VERSION 5.8 ;
BUSBITCHARS "[]" ;
DIVIDERCHAR "/" ;
UNITS
    DATABASE MICRONS 1000 ;
END UNITS

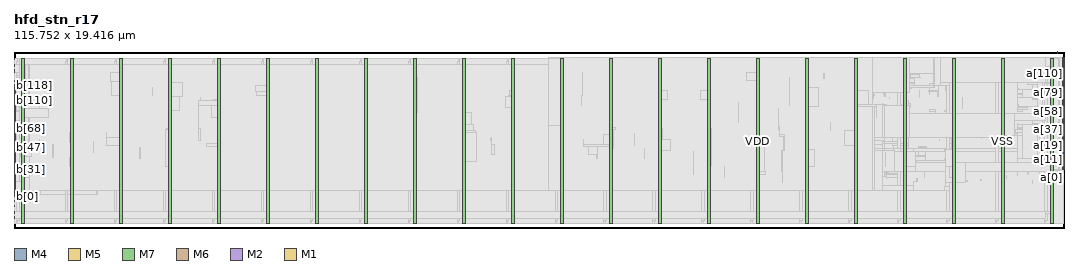
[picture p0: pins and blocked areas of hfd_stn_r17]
MACRO hfd_stn_r17
  FOREIGN hfd_stn_r17 0 0 ;
  CLASS BLOCK ;
  SIZE 115.752 BY 19.416 ;
  PIN a[0]
    DIRECTION INPUT ;
    USE SIGNAL ;
    PORT
      LAYER M4 ;
        RECT  115.56 6.432 115.752 6.456 ;
    END
  END a[0]
  PIN a[100]
    DIRECTION INPUT ;
    USE SIGNAL ;
    PORT
      LAYER M4 ;
        RECT  115.56 16.032 115.752 16.056 ;
    END
  END a[100]
  PIN a[101]
    DIRECTION INPUT ;
    USE SIGNAL ;
    PORT
      LAYER M4 ;
        RECT  115.56 16.128 115.752 16.152 ;
    END
  END a[101]
  PIN a[102]
    DIRECTION INPUT ;
    USE SIGNAL ;
    PORT
      LAYER M4 ;
        RECT  115.56 16.224 115.752 16.248 ;
    END
  END a[102]
  PIN a[103]
    DIRECTION INPUT ;
    USE SIGNAL ;
    PORT
      LAYER M4 ;
        RECT  115.56 16.32 115.752 16.344 ;
    END
  END a[103]
  PIN a[104]
    DIRECTION INPUT ;
    USE SIGNAL ;
    PORT
      LAYER M4 ;
        RECT  115.56 16.416 115.752 16.44 ;
    END
  END a[104]
  PIN a[105]
    DIRECTION INPUT ;
    USE SIGNAL ;
    PORT
      LAYER M4 ;
        RECT  115.56 16.512 115.752 16.536 ;
    END
  END a[105]
  PIN a[106]
    DIRECTION INPUT ;
    USE SIGNAL ;
    PORT
      LAYER M4 ;
        RECT  115.56 16.608 115.752 16.632 ;
    END
  END a[106]
  PIN a[107]
    DIRECTION INPUT ;
    USE SIGNAL ;
    PORT
      LAYER M4 ;
        RECT  115.56 16.704 115.752 16.728 ;
    END
  END a[107]
  PIN a[108]
    DIRECTION INPUT ;
    USE SIGNAL ;
    PORT
      LAYER M4 ;
        RECT  115.56 16.8 115.752 16.824 ;
    END
  END a[108]
  PIN a[109]
    DIRECTION INPUT ;
    USE SIGNAL ;
    PORT
      LAYER M4 ;
        RECT  115.56 16.896 115.752 16.92 ;
    END
  END a[109]
  PIN a[10]
    DIRECTION INPUT ;
    USE SIGNAL ;
    PORT
      LAYER M4 ;
        RECT  115.56 7.392 115.752 7.416 ;
    END
  END a[10]
  PIN a[110]
    DIRECTION INPUT ;
    USE SIGNAL ;
    PORT
      LAYER M4 ;
        RECT  115.56 16.992 115.752 17.016 ;
    END
  END a[110]
  PIN a[111]
    DIRECTION INPUT ;
    USE SIGNAL ;
    PORT
      LAYER M4 ;
        RECT  115.56 17.088 115.752 17.112 ;
    END
  END a[111]
  PIN a[112]
    DIRECTION INPUT ;
    USE SIGNAL ;
    PORT
      LAYER M4 ;
        RECT  115.56 17.184 115.752 17.208 ;
    END
  END a[112]
  PIN a[113]
    DIRECTION INPUT ;
    USE SIGNAL ;
    PORT
      LAYER M4 ;
        RECT  115.56 17.28 115.752 17.304 ;
    END
  END a[113]
  PIN a[114]
    DIRECTION INPUT ;
    USE SIGNAL ;
    PORT
      LAYER M4 ;
        RECT  115.56 17.376 115.752 17.4 ;
    END
  END a[114]
  PIN a[115]
    DIRECTION INPUT ;
    USE SIGNAL ;
    PORT
      LAYER M4 ;
        RECT  115.56 17.472 115.752 17.496 ;
    END
  END a[115]
  PIN a[116]
    DIRECTION INPUT ;
    USE SIGNAL ;
    PORT
      LAYER M4 ;
        RECT  115.56 17.568 115.752 17.592 ;
    END
  END a[116]
  PIN a[117]
    DIRECTION INPUT ;
    USE SIGNAL ;
    PORT
      LAYER M4 ;
        RECT  115.56 17.664 115.752 17.688 ;
    END
  END a[117]
  PIN a[118]
    DIRECTION INPUT ;
    USE SIGNAL ;
    PORT
      LAYER M4 ;
        RECT  115.56 17.76 115.752 17.784 ;
    END
  END a[118]
  PIN a[119]
    DIRECTION INPUT ;
    USE SIGNAL ;
    PORT
      LAYER M4 ;
        RECT  115.56 17.856 115.752 17.88 ;
    END
  END a[119]
  PIN a[11]
    DIRECTION INPUT ;
    USE SIGNAL ;
    PORT
      LAYER M4 ;
        RECT  115.56 7.488 115.752 7.512 ;
    END
  END a[11]
  PIN a[120]
    DIRECTION INPUT ;
    USE SIGNAL ;
    PORT
      LAYER M4 ;
        RECT  115.56 17.952 115.752 17.976 ;
    END
  END a[120]
  PIN a[121]
    DIRECTION INPUT ;
    USE SIGNAL ;
    PORT
      LAYER M4 ;
        RECT  115.56 18.048 115.752 18.072 ;
    END
  END a[121]
  PIN a[122]
    DIRECTION INPUT ;
    USE SIGNAL ;
    PORT
      LAYER M4 ;
        RECT  115.56 18.144 115.752 18.168 ;
    END
  END a[122]
  PIN a[123]
    DIRECTION INPUT ;
    USE SIGNAL ;
    PORT
      LAYER M4 ;
        RECT  115.56 18.24 115.752 18.264 ;
    END
  END a[123]
  PIN a[124]
    DIRECTION INPUT ;
    USE SIGNAL ;
    PORT
      LAYER M4 ;
        RECT  115.56 18.336 115.752 18.36 ;
    END
  END a[124]
  PIN a[125]
    DIRECTION INPUT ;
    USE SIGNAL ;
    PORT
      LAYER M4 ;
        RECT  115.56 18.432 115.752 18.456 ;
    END
  END a[125]
  PIN a[126]
    DIRECTION INPUT ;
    USE SIGNAL ;
    PORT
      LAYER M4 ;
        RECT  115.56 18.528 115.752 18.552 ;
    END
  END a[126]
  PIN a[127]
    DIRECTION INPUT ;
    USE SIGNAL ;
    PORT
      LAYER M4 ;
        RECT  115.56 18.624 115.752 18.648 ;
    END
  END a[127]
  PIN a[128]
    DIRECTION INPUT ;
    USE SIGNAL ;
    PORT
      LAYER M4 ;
        RECT  115.56 18.72 115.752 18.744 ;
    END
  END a[128]
  PIN a[12]
    DIRECTION INPUT ;
    USE SIGNAL ;
    PORT
      LAYER M4 ;
        RECT  115.56 7.584 115.752 7.608 ;
    END
  END a[12]
  PIN a[13]
    DIRECTION INPUT ;
    USE SIGNAL ;
    PORT
      LAYER M4 ;
        RECT  115.56 7.68 115.752 7.704 ;
    END
  END a[13]
  PIN a[14]
    DIRECTION INPUT ;
    USE SIGNAL ;
    PORT
      LAYER M4 ;
        RECT  115.56 7.776 115.752 7.8 ;
    END
  END a[14]
  PIN a[15]
    DIRECTION INPUT ;
    USE SIGNAL ;
    PORT
      LAYER M4 ;
        RECT  115.56 7.872 115.752 7.896 ;
    END
  END a[15]
  PIN a[16]
    DIRECTION INPUT ;
    USE SIGNAL ;
    PORT
      LAYER M4 ;
        RECT  115.56 7.968 115.752 7.992 ;
    END
  END a[16]
  PIN a[17]
    DIRECTION INPUT ;
    USE SIGNAL ;
    PORT
      LAYER M4 ;
        RECT  115.56 8.064 115.752 8.088 ;
    END
  END a[17]
  PIN a[18]
    DIRECTION INPUT ;
    USE SIGNAL ;
    PORT
      LAYER M4 ;
        RECT  115.56 8.16 115.752 8.184 ;
    END
  END a[18]
  PIN a[19]
    DIRECTION INPUT ;
    USE SIGNAL ;
    PORT
      LAYER M4 ;
        RECT  115.56 8.256 115.752 8.28 ;
    END
  END a[19]
  PIN a[1]
    DIRECTION INPUT ;
    USE SIGNAL ;
    PORT
      LAYER M4 ;
        RECT  115.56 6.528 115.752 6.552 ;
    END
  END a[1]
  PIN a[20]
    DIRECTION INPUT ;
    USE SIGNAL ;
    PORT
      LAYER M4 ;
        RECT  115.56 8.352 115.752 8.376 ;
    END
  END a[20]
  PIN a[21]
    DIRECTION INPUT ;
    USE SIGNAL ;
    PORT
      LAYER M4 ;
        RECT  115.56 8.448 115.752 8.472 ;
    END
  END a[21]
  PIN a[22]
    DIRECTION INPUT ;
    USE SIGNAL ;
    PORT
      LAYER M4 ;
        RECT  115.56 8.544 115.752 8.568 ;
    END
  END a[22]
  PIN a[23]
    DIRECTION INPUT ;
    USE SIGNAL ;
    PORT
      LAYER M4 ;
        RECT  115.56 8.64 115.752 8.664 ;
    END
  END a[23]
  PIN a[24]
    DIRECTION INPUT ;
    USE SIGNAL ;
    PORT
      LAYER M4 ;
        RECT  115.56 8.736 115.752 8.76 ;
    END
  END a[24]
  PIN a[25]
    DIRECTION INPUT ;
    USE SIGNAL ;
    PORT
      LAYER M4 ;
        RECT  115.56 8.832 115.752 8.856 ;
    END
  END a[25]
  PIN a[26]
    DIRECTION INPUT ;
    USE SIGNAL ;
    PORT
      LAYER M4 ;
        RECT  115.56 8.928 115.752 8.952 ;
    END
  END a[26]
  PIN a[27]
    DIRECTION INPUT ;
    USE SIGNAL ;
    PORT
      LAYER M4 ;
        RECT  115.56 9.024 115.752 9.048 ;
    END
  END a[27]
  PIN a[28]
    DIRECTION INPUT ;
    USE SIGNAL ;
    PORT
      LAYER M4 ;
        RECT  115.56 9.12 115.752 9.144 ;
    END
  END a[28]
  PIN a[29]
    DIRECTION INPUT ;
    USE SIGNAL ;
    PORT
      LAYER M4 ;
        RECT  115.56 9.216 115.752 9.24 ;
    END
  END a[29]
  PIN a[2]
    DIRECTION INPUT ;
    USE SIGNAL ;
    PORT
      LAYER M4 ;
        RECT  115.56 6.624 115.752 6.648 ;
    END
  END a[2]
  PIN a[30]
    DIRECTION INPUT ;
    USE SIGNAL ;
    PORT
      LAYER M4 ;
        RECT  115.56 9.312 115.752 9.336 ;
    END
  END a[30]
  PIN a[31]
    DIRECTION INPUT ;
    USE SIGNAL ;
    PORT
      LAYER M4 ;
        RECT  115.56 9.408 115.752 9.432 ;
    END
  END a[31]
  PIN a[32]
    DIRECTION INPUT ;
    USE SIGNAL ;
    PORT
      LAYER M4 ;
        RECT  115.56 9.504 115.752 9.528 ;
    END
  END a[32]
  PIN a[33]
    DIRECTION INPUT ;
    USE SIGNAL ;
    PORT
      LAYER M4 ;
        RECT  115.56 9.6 115.752 9.624 ;
    END
  END a[33]
  PIN a[34]
    DIRECTION INPUT ;
    USE SIGNAL ;
    PORT
      LAYER M4 ;
        RECT  115.56 9.696 115.752 9.72 ;
    END
  END a[34]
  PIN a[35]
    DIRECTION INPUT ;
    USE SIGNAL ;
    PORT
      LAYER M4 ;
        RECT  115.56 9.792 115.752 9.816 ;
    END
  END a[35]
  PIN a[36]
    DIRECTION INPUT ;
    USE SIGNAL ;
    PORT
      LAYER M4 ;
        RECT  115.56 9.888 115.752 9.912 ;
    END
  END a[36]
  PIN a[37]
    DIRECTION INPUT ;
    USE SIGNAL ;
    PORT
      LAYER M4 ;
        RECT  115.56 9.984 115.752 10.008 ;
    END
  END a[37]
  PIN a[38]
    DIRECTION INPUT ;
    USE SIGNAL ;
    PORT
      LAYER M4 ;
        RECT  115.56 10.08 115.752 10.104 ;
    END
  END a[38]
  PIN a[39]
    DIRECTION INPUT ;
    USE SIGNAL ;
    PORT
      LAYER M4 ;
        RECT  115.56 10.176 115.752 10.2 ;
    END
  END a[39]
  PIN a[3]
    DIRECTION INPUT ;
    USE SIGNAL ;
    PORT
      LAYER M4 ;
        RECT  115.56 6.72 115.752 6.744 ;
    END
  END a[3]
  PIN a[40]
    DIRECTION INPUT ;
    USE SIGNAL ;
    PORT
      LAYER M4 ;
        RECT  115.56 10.272 115.752 10.296 ;
    END
  END a[40]
  PIN a[41]
    DIRECTION INPUT ;
    USE SIGNAL ;
    PORT
      LAYER M4 ;
        RECT  115.56 10.368 115.752 10.392 ;
    END
  END a[41]
  PIN a[42]
    DIRECTION INPUT ;
    USE SIGNAL ;
    PORT
      LAYER M4 ;
        RECT  115.56 10.464 115.752 10.488 ;
    END
  END a[42]
  PIN a[43]
    DIRECTION INPUT ;
    USE SIGNAL ;
    PORT
      LAYER M4 ;
        RECT  115.56 10.56 115.752 10.584 ;
    END
  END a[43]
  PIN a[44]
    DIRECTION INPUT ;
    USE SIGNAL ;
    PORT
      LAYER M4 ;
        RECT  115.56 10.656 115.752 10.68 ;
    END
  END a[44]
  PIN a[45]
    DIRECTION INPUT ;
    USE SIGNAL ;
    PORT
      LAYER M4 ;
        RECT  115.56 10.752 115.752 10.776 ;
    END
  END a[45]
  PIN a[46]
    DIRECTION INPUT ;
    USE SIGNAL ;
    PORT
      LAYER M4 ;
        RECT  115.56 10.848 115.752 10.872 ;
    END
  END a[46]
  PIN a[47]
    DIRECTION INPUT ;
    USE SIGNAL ;
    PORT
      LAYER M4 ;
        RECT  115.56 10.944 115.752 10.968 ;
    END
  END a[47]
  PIN a[48]
    DIRECTION INPUT ;
    USE SIGNAL ;
    PORT
      LAYER M4 ;
        RECT  115.56 11.04 115.752 11.064 ;
    END
  END a[48]
  PIN a[49]
    DIRECTION INPUT ;
    USE SIGNAL ;
    PORT
      LAYER M4 ;
        RECT  115.56 11.136 115.752 11.16 ;
    END
  END a[49]
  PIN a[4]
    DIRECTION INPUT ;
    USE SIGNAL ;
    PORT
      LAYER M4 ;
        RECT  115.56 6.816 115.752 6.84 ;
    END
  END a[4]
  PIN a[50]
    DIRECTION INPUT ;
    USE SIGNAL ;
    PORT
      LAYER M4 ;
        RECT  115.56 11.232 115.752 11.256 ;
    END
  END a[50]
  PIN a[51]
    DIRECTION INPUT ;
    USE SIGNAL ;
    PORT
      LAYER M4 ;
        RECT  115.56 11.328 115.752 11.352 ;
    END
  END a[51]
  PIN a[52]
    DIRECTION INPUT ;
    USE SIGNAL ;
    PORT
      LAYER M4 ;
        RECT  115.56 11.424 115.752 11.448 ;
    END
  END a[52]
  PIN a[53]
    DIRECTION INPUT ;
    USE SIGNAL ;
    PORT
      LAYER M4 ;
        RECT  115.56 11.52 115.752 11.544 ;
    END
  END a[53]
  PIN a[54]
    DIRECTION INPUT ;
    USE SIGNAL ;
    PORT
      LAYER M4 ;
        RECT  115.56 11.616 115.752 11.64 ;
    END
  END a[54]
  PIN a[55]
    DIRECTION INPUT ;
    USE SIGNAL ;
    PORT
      LAYER M4 ;
        RECT  115.56 11.712 115.752 11.736 ;
    END
  END a[55]
  PIN a[56]
    DIRECTION INPUT ;
    USE SIGNAL ;
    PORT
      LAYER M4 ;
        RECT  115.56 11.808 115.752 11.832 ;
    END
  END a[56]
  PIN a[57]
    DIRECTION INPUT ;
    USE SIGNAL ;
    PORT
      LAYER M4 ;
        RECT  115.56 11.904 115.752 11.928 ;
    END
  END a[57]
  PIN a[58]
    DIRECTION INPUT ;
    USE SIGNAL ;
    PORT
      LAYER M4 ;
        RECT  115.56 12 115.752 12.024 ;
    END
  END a[58]
  PIN a[59]
    DIRECTION INPUT ;
    USE SIGNAL ;
    PORT
      LAYER M4 ;
        RECT  115.56 12.096 115.752 12.12 ;
    END
  END a[59]
  PIN a[5]
    DIRECTION INPUT ;
    USE SIGNAL ;
    PORT
      LAYER M4 ;
        RECT  115.56 6.912 115.752 6.936 ;
    END
  END a[5]
  PIN a[60]
    DIRECTION INPUT ;
    USE SIGNAL ;
    PORT
      LAYER M4 ;
        RECT  115.56 12.192 115.752 12.216 ;
    END
  END a[60]
  PIN a[61]
    DIRECTION INPUT ;
    USE SIGNAL ;
    PORT
      LAYER M4 ;
        RECT  115.56 12.288 115.752 12.312 ;
    END
  END a[61]
  PIN a[62]
    DIRECTION INPUT ;
    USE SIGNAL ;
    PORT
      LAYER M4 ;
        RECT  115.56 12.384 115.752 12.408 ;
    END
  END a[62]
  PIN a[63]
    DIRECTION INPUT ;
    USE SIGNAL ;
    PORT
      LAYER M4 ;
        RECT  115.56 12.48 115.752 12.504 ;
    END
  END a[63]
  PIN a[64]
    DIRECTION INPUT ;
    USE SIGNAL ;
    PORT
      LAYER M4 ;
        RECT  115.56 12.576 115.752 12.6 ;
    END
  END a[64]
  PIN a[65]
    DIRECTION INPUT ;
    USE SIGNAL ;
    PORT
      LAYER M4 ;
        RECT  115.56 12.672 115.752 12.696 ;
    END
  END a[65]
  PIN a[66]
    DIRECTION INPUT ;
    USE SIGNAL ;
    PORT
      LAYER M4 ;
        RECT  115.56 12.768 115.752 12.792 ;
    END
  END a[66]
  PIN a[67]
    DIRECTION INPUT ;
    USE SIGNAL ;
    PORT
      LAYER M4 ;
        RECT  115.56 12.864 115.752 12.888 ;
    END
  END a[67]
  PIN a[68]
    DIRECTION INPUT ;
    USE SIGNAL ;
    PORT
      LAYER M4 ;
        RECT  115.56 12.96 115.752 12.984 ;
    END
  END a[68]
  PIN a[69]
    DIRECTION INPUT ;
    USE SIGNAL ;
    PORT
      LAYER M4 ;
        RECT  115.56 13.056 115.752 13.08 ;
    END
  END a[69]
  PIN a[6]
    DIRECTION INPUT ;
    USE SIGNAL ;
    PORT
      LAYER M4 ;
        RECT  115.56 7.008 115.752 7.032 ;
    END
  END a[6]
  PIN a[70]
    DIRECTION INPUT ;
    USE SIGNAL ;
    PORT
      LAYER M4 ;
        RECT  115.56 13.152 115.752 13.176 ;
    END
  END a[70]
  PIN a[71]
    DIRECTION INPUT ;
    USE SIGNAL ;
    PORT
      LAYER M4 ;
        RECT  115.56 13.248 115.752 13.272 ;
    END
  END a[71]
  PIN a[72]
    DIRECTION INPUT ;
    USE SIGNAL ;
    PORT
      LAYER M4 ;
        RECT  115.56 13.344 115.752 13.368 ;
    END
  END a[72]
  PIN a[73]
    DIRECTION INPUT ;
    USE SIGNAL ;
    PORT
      LAYER M4 ;
        RECT  115.56 13.44 115.752 13.464 ;
    END
  END a[73]
  PIN a[74]
    DIRECTION INPUT ;
    USE SIGNAL ;
    PORT
      LAYER M4 ;
        RECT  115.56 13.536 115.752 13.56 ;
    END
  END a[74]
  PIN a[75]
    DIRECTION INPUT ;
    USE SIGNAL ;
    PORT
      LAYER M4 ;
        RECT  115.56 13.632 115.752 13.656 ;
    END
  END a[75]
  PIN a[76]
    DIRECTION INPUT ;
    USE SIGNAL ;
    PORT
      LAYER M4 ;
        RECT  115.56 13.728 115.752 13.752 ;
    END
  END a[76]
  PIN a[77]
    DIRECTION INPUT ;
    USE SIGNAL ;
    PORT
      LAYER M4 ;
        RECT  115.56 13.824 115.752 13.848 ;
    END
  END a[77]
  PIN a[78]
    DIRECTION INPUT ;
    USE SIGNAL ;
    PORT
      LAYER M4 ;
        RECT  115.56 13.92 115.752 13.944 ;
    END
  END a[78]
  PIN a[79]
    DIRECTION INPUT ;
    USE SIGNAL ;
    PORT
      LAYER M4 ;
        RECT  115.56 14.016 115.752 14.04 ;
    END
  END a[79]
  PIN a[7]
    DIRECTION INPUT ;
    USE SIGNAL ;
    PORT
      LAYER M4 ;
        RECT  115.56 7.104 115.752 7.128 ;
    END
  END a[7]
  PIN a[80]
    DIRECTION INPUT ;
    USE SIGNAL ;
    PORT
      LAYER M4 ;
        RECT  115.56 14.112 115.752 14.136 ;
    END
  END a[80]
  PIN a[81]
    DIRECTION INPUT ;
    USE SIGNAL ;
    PORT
      LAYER M4 ;
        RECT  115.56 14.208 115.752 14.232 ;
    END
  END a[81]
  PIN a[82]
    DIRECTION INPUT ;
    USE SIGNAL ;
    PORT
      LAYER M4 ;
        RECT  115.56 14.304 115.752 14.328 ;
    END
  END a[82]
  PIN a[83]
    DIRECTION INPUT ;
    USE SIGNAL ;
    PORT
      LAYER M4 ;
        RECT  115.56 14.4 115.752 14.424 ;
    END
  END a[83]
  PIN a[84]
    DIRECTION INPUT ;
    USE SIGNAL ;
    PORT
      LAYER M4 ;
        RECT  115.56 14.496 115.752 14.52 ;
    END
  END a[84]
  PIN a[85]
    DIRECTION INPUT ;
    USE SIGNAL ;
    PORT
      LAYER M4 ;
        RECT  115.56 14.592 115.752 14.616 ;
    END
  END a[85]
  PIN a[86]
    DIRECTION INPUT ;
    USE SIGNAL ;
    PORT
      LAYER M4 ;
        RECT  115.56 14.688 115.752 14.712 ;
    END
  END a[86]
  PIN a[87]
    DIRECTION INPUT ;
    USE SIGNAL ;
    PORT
      LAYER M4 ;
        RECT  115.56 14.784 115.752 14.808 ;
    END
  END a[87]
  PIN a[88]
    DIRECTION INPUT ;
    USE SIGNAL ;
    PORT
      LAYER M4 ;
        RECT  115.56 14.88 115.752 14.904 ;
    END
  END a[88]
  PIN a[89]
    DIRECTION INPUT ;
    USE SIGNAL ;
    PORT
      LAYER M4 ;
        RECT  115.56 14.976 115.752 15 ;
    END
  END a[89]
  PIN a[8]
    DIRECTION INPUT ;
    USE SIGNAL ;
    PORT
      LAYER M4 ;
        RECT  115.56 7.2 115.752 7.224 ;
    END
  END a[8]
  PIN a[90]
    DIRECTION INPUT ;
    USE SIGNAL ;
    PORT
      LAYER M4 ;
        RECT  115.56 15.072 115.752 15.096 ;
    END
  END a[90]
  PIN a[91]
    DIRECTION INPUT ;
    USE SIGNAL ;
    PORT
      LAYER M4 ;
        RECT  115.56 15.168 115.752 15.192 ;
    END
  END a[91]
  PIN a[92]
    DIRECTION INPUT ;
    USE SIGNAL ;
    PORT
      LAYER M4 ;
        RECT  115.56 15.264 115.752 15.288 ;
    END
  END a[92]
  PIN a[93]
    DIRECTION INPUT ;
    USE SIGNAL ;
    PORT
      LAYER M4 ;
        RECT  115.56 15.36 115.752 15.384 ;
    END
  END a[93]
  PIN a[94]
    DIRECTION INPUT ;
    USE SIGNAL ;
    PORT
      LAYER M4 ;
        RECT  115.56 15.456 115.752 15.48 ;
    END
  END a[94]
  PIN a[95]
    DIRECTION INPUT ;
    USE SIGNAL ;
    PORT
      LAYER M4 ;
        RECT  115.56 15.552 115.752 15.576 ;
    END
  END a[95]
  PIN a[96]
    DIRECTION INPUT ;
    USE SIGNAL ;
    PORT
      LAYER M4 ;
        RECT  115.56 15.648 115.752 15.672 ;
    END
  END a[96]
  PIN a[97]
    DIRECTION INPUT ;
    USE SIGNAL ;
    PORT
      LAYER M4 ;
        RECT  115.56 15.744 115.752 15.768 ;
    END
  END a[97]
  PIN a[98]
    DIRECTION INPUT ;
    USE SIGNAL ;
    PORT
      LAYER M4 ;
        RECT  115.56 15.84 115.752 15.864 ;
    END
  END a[98]
  PIN a[99]
    DIRECTION INPUT ;
    USE SIGNAL ;
    PORT
      LAYER M4 ;
        RECT  115.56 15.936 115.752 15.96 ;
    END
  END a[99]
  PIN a[9]
    DIRECTION INPUT ;
    USE SIGNAL ;
    PORT
      LAYER M4 ;
        RECT  115.56 7.296 115.752 7.32 ;
    END
  END a[9]
  PIN b[0]
    DIRECTION OUTPUT ;
    USE SIGNAL ;
    PORT
      LAYER M4 ;
        RECT  0 3.504 0.192 3.528 ;
    END
  END b[0]
  PIN b[100]
    DIRECTION OUTPUT ;
    USE SIGNAL ;
    PORT
      LAYER M4 ;
        RECT  0 13.104 0.192 13.128 ;
    END
  END b[100]
  PIN b[101]
    DIRECTION OUTPUT ;
    USE SIGNAL ;
    PORT
      LAYER M4 ;
        RECT  0 13.2 0.192 13.224 ;
    END
  END b[101]
  PIN b[102]
    DIRECTION OUTPUT ;
    USE SIGNAL ;
    PORT
      LAYER M4 ;
        RECT  0 13.296 0.192 13.32 ;
    END
  END b[102]
  PIN b[103]
    DIRECTION OUTPUT ;
    USE SIGNAL ;
    PORT
      LAYER M4 ;
        RECT  0 13.392 0.192 13.416 ;
    END
  END b[103]
  PIN b[104]
    DIRECTION OUTPUT ;
    USE SIGNAL ;
    PORT
      LAYER M4 ;
        RECT  0 13.488 0.192 13.512 ;
    END
  END b[104]
  PIN b[105]
    DIRECTION OUTPUT ;
    USE SIGNAL ;
    PORT
      LAYER M4 ;
        RECT  0 13.584 0.192 13.608 ;
    END
  END b[105]
  PIN b[106]
    DIRECTION OUTPUT ;
    USE SIGNAL ;
    PORT
      LAYER M4 ;
        RECT  0 13.68 0.192 13.704 ;
    END
  END b[106]
  PIN b[107]
    DIRECTION OUTPUT ;
    USE SIGNAL ;
    PORT
      LAYER M4 ;
        RECT  0 13.776 0.192 13.8 ;
    END
  END b[107]
  PIN b[108]
    DIRECTION OUTPUT ;
    USE SIGNAL ;
    PORT
      LAYER M4 ;
        RECT  0 13.872 0.192 13.896 ;
    END
  END b[108]
  PIN b[109]
    DIRECTION OUTPUT ;
    USE SIGNAL ;
    PORT
      LAYER M4 ;
        RECT  0 13.968 0.192 13.992 ;
    END
  END b[109]
  PIN b[10]
    DIRECTION OUTPUT ;
    USE SIGNAL ;
    PORT
      LAYER M4 ;
        RECT  0 4.464 0.192 4.488 ;
    END
  END b[10]
  PIN b[110]
    DIRECTION OUTPUT ;
    USE SIGNAL ;
    PORT
      LAYER M4 ;
        RECT  0 14.064 0.192 14.088 ;
    END
  END b[110]
  PIN b[111]
    DIRECTION OUTPUT ;
    USE SIGNAL ;
    PORT
      LAYER M4 ;
        RECT  0 14.16 0.192 14.184 ;
    END
  END b[111]
  PIN b[112]
    DIRECTION OUTPUT ;
    USE SIGNAL ;
    PORT
      LAYER M4 ;
        RECT  0 14.256 0.192 14.28 ;
    END
  END b[112]
  PIN b[113]
    DIRECTION OUTPUT ;
    USE SIGNAL ;
    PORT
      LAYER M4 ;
        RECT  0 14.352 0.192 14.376 ;
    END
  END b[113]
  PIN b[114]
    DIRECTION OUTPUT ;
    USE SIGNAL ;
    PORT
      LAYER M4 ;
        RECT  0 14.448 0.192 14.472 ;
    END
  END b[114]
  PIN b[115]
    DIRECTION OUTPUT ;
    USE SIGNAL ;
    PORT
      LAYER M4 ;
        RECT  0 14.544 0.192 14.568 ;
    END
  END b[115]
  PIN b[116]
    DIRECTION OUTPUT ;
    USE SIGNAL ;
    PORT
      LAYER M4 ;
        RECT  0 14.64 0.192 14.664 ;
    END
  END b[116]
  PIN b[117]
    DIRECTION OUTPUT ;
    USE SIGNAL ;
    PORT
      LAYER M4 ;
        RECT  0 14.736 0.192 14.76 ;
    END
  END b[117]
  PIN b[118]
    DIRECTION OUTPUT ;
    USE SIGNAL ;
    PORT
      LAYER M4 ;
        RECT  0 14.832 0.192 14.856 ;
    END
  END b[118]
  PIN b[119]
    DIRECTION OUTPUT ;
    USE SIGNAL ;
    PORT
      LAYER M4 ;
        RECT  0 14.928 0.192 14.952 ;
    END
  END b[119]
  PIN b[11]
    DIRECTION OUTPUT ;
    USE SIGNAL ;
    PORT
      LAYER M4 ;
        RECT  0 4.56 0.192 4.584 ;
    END
  END b[11]
  PIN b[120]
    DIRECTION OUTPUT ;
    USE SIGNAL ;
    PORT
      LAYER M4 ;
        RECT  0 15.024 0.192 15.048 ;
    END
  END b[120]
  PIN b[121]
    DIRECTION OUTPUT ;
    USE SIGNAL ;
    PORT
      LAYER M4 ;
        RECT  0 15.12 0.192 15.144 ;
    END
  END b[121]
  PIN b[122]
    DIRECTION OUTPUT ;
    USE SIGNAL ;
    PORT
      LAYER M4 ;
        RECT  0 15.216 0.192 15.24 ;
    END
  END b[122]
  PIN b[123]
    DIRECTION OUTPUT ;
    USE SIGNAL ;
    PORT
      LAYER M4 ;
        RECT  0 15.312 0.192 15.336 ;
    END
  END b[123]
  PIN b[124]
    DIRECTION OUTPUT ;
    USE SIGNAL ;
    PORT
      LAYER M4 ;
        RECT  0 15.408 0.192 15.432 ;
    END
  END b[124]
  PIN b[125]
    DIRECTION OUTPUT ;
    USE SIGNAL ;
    PORT
      LAYER M4 ;
        RECT  0 15.504 0.192 15.528 ;
    END
  END b[125]
  PIN b[126]
    DIRECTION OUTPUT ;
    USE SIGNAL ;
    PORT
      LAYER M4 ;
        RECT  0 15.6 0.192 15.624 ;
    END
  END b[126]
  PIN b[127]
    DIRECTION OUTPUT ;
    USE SIGNAL ;
    PORT
      LAYER M4 ;
        RECT  0 15.696 0.192 15.72 ;
    END
  END b[127]
  PIN b[128]
    DIRECTION OUTPUT ;
    USE SIGNAL ;
    PORT
      LAYER M4 ;
        RECT  0 15.792 0.192 15.816 ;
    END
  END b[128]
  PIN b[12]
    DIRECTION OUTPUT ;
    USE SIGNAL ;
    PORT
      LAYER M4 ;
        RECT  0 4.656 0.192 4.68 ;
    END
  END b[12]
  PIN b[13]
    DIRECTION OUTPUT ;
    USE SIGNAL ;
    PORT
      LAYER M4 ;
        RECT  0 4.752 0.192 4.776 ;
    END
  END b[13]
  PIN b[14]
    DIRECTION OUTPUT ;
    USE SIGNAL ;
    PORT
      LAYER M4 ;
        RECT  0 4.848 0.192 4.872 ;
    END
  END b[14]
  PIN b[15]
    DIRECTION OUTPUT ;
    USE SIGNAL ;
    PORT
      LAYER M4 ;
        RECT  0 4.944 0.192 4.968 ;
    END
  END b[15]
  PIN b[16]
    DIRECTION OUTPUT ;
    USE SIGNAL ;
    PORT
      LAYER M4 ;
        RECT  0 5.04 0.192 5.064 ;
    END
  END b[16]
  PIN b[17]
    DIRECTION OUTPUT ;
    USE SIGNAL ;
    PORT
      LAYER M4 ;
        RECT  0 5.136 0.192 5.16 ;
    END
  END b[17]
  PIN b[18]
    DIRECTION OUTPUT ;
    USE SIGNAL ;
    PORT
      LAYER M4 ;
        RECT  0 5.232 0.192 5.256 ;
    END
  END b[18]
  PIN b[19]
    DIRECTION OUTPUT ;
    USE SIGNAL ;
    PORT
      LAYER M4 ;
        RECT  0 5.328 0.192 5.352 ;
    END
  END b[19]
  PIN b[1]
    DIRECTION OUTPUT ;
    USE SIGNAL ;
    PORT
      LAYER M4 ;
        RECT  0 3.6 0.192 3.624 ;
    END
  END b[1]
  PIN b[20]
    DIRECTION OUTPUT ;
    USE SIGNAL ;
    PORT
      LAYER M4 ;
        RECT  0 5.424 0.192 5.448 ;
    END
  END b[20]
  PIN b[21]
    DIRECTION OUTPUT ;
    USE SIGNAL ;
    PORT
      LAYER M4 ;
        RECT  0 5.52 0.192 5.544 ;
    END
  END b[21]
  PIN b[22]
    DIRECTION OUTPUT ;
    USE SIGNAL ;
    PORT
      LAYER M4 ;
        RECT  0 5.616 0.192 5.64 ;
    END
  END b[22]
  PIN b[23]
    DIRECTION OUTPUT ;
    USE SIGNAL ;
    PORT
      LAYER M4 ;
        RECT  0 5.712 0.192 5.736 ;
    END
  END b[23]
  PIN b[24]
    DIRECTION OUTPUT ;
    USE SIGNAL ;
    PORT
      LAYER M4 ;
        RECT  0 5.808 0.192 5.832 ;
    END
  END b[24]
  PIN b[25]
    DIRECTION OUTPUT ;
    USE SIGNAL ;
    PORT
      LAYER M4 ;
        RECT  0 5.904 0.192 5.928 ;
    END
  END b[25]
  PIN b[26]
    DIRECTION OUTPUT ;
    USE SIGNAL ;
    PORT
      LAYER M4 ;
        RECT  0 6 0.192 6.024 ;
    END
  END b[26]
  PIN b[27]
    DIRECTION OUTPUT ;
    USE SIGNAL ;
    PORT
      LAYER M4 ;
        RECT  0 6.096 0.192 6.12 ;
    END
  END b[27]
  PIN b[28]
    DIRECTION OUTPUT ;
    USE SIGNAL ;
    PORT
      LAYER M4 ;
        RECT  0 6.192 0.192 6.216 ;
    END
  END b[28]
  PIN b[29]
    DIRECTION OUTPUT ;
    USE SIGNAL ;
    PORT
      LAYER M4 ;
        RECT  0 6.288 0.192 6.312 ;
    END
  END b[29]
  PIN b[2]
    DIRECTION OUTPUT ;
    USE SIGNAL ;
    PORT
      LAYER M4 ;
        RECT  0 3.696 0.192 3.72 ;
    END
  END b[2]
  PIN b[30]
    DIRECTION OUTPUT ;
    USE SIGNAL ;
    PORT
      LAYER M4 ;
        RECT  0 6.384 0.192 6.408 ;
    END
  END b[30]
  PIN b[31]
    DIRECTION OUTPUT ;
    USE SIGNAL ;
    PORT
      LAYER M4 ;
        RECT  0 6.48 0.192 6.504 ;
    END
  END b[31]
  PIN b[32]
    DIRECTION OUTPUT ;
    USE SIGNAL ;
    PORT
      LAYER M4 ;
        RECT  0 6.576 0.192 6.6 ;
    END
  END b[32]
  PIN b[33]
    DIRECTION OUTPUT ;
    USE SIGNAL ;
    PORT
      LAYER M4 ;
        RECT  0 6.672 0.192 6.696 ;
    END
  END b[33]
  PIN b[34]
    DIRECTION OUTPUT ;
    USE SIGNAL ;
    PORT
      LAYER M4 ;
        RECT  0 6.768 0.192 6.792 ;
    END
  END b[34]
  PIN b[35]
    DIRECTION OUTPUT ;
    USE SIGNAL ;
    PORT
      LAYER M4 ;
        RECT  0 6.864 0.192 6.888 ;
    END
  END b[35]
  PIN b[36]
    DIRECTION OUTPUT ;
    USE SIGNAL ;
    PORT
      LAYER M4 ;
        RECT  0 6.96 0.192 6.984 ;
    END
  END b[36]
  PIN b[37]
    DIRECTION OUTPUT ;
    USE SIGNAL ;
    PORT
      LAYER M4 ;
        RECT  0 7.056 0.192 7.08 ;
    END
  END b[37]
  PIN b[38]
    DIRECTION OUTPUT ;
    USE SIGNAL ;
    PORT
      LAYER M4 ;
        RECT  0 7.152 0.192 7.176 ;
    END
  END b[38]
  PIN b[39]
    DIRECTION OUTPUT ;
    USE SIGNAL ;
    PORT
      LAYER M4 ;
        RECT  0 7.248 0.192 7.272 ;
    END
  END b[39]
  PIN b[3]
    DIRECTION OUTPUT ;
    USE SIGNAL ;
    PORT
      LAYER M4 ;
        RECT  0 3.792 0.192 3.816 ;
    END
  END b[3]
  PIN b[40]
    DIRECTION OUTPUT ;
    USE SIGNAL ;
    PORT
      LAYER M4 ;
        RECT  0 7.344 0.192 7.368 ;
    END
  END b[40]
  PIN b[41]
    DIRECTION OUTPUT ;
    USE SIGNAL ;
    PORT
      LAYER M4 ;
        RECT  0 7.44 0.192 7.464 ;
    END
  END b[41]
  PIN b[42]
    DIRECTION OUTPUT ;
    USE SIGNAL ;
    PORT
      LAYER M4 ;
        RECT  0 7.536 0.192 7.56 ;
    END
  END b[42]
  PIN b[43]
    DIRECTION OUTPUT ;
    USE SIGNAL ;
    PORT
      LAYER M4 ;
        RECT  0 7.632 0.192 7.656 ;
    END
  END b[43]
  PIN b[44]
    DIRECTION OUTPUT ;
    USE SIGNAL ;
    PORT
      LAYER M4 ;
        RECT  0 7.728 0.192 7.752 ;
    END
  END b[44]
  PIN b[45]
    DIRECTION OUTPUT ;
    USE SIGNAL ;
    PORT
      LAYER M4 ;
        RECT  0 7.824 0.192 7.848 ;
    END
  END b[45]
  PIN b[46]
    DIRECTION OUTPUT ;
    USE SIGNAL ;
    PORT
      LAYER M4 ;
        RECT  0 7.92 0.192 7.944 ;
    END
  END b[46]
  PIN b[47]
    DIRECTION OUTPUT ;
    USE SIGNAL ;
    PORT
      LAYER M4 ;
        RECT  0 8.016 0.192 8.04 ;
    END
  END b[47]
  PIN b[48]
    DIRECTION OUTPUT ;
    USE SIGNAL ;
    PORT
      LAYER M4 ;
        RECT  0 8.112 0.192 8.136 ;
    END
  END b[48]
  PIN b[49]
    DIRECTION OUTPUT ;
    USE SIGNAL ;
    PORT
      LAYER M4 ;
        RECT  0 8.208 0.192 8.232 ;
    END
  END b[49]
  PIN b[4]
    DIRECTION OUTPUT ;
    USE SIGNAL ;
    PORT
      LAYER M4 ;
        RECT  0 3.888 0.192 3.912 ;
    END
  END b[4]
  PIN b[50]
    DIRECTION OUTPUT ;
    USE SIGNAL ;
    PORT
      LAYER M4 ;
        RECT  0 8.304 0.192 8.328 ;
    END
  END b[50]
  PIN b[51]
    DIRECTION OUTPUT ;
    USE SIGNAL ;
    PORT
      LAYER M4 ;
        RECT  0 8.4 0.192 8.424 ;
    END
  END b[51]
  PIN b[52]
    DIRECTION OUTPUT ;
    USE SIGNAL ;
    PORT
      LAYER M4 ;
        RECT  0 8.496 0.192 8.52 ;
    END
  END b[52]
  PIN b[53]
    DIRECTION OUTPUT ;
    USE SIGNAL ;
    PORT
      LAYER M4 ;
        RECT  0 8.592 0.192 8.616 ;
    END
  END b[53]
  PIN b[54]
    DIRECTION OUTPUT ;
    USE SIGNAL ;
    PORT
      LAYER M4 ;
        RECT  0 8.688 0.192 8.712 ;
    END
  END b[54]
  PIN b[55]
    DIRECTION OUTPUT ;
    USE SIGNAL ;
    PORT
      LAYER M4 ;
        RECT  0 8.784 0.192 8.808 ;
    END
  END b[55]
  PIN b[56]
    DIRECTION OUTPUT ;
    USE SIGNAL ;
    PORT
      LAYER M4 ;
        RECT  0 8.88 0.192 8.904 ;
    END
  END b[56]
  PIN b[57]
    DIRECTION OUTPUT ;
    USE SIGNAL ;
    PORT
      LAYER M4 ;
        RECT  0 8.976 0.192 9 ;
    END
  END b[57]
  PIN b[58]
    DIRECTION OUTPUT ;
    USE SIGNAL ;
    PORT
      LAYER M4 ;
        RECT  0 9.072 0.192 9.096 ;
    END
  END b[58]
  PIN b[59]
    DIRECTION OUTPUT ;
    USE SIGNAL ;
    PORT
      LAYER M4 ;
        RECT  0 9.168 0.192 9.192 ;
    END
  END b[59]
  PIN b[5]
    DIRECTION OUTPUT ;
    USE SIGNAL ;
    PORT
      LAYER M4 ;
        RECT  0 3.984 0.192 4.008 ;
    END
  END b[5]
  PIN b[60]
    DIRECTION OUTPUT ;
    USE SIGNAL ;
    PORT
      LAYER M4 ;
        RECT  0 9.264 0.192 9.288 ;
    END
  END b[60]
  PIN b[61]
    DIRECTION OUTPUT ;
    USE SIGNAL ;
    PORT
      LAYER M4 ;
        RECT  0 9.36 0.192 9.384 ;
    END
  END b[61]
  PIN b[62]
    DIRECTION OUTPUT ;
    USE SIGNAL ;
    PORT
      LAYER M4 ;
        RECT  0 9.456 0.192 9.48 ;
    END
  END b[62]
  PIN b[63]
    DIRECTION OUTPUT ;
    USE SIGNAL ;
    PORT
      LAYER M4 ;
        RECT  0 9.552 0.192 9.576 ;
    END
  END b[63]
  PIN b[64]
    DIRECTION OUTPUT ;
    USE SIGNAL ;
    PORT
      LAYER M4 ;
        RECT  0 9.648 0.192 9.672 ;
    END
  END b[64]
  PIN b[65]
    DIRECTION OUTPUT ;
    USE SIGNAL ;
    PORT
      LAYER M4 ;
        RECT  0 9.744 0.192 9.768 ;
    END
  END b[65]
  PIN b[66]
    DIRECTION OUTPUT ;
    USE SIGNAL ;
    PORT
      LAYER M4 ;
        RECT  0 9.84 0.192 9.864 ;
    END
  END b[66]
  PIN b[67]
    DIRECTION OUTPUT ;
    USE SIGNAL ;
    PORT
      LAYER M4 ;
        RECT  0 9.936 0.192 9.96 ;
    END
  END b[67]
  PIN b[68]
    DIRECTION OUTPUT ;
    USE SIGNAL ;
    PORT
      LAYER M4 ;
        RECT  0 10.032 0.192 10.056 ;
    END
  END b[68]
  PIN b[69]
    DIRECTION OUTPUT ;
    USE SIGNAL ;
    PORT
      LAYER M4 ;
        RECT  0 10.128 0.192 10.152 ;
    END
  END b[69]
  PIN b[6]
    DIRECTION OUTPUT ;
    USE SIGNAL ;
    PORT
      LAYER M4 ;
        RECT  0 4.08 0.192 4.104 ;
    END
  END b[6]
  PIN b[70]
    DIRECTION OUTPUT ;
    USE SIGNAL ;
    PORT
      LAYER M4 ;
        RECT  0 10.224 0.192 10.248 ;
    END
  END b[70]
  PIN b[71]
    DIRECTION OUTPUT ;
    USE SIGNAL ;
    PORT
      LAYER M4 ;
        RECT  0 10.32 0.192 10.344 ;
    END
  END b[71]
  PIN b[72]
    DIRECTION OUTPUT ;
    USE SIGNAL ;
    PORT
      LAYER M4 ;
        RECT  0 10.416 0.192 10.44 ;
    END
  END b[72]
  PIN b[73]
    DIRECTION OUTPUT ;
    USE SIGNAL ;
    PORT
      LAYER M4 ;
        RECT  0 10.512 0.192 10.536 ;
    END
  END b[73]
  PIN b[74]
    DIRECTION OUTPUT ;
    USE SIGNAL ;
    PORT
      LAYER M4 ;
        RECT  0 10.608 0.192 10.632 ;
    END
  END b[74]
  PIN b[75]
    DIRECTION OUTPUT ;
    USE SIGNAL ;
    PORT
      LAYER M4 ;
        RECT  0 10.704 0.192 10.728 ;
    END
  END b[75]
  PIN b[76]
    DIRECTION OUTPUT ;
    USE SIGNAL ;
    PORT
      LAYER M4 ;
        RECT  0 10.8 0.192 10.824 ;
    END
  END b[76]
  PIN b[77]
    DIRECTION OUTPUT ;
    USE SIGNAL ;
    PORT
      LAYER M4 ;
        RECT  0 10.896 0.192 10.92 ;
    END
  END b[77]
  PIN b[78]
    DIRECTION OUTPUT ;
    USE SIGNAL ;
    PORT
      LAYER M4 ;
        RECT  0 10.992 0.192 11.016 ;
    END
  END b[78]
  PIN b[79]
    DIRECTION OUTPUT ;
    USE SIGNAL ;
    PORT
      LAYER M4 ;
        RECT  0 11.088 0.192 11.112 ;
    END
  END b[79]
  PIN b[7]
    DIRECTION OUTPUT ;
    USE SIGNAL ;
    PORT
      LAYER M4 ;
        RECT  0 4.176 0.192 4.2 ;
    END
  END b[7]
  PIN b[80]
    DIRECTION OUTPUT ;
    USE SIGNAL ;
    PORT
      LAYER M4 ;
        RECT  0 11.184 0.192 11.208 ;
    END
  END b[80]
  PIN b[81]
    DIRECTION OUTPUT ;
    USE SIGNAL ;
    PORT
      LAYER M4 ;
        RECT  0 11.28 0.192 11.304 ;
    END
  END b[81]
  PIN b[82]
    DIRECTION OUTPUT ;
    USE SIGNAL ;
    PORT
      LAYER M4 ;
        RECT  0 11.376 0.192 11.4 ;
    END
  END b[82]
  PIN b[83]
    DIRECTION OUTPUT ;
    USE SIGNAL ;
    PORT
      LAYER M4 ;
        RECT  0 11.472 0.192 11.496 ;
    END
  END b[83]
  PIN b[84]
    DIRECTION OUTPUT ;
    USE SIGNAL ;
    PORT
      LAYER M4 ;
        RECT  0 11.568 0.192 11.592 ;
    END
  END b[84]
  PIN b[85]
    DIRECTION OUTPUT ;
    USE SIGNAL ;
    PORT
      LAYER M4 ;
        RECT  0 11.664 0.192 11.688 ;
    END
  END b[85]
  PIN b[86]
    DIRECTION OUTPUT ;
    USE SIGNAL ;
    PORT
      LAYER M4 ;
        RECT  0 11.76 0.192 11.784 ;
    END
  END b[86]
  PIN b[87]
    DIRECTION OUTPUT ;
    USE SIGNAL ;
    PORT
      LAYER M4 ;
        RECT  0 11.856 0.192 11.88 ;
    END
  END b[87]
  PIN b[88]
    DIRECTION OUTPUT ;
    USE SIGNAL ;
    PORT
      LAYER M4 ;
        RECT  0 11.952 0.192 11.976 ;
    END
  END b[88]
  PIN b[89]
    DIRECTION OUTPUT ;
    USE SIGNAL ;
    PORT
      LAYER M4 ;
        RECT  0 12.048 0.192 12.072 ;
    END
  END b[89]
  PIN b[8]
    DIRECTION OUTPUT ;
    USE SIGNAL ;
    PORT
      LAYER M4 ;
        RECT  0 4.272 0.192 4.296 ;
    END
  END b[8]
  PIN b[90]
    DIRECTION OUTPUT ;
    USE SIGNAL ;
    PORT
      LAYER M4 ;
        RECT  0 12.144 0.192 12.168 ;
    END
  END b[90]
  PIN b[91]
    DIRECTION OUTPUT ;
    USE SIGNAL ;
    PORT
      LAYER M4 ;
        RECT  0 12.24 0.192 12.264 ;
    END
  END b[91]
  PIN b[92]
    DIRECTION OUTPUT ;
    USE SIGNAL ;
    PORT
      LAYER M4 ;
        RECT  0 12.336 0.192 12.36 ;
    END
  END b[92]
  PIN b[93]
    DIRECTION OUTPUT ;
    USE SIGNAL ;
    PORT
      LAYER M4 ;
        RECT  0 12.432 0.192 12.456 ;
    END
  END b[93]
  PIN b[94]
    DIRECTION OUTPUT ;
    USE SIGNAL ;
    PORT
      LAYER M4 ;
        RECT  0 12.528 0.192 12.552 ;
    END
  END b[94]
  PIN b[95]
    DIRECTION OUTPUT ;
    USE SIGNAL ;
    PORT
      LAYER M4 ;
        RECT  0 12.624 0.192 12.648 ;
    END
  END b[95]
  PIN b[96]
    DIRECTION OUTPUT ;
    USE SIGNAL ;
    PORT
      LAYER M4 ;
        RECT  0 12.72 0.192 12.744 ;
    END
  END b[96]
  PIN b[97]
    DIRECTION OUTPUT ;
    USE SIGNAL ;
    PORT
      LAYER M4 ;
        RECT  0 12.816 0.192 12.84 ;
    END
  END b[97]
  PIN b[98]
    DIRECTION OUTPUT ;
    USE SIGNAL ;
    PORT
      LAYER M4 ;
        RECT  0 12.912 0.192 12.936 ;
    END
  END b[98]
  PIN b[99]
    DIRECTION OUTPUT ;
    USE SIGNAL ;
    PORT
      LAYER M4 ;
        RECT  0 13.008 0.192 13.032 ;
    END
  END b[99]
  PIN b[9]
    DIRECTION OUTPUT ;
    USE SIGNAL ;
    PORT
      LAYER M4 ;
        RECT  0 4.368 0.192 4.392 ;
    END
  END b[9]
  PIN rst[0]
    DIRECTION INPUT ;
    USE SIGNAL ;
    PORT
      LAYER M5 ;
        RECT  115.056 19.224 115.08 19.416 ;
    END
  END rst[0]
  PIN VDD
    DIRECTION INOUT ;
    USE POWER ;
    PORT
      LAYER M7 ;
        RECT  114.256 0.531 114.544 18.639 ;
        RECT  103.456 0.531 103.744 18.639 ;
        RECT  92.656 0.531 92.944 18.639 ;
        RECT  81.856 0.531 82.144 18.639 ;
        RECT  71.056 0.531 71.344 18.639 ;
        RECT  60.256 0.531 60.544 18.639 ;
        RECT  49.456 0.531 49.744 18.639 ;
        RECT  38.656 0.531 38.944 18.639 ;
        RECT  27.856 0.531 28.144 18.639 ;
        RECT  17.056 0.531 17.344 18.639 ;
        RECT  6.256 0.531 6.544 18.639 ;
      LAYER M6 ;
        RECT  0 17.772 0.032 18.06 ;
        RECT  0 12.372 0.032 12.66 ;
        RECT  0 6.972 0.032 7.26 ;
        RECT  0 1.572 0.032 1.86 ;
      LAYER M2 ;
        RECT  0 18.621 0.018 18.639 ;
        RECT  0 18.081 0.018 18.099 ;
        RECT  0 17.541 0.018 17.559 ;
        RECT  0 17.001 0.018 17.019 ;
        RECT  0 16.461 0.018 16.479 ;
        RECT  0 15.921 0.018 15.939 ;
        RECT  0 15.381 0.018 15.399 ;
        RECT  0 14.841 0.018 14.859 ;
        RECT  0 14.301 0.018 14.319 ;
        RECT  0 13.761 0.018 13.779 ;
        RECT  0 13.221 0.018 13.239 ;
        RECT  0 12.681 0.018 12.699 ;
        RECT  0 12.141 0.018 12.159 ;
        RECT  0 11.601 0.018 11.619 ;
        RECT  0 11.061 0.018 11.079 ;
        RECT  0 10.521 0.018 10.539 ;
        RECT  0 9.981 0.018 9.999 ;
        RECT  0 9.441 0.018 9.459 ;
        RECT  0 8.901 0.018 8.919 ;
        RECT  0 8.361 0.018 8.379 ;
        RECT  0 7.821 0.018 7.839 ;
        RECT  0 7.281 0.018 7.299 ;
        RECT  0 6.741 0.018 6.759 ;
        RECT  0 6.201 0.018 6.219 ;
        RECT  0 5.661 0.018 5.679 ;
        RECT  0 5.121 0.018 5.139 ;
        RECT  0 4.581 0.018 4.599 ;
        RECT  0 4.041 0.018 4.059 ;
        RECT  0 3.501 0.018 3.519 ;
        RECT  0 2.961 0.018 2.979 ;
        RECT  0 2.421 0.018 2.439 ;
        RECT  0 1.881 0.018 1.899 ;
        RECT  0 1.341 0.018 1.359 ;
        RECT  0 0.801 0.018 0.819 ;
      LAYER M1 ;
        RECT  0 18.621 0.018 18.639 ;
        RECT  0 18.081 0.018 18.099 ;
        RECT  0 17.541 0.018 17.559 ;
        RECT  0 17.001 0.018 17.019 ;
        RECT  0 16.461 0.018 16.479 ;
        RECT  0 15.921 0.018 15.939 ;
        RECT  0 15.381 0.018 15.399 ;
        RECT  0 14.841 0.018 14.859 ;
        RECT  0 14.301 0.018 14.319 ;
        RECT  0 13.761 0.018 13.779 ;
        RECT  0 13.221 0.018 13.239 ;
        RECT  0 12.681 0.018 12.699 ;
        RECT  0 12.141 0.018 12.159 ;
        RECT  0 11.601 0.018 11.619 ;
        RECT  0 11.061 0.018 11.079 ;
        RECT  0 10.521 0.018 10.539 ;
        RECT  0 9.981 0.018 9.999 ;
        RECT  0 9.441 0.018 9.459 ;
        RECT  0 8.901 0.018 8.919 ;
        RECT  0 8.361 0.018 8.379 ;
        RECT  0 7.821 0.018 7.839 ;
        RECT  0 7.281 0.018 7.299 ;
        RECT  0 6.741 0.018 6.759 ;
        RECT  0 6.201 0.018 6.219 ;
        RECT  0 5.661 0.018 5.679 ;
        RECT  0 5.121 0.018 5.139 ;
        RECT  0 4.581 0.018 4.599 ;
        RECT  0 4.041 0.018 4.059 ;
        RECT  0 3.501 0.018 3.519 ;
        RECT  0 2.961 0.018 2.979 ;
        RECT  0 2.421 0.018 2.439 ;
        RECT  0 1.881 0.018 1.899 ;
        RECT  0 1.341 0.018 1.359 ;
        RECT  0 0.801 0.018 0.819 ;
    END
  END VDD
  PIN VSS
    DIRECTION INOUT ;
    USE GROUND ;
    PORT
      LAYER M7 ;
        RECT  108.856 0.531 109.144 18.639 ;
        RECT  98.056 0.531 98.344 18.639 ;
        RECT  87.256 0.531 87.544 18.639 ;
        RECT  76.456 0.531 76.744 18.639 ;
        RECT  65.656 0.531 65.944 18.639 ;
        RECT  54.856 0.531 55.144 18.639 ;
        RECT  44.056 0.531 44.344 18.639 ;
        RECT  33.256 0.531 33.544 18.639 ;
        RECT  22.456 0.531 22.744 18.639 ;
        RECT  11.656 0.531 11.944 18.639 ;
        RECT  0.856 0.531 1.144 18.639 ;
      LAYER M6 ;
        RECT  0 17.196 0.032 17.484 ;
        RECT  0 11.796 0.032 12.084 ;
        RECT  0 6.396 0.032 6.684 ;
        RECT  0 0.996 0.032 1.284 ;
      LAYER M2 ;
        RECT  0 18.351 0.018 18.369 ;
        RECT  0 17.811 0.018 17.829 ;
        RECT  0 17.271 0.018 17.289 ;
        RECT  0 16.731 0.018 16.749 ;
        RECT  0 16.191 0.018 16.209 ;
        RECT  0 15.651 0.018 15.669 ;
        RECT  0 15.111 0.018 15.129 ;
        RECT  0 14.571 0.018 14.589 ;
        RECT  0 14.031 0.018 14.049 ;
        RECT  0 13.491 0.018 13.509 ;
        RECT  0 12.951 0.018 12.969 ;
        RECT  0 12.411 0.018 12.429 ;
        RECT  0 11.871 0.018 11.889 ;
        RECT  0 11.331 0.018 11.349 ;
        RECT  0 10.791 0.018 10.809 ;
        RECT  0 10.251 0.018 10.269 ;
        RECT  0 9.711 0.018 9.729 ;
        RECT  0 9.171 0.018 9.189 ;
        RECT  0 8.631 0.018 8.649 ;
        RECT  0 8.091 0.018 8.109 ;
        RECT  0 7.551 0.018 7.569 ;
        RECT  0 7.011 0.018 7.029 ;
        RECT  0 6.471 0.018 6.489 ;
        RECT  0 5.931 0.018 5.949 ;
        RECT  0 5.391 0.018 5.409 ;
        RECT  0 4.851 0.018 4.869 ;
        RECT  0 4.311 0.018 4.329 ;
        RECT  0 3.771 0.018 3.789 ;
        RECT  0 3.231 0.018 3.249 ;
        RECT  0 2.691 0.018 2.709 ;
        RECT  0 2.151 0.018 2.169 ;
        RECT  0 1.611 0.018 1.629 ;
        RECT  0 1.071 0.018 1.089 ;
        RECT  0 0.531 0.018 0.549 ;
      LAYER M1 ;
        RECT  0 18.351 0.018 18.369 ;
        RECT  0 17.811 0.018 17.829 ;
        RECT  0 17.271 0.018 17.289 ;
        RECT  0 16.731 0.018 16.749 ;
        RECT  0 16.191 0.018 16.209 ;
        RECT  0 15.651 0.018 15.669 ;
        RECT  0 15.111 0.018 15.129 ;
        RECT  0 14.571 0.018 14.589 ;
        RECT  0 14.031 0.018 14.049 ;
        RECT  0 13.491 0.018 13.509 ;
        RECT  0 12.951 0.018 12.969 ;
        RECT  0 12.411 0.018 12.429 ;
        RECT  0 11.871 0.018 11.889 ;
        RECT  0 11.331 0.018 11.349 ;
        RECT  0 10.791 0.018 10.809 ;
        RECT  0 10.251 0.018 10.269 ;
        RECT  0 9.711 0.018 9.729 ;
        RECT  0 9.171 0.018 9.189 ;
        RECT  0 8.631 0.018 8.649 ;
        RECT  0 8.091 0.018 8.109 ;
        RECT  0 7.551 0.018 7.569 ;
        RECT  0 7.011 0.018 7.029 ;
        RECT  0 6.471 0.018 6.489 ;
        RECT  0 5.931 0.018 5.949 ;
        RECT  0 5.391 0.018 5.409 ;
        RECT  0 4.851 0.018 4.869 ;
        RECT  0 4.311 0.018 4.329 ;
        RECT  0 3.771 0.018 3.789 ;
        RECT  0 3.231 0.018 3.249 ;
        RECT  0 2.691 0.018 2.709 ;
        RECT  0 2.151 0.018 2.169 ;
        RECT  0 1.611 0.018 1.629 ;
        RECT  0 1.071 0.018 1.089 ;
        RECT  0 0.531 0.018 0.549 ;
    END
  END VSS
  OBS
    LAYER RVTN ;
     RECT  0 0.54 115.722 0.675 ;
     RECT  0 0.945 115.722 1.215 ;
     RECT  0 1.485 115.722 1.755 ;
     RECT  0 2.025 115.722 2.295 ;
     RECT  0 2.565 115.722 2.835 ;
     RECT  0 3.105 115.722 3.375 ;
     RECT  0 3.645 115.722 3.915 ;
     RECT  0 4.185 115.722 4.455 ;
     RECT  0 4.725 115.722 4.995 ;
     RECT  0 5.265 115.722 5.535 ;
     RECT  0 5.805 115.722 6.075 ;
     RECT  0 6.345 115.722 6.615 ;
     RECT  0 6.885 115.722 7.155 ;
     RECT  0 7.425 115.722 7.695 ;
     RECT  0 7.965 115.722 8.235 ;
     RECT  0 8.505 115.722 8.775 ;
     RECT  0 9.045 115.722 9.315 ;
     RECT  0 9.585 115.722 9.855 ;
     RECT  0 10.125 115.722 10.395 ;
     RECT  0 10.665 115.722 10.935 ;
     RECT  0 11.205 115.722 11.475 ;
     RECT  0 11.745 115.722 12.015 ;
     RECT  0 12.285 115.722 12.555 ;
     RECT  0 12.825 115.722 13.095 ;
     RECT  0 13.365 115.722 13.635 ;
     RECT  0 13.905 115.722 14.175 ;
     RECT  0 14.445 115.722 14.715 ;
     RECT  0 14.985 115.722 15.255 ;
     RECT  0 15.525 115.722 15.795 ;
     RECT  0 16.065 115.722 16.335 ;
     RECT  0 16.605 115.722 16.875 ;
     RECT  0 17.145 115.722 17.415 ;
     RECT  0 17.685 115.722 17.955 ;
     RECT  0 18.225 115.722 18.495 ;
    LAYER RVTP ;
     RECT  0 0.675 115.722 0.945 ;
     RECT  0 1.215 115.722 1.485 ;
     RECT  0 1.755 115.722 2.025 ;
     RECT  0 2.295 115.722 2.565 ;
     RECT  0 2.835 115.722 3.105 ;
     RECT  0 3.375 115.722 3.645 ;
     RECT  0 3.915 115.722 4.185 ;
     RECT  0 4.455 115.722 4.725 ;
     RECT  0 4.995 115.722 5.265 ;
     RECT  0 5.535 115.722 5.805 ;
     RECT  0 6.075 115.722 6.345 ;
     RECT  0 6.615 115.722 6.885 ;
     RECT  0 7.155 115.722 7.425 ;
     RECT  0 7.695 115.722 7.965 ;
     RECT  0 8.235 115.722 8.505 ;
     RECT  0 8.775 115.722 9.045 ;
     RECT  0 9.315 115.722 9.585 ;
     RECT  0 9.855 115.722 10.125 ;
     RECT  0 10.395 115.722 10.665 ;
     RECT  0 10.935 115.722 11.205 ;
     RECT  0 11.475 115.722 11.745 ;
     RECT  0 12.015 115.722 12.285 ;
     RECT  0 12.555 115.722 12.825 ;
     RECT  0 13.095 115.722 13.365 ;
     RECT  0 13.635 115.722 13.905 ;
     RECT  0 14.175 115.722 14.445 ;
     RECT  0 14.715 115.722 14.985 ;
     RECT  0 15.255 115.722 15.525 ;
     RECT  0 15.795 115.722 16.065 ;
     RECT  0 16.335 115.722 16.605 ;
     RECT  0 16.875 115.722 17.145 ;
     RECT  0 17.415 115.722 17.685 ;
     RECT  0 17.955 115.722 18.225 ;
     RECT  0 18.495 115.722 18.63 ;
    LAYER M1 ;
     RECT  0 0.531 115.722 18.639 ;
    LAYER M2 ;
     RECT  0 0.531 115.722 18.639 ;
    LAYER M3 ;
     RECT  0.255 0.523 0.345 0.793 ;
     RECT  5.655 0.523 5.745 0.793 ;
     RECT  11.055 0.523 11.145 0.793 ;
     RECT  16.455 0.523 16.545 0.793 ;
     RECT  21.855 0.523 21.945 0.793 ;
     RECT  27.255 0.523 27.345 0.793 ;
     RECT  32.655 0.523 32.745 0.793 ;
     RECT  38.055 0.523 38.145 0.793 ;
     RECT  43.455 0.523 43.545 0.793 ;
     RECT  48.855 0.523 48.945 0.793 ;
     RECT  54.255 0.523 54.345 0.793 ;
     RECT  59.655 0.523 59.745 0.793 ;
     RECT  65.055 0.523 65.145 0.793 ;
     RECT  70.455 0.523 70.545 0.793 ;
     RECT  75.855 0.523 75.945 0.793 ;
     RECT  81.255 0.523 81.345 0.793 ;
     RECT  86.655 0.523 86.745 0.793 ;
     RECT  92.055 0.523 92.145 0.793 ;
     RECT  97.455 0.523 97.545 0.793 ;
     RECT  102.855 0.523 102.945 0.793 ;
     RECT  108.255 0.523 108.345 0.793 ;
     RECT  113.655 0.523 113.745 0.793 ;
     RECT  0.255 0.793 0.537 3.403 ;
     RECT  0.216 3.403 0.537 3.643 ;
     RECT  0.216 3.643 0.882 3.685 ;
     RECT  1.692 3.787 1.71 3.979 ;
     RECT  0.036 3.685 0.882 4.219 ;
     RECT  1.692 3.979 1.962 4.219 ;
     RECT  0.036 4.219 1.962 4.363 ;
     RECT  2.844 4.267 2.862 4.363 ;
     RECT  0.036 4.363 2.862 4.379 ;
     RECT  11.055 0.793 11.337 4.531 ;
     RECT  9.144 3.691 9.162 4.559 ;
     RECT  78.696 4.555 78.714 4.649 ;
     RECT  102.855 0.793 103.137 4.801 ;
     RECT  75.855 0.793 76.137 4.891 ;
     RECT  83.88 4.555 83.898 4.919 ;
     RECT  75.24 4.891 76.137 4.928 ;
     RECT  11.055 4.531 11.898 4.939 ;
     RECT  102.816 4.801 103.137 4.973 ;
     RECT  84.96 4.999 84.978 5.069 ;
     RECT  81.255 0.793 81.537 5.131 ;
     RECT  5.655 0.793 5.937 5.161 ;
     RECT  16.455 0.793 16.737 5.161 ;
     RECT  73.836 5.131 73.854 5.189 ;
     RECT  81.255 5.131 81.738 5.189 ;
     RECT  105.048 5.131 105.066 5.189 ;
     RECT  112.284 4.891 112.302 5.189 ;
     RECT  16.2 5.161 16.737 5.261 ;
     RECT  38.055 0.793 38.337 5.269 ;
     RECT  113.655 0.793 113.937 5.269 ;
     RECT  86.655 0.793 86.937 5.305 ;
     RECT  113.328 5.269 113.937 5.305 ;
     RECT  0.036 4.379 1.098 5.323 ;
     RECT  14.832 5.269 14.85 5.341 ;
     RECT  17.748 5.269 17.766 5.341 ;
     RECT  21.855 0.793 22.137 5.341 ;
     RECT  106.596 5.269 106.614 5.369 ;
     RECT  9.36 5.341 9.45 5.459 ;
     RECT  10.8 4.939 11.898 5.459 ;
     RECT  14.832 5.341 14.886 5.459 ;
     RECT  17.604 5.341 17.766 5.459 ;
     RECT  21.348 5.341 22.137 5.459 ;
     RECT  37.548 5.269 38.337 5.459 ;
     RECT  86.655 5.305 87.606 5.459 ;
     RECT  99.54 5.131 99.558 5.459 ;
     RECT  14.868 5.459 14.886 5.495 ;
     RECT  17.604 5.459 17.694 5.495 ;
     RECT  10.8 5.459 11.61 5.501 ;
     RECT  0.036 5.323 1.134 5.515 ;
     RECT  2.016 4.379 2.862 5.515 ;
     RECT  113.328 5.305 114.03 5.575 ;
     RECT  10.8 5.501 11.337 5.611 ;
     RECT  96.192 5.431 96.21 5.611 ;
     RECT  97.455 0.793 97.737 5.611 ;
     RECT  104.076 5.305 104.094 5.645 ;
     RECT  89.064 5.611 89.082 5.701 ;
     RECT  4.032 5.035 4.05 5.707 ;
     RECT  5.076 5.161 5.937 5.707 ;
     RECT  10.62 5.611 11.337 5.729 ;
     RECT  88.956 5.701 89.082 5.741 ;
     RECT  78.588 4.801 78.606 5.809 ;
     RECT  109.44 5.431 109.458 5.837 ;
     RECT  78.588 5.809 79.29 5.845 ;
     RECT  113.04 5.575 114.03 5.845 ;
     RECT  115.02 5.431 115.038 5.845 ;
     RECT  74.988 5.071 75.006 5.872 ;
     RECT  74.988 5.872 75.042 5.881 ;
     RECT  75.855 4.928 76.137 5.881 ;
     RECT  76.86 5.233 76.878 5.881 ;
     RECT  96.192 5.611 97.737 5.881 ;
     RECT  4.032 5.707 5.937 5.909 ;
     RECT  78.084 5.845 79.29 5.909 ;
     RECT  72.468 5.803 72.486 5.999 ;
     RECT  83.232 5.341 83.25 5.999 ;
     RECT  96.084 5.881 97.737 5.999 ;
     RECT  111.816 5.881 111.834 6.007 ;
     RECT  113.04 5.845 115.038 6.043 ;
     RECT  78.084 5.909 78.462 6.071 ;
     RECT  111.744 6.007 111.834 6.071 ;
     RECT  85.536 5.707 85.554 6.091 ;
     RECT  74.844 5.881 75.042 6.143 ;
     RECT  79.2 5.909 79.29 6.143 ;
     RECT  65.055 0.793 65.337 6.151 ;
     RECT  84.996 6.091 85.554 6.151 ;
     RECT  89.064 5.741 89.082 6.151 ;
     RECT  90.072 5.881 90.09 6.151 ;
     RECT  96.084 5.999 96.426 6.151 ;
     RECT  82.296 6.151 82.314 6.221 ;
     RECT  65.055 6.151 65.718 6.232 ;
     RECT  75.855 5.881 76.878 6.235 ;
     RECT  65.055 6.232 65.79 6.269 ;
     RECT  89.064 6.151 90.738 6.269 ;
     RECT  113.04 6.043 115.506 6.269 ;
     RECT  75.855 6.235 76.95 6.275 ;
     RECT  4.176 5.909 5.937 6.277 ;
     RECT  6.84 6.091 6.858 6.277 ;
     RECT  110.592 5.773 110.61 6.313 ;
     RECT  94.356 6.187 94.374 6.349 ;
     RECT  110.592 6.313 110.646 6.413 ;
     RECT  17.604 5.495 17.622 6.421 ;
     RECT  84.996 6.151 85.698 6.421 ;
     RECT  90.648 6.269 90.738 6.421 ;
     RECT  111.744 6.071 111.762 6.449 ;
     RECT  12.528 5.881 12.546 6.511 ;
     RECT  100.332 5.611 100.35 6.511 ;
     RECT  4.176 6.277 6.858 6.539 ;
     RECT  12.456 6.511 12.546 6.539 ;
     RECT  17.604 6.421 17.658 6.539 ;
     RECT  61.02 6.283 61.038 6.539 ;
     RECT  90.648 6.421 90.882 6.539 ;
     RECT  100.26 6.511 100.35 6.539 ;
     RECT  11.055 5.729 11.337 6.547 ;
     RECT  86.655 5.459 86.937 6.547 ;
     RECT  11.055 6.547 11.61 6.571 ;
     RECT  0.036 5.515 2.862 6.575 ;
     RECT  89.064 6.269 89.226 6.575 ;
     RECT  99.396 6.547 99.414 6.605 ;
     RECT  12.456 6.539 12.474 6.611 ;
     RECT  14.832 6.421 14.85 6.611 ;
     RECT  17.64 6.539 17.658 6.611 ;
     RECT  100.26 6.539 100.278 6.611 ;
     RECT  74.052 6.283 74.07 6.619 ;
     RECT  92.055 0.793 92.337 6.667 ;
     RECT  21.384 5.459 22.137 6.691 ;
     RECT  61.956 6.619 61.974 6.691 ;
     RECT  79.2 6.143 79.218 6.691 ;
     RECT  92.055 6.667 92.466 6.691 ;
     RECT  94.104 6.349 94.374 6.691 ;
     RECT  18.828 6.547 18.846 6.719 ;
     RECT  57.024 6.619 57.042 6.719 ;
     RECT  61.884 6.691 61.974 6.719 ;
     RECT  74.052 6.619 74.682 6.719 ;
     RECT  79.128 6.691 79.218 6.719 ;
     RECT  90.648 6.539 90.738 6.749 ;
     RECT  8.604 6.331 8.622 6.763 ;
     RECT  63.936 6.283 63.954 6.781 ;
     RECT  78.084 6.071 78.174 6.781 ;
     RECT  4.176 6.539 4.878 6.809 ;
     RECT  5.655 6.539 6.858 6.809 ;
     RECT  8.424 6.763 8.622 6.809 ;
     RECT  9.36 5.459 9.378 6.809 ;
     RECT  21.096 6.691 22.137 6.809 ;
     RECT  63.864 6.781 63.954 6.809 ;
     RECT  84.924 6.421 85.698 6.809 ;
     RECT  90.648 6.749 90.702 6.809 ;
     RECT  95.904 6.151 96.426 6.809 ;
     RECT  4.176 6.809 4.734 6.811 ;
     RECT  86.652 6.547 86.937 6.817 ;
     RECT  113.04 6.269 115.398 6.817 ;
     RECT  84.924 6.809 85.23 6.845 ;
     RECT  92.055 6.691 92.538 6.845 ;
     RECT  94.104 6.691 94.662 6.845 ;
     RECT  95.904 6.809 96.39 6.845 ;
     RECT  4.032 6.811 4.734 6.851 ;
     RECT  5.655 6.809 5.994 6.851 ;
     RECT  0.252 6.575 2.862 6.859 ;
     RECT  39.924 5.503 39.942 6.859 ;
     RECT  86.22 6.817 86.937 6.859 ;
     RECT  95.904 6.845 96.282 6.889 ;
     RECT  94.32 6.845 94.662 6.907 ;
     RECT  95.508 6.889 96.282 6.907 ;
     RECT  21.096 6.809 21.114 6.925 ;
     RECT  4.464 6.851 4.734 6.953 ;
     RECT  86.22 6.859 87.246 6.989 ;
     RECT  98.496 6.889 98.586 6.989 ;
     RECT  112.86 6.817 115.398 6.989 ;
     RECT  39.528 6.859 39.942 7.079 ;
     RECT  84.924 6.845 84.942 7.079 ;
     RECT  86.655 6.989 87.246 7.079 ;
     RECT  90.648 6.809 90.666 7.079 ;
     RECT  94.32 6.907 96.282 7.079 ;
     RECT  94.32 7.079 95.31 7.115 ;
     RECT  73.188 6.151 73.206 7.123 ;
     RECT  113.22 6.989 115.398 7.133 ;
     RECT  96.264 7.079 96.282 7.151 ;
     RECT  70.455 0.793 70.737 7.189 ;
     RECT  10.836 6.571 11.61 7.195 ;
     RECT  67.896 7.189 67.914 7.229 ;
     RECT  70.455 7.189 71.262 7.229 ;
     RECT  70.455 7.229 70.866 7.231 ;
     RECT  77.976 6.781 78.174 7.231 ;
     RECT  6.876 7.231 6.894 7.277 ;
     RECT  43.455 0.793 43.737 7.321 ;
     RECT  0.252 6.859 2.898 7.339 ;
     RECT  0.216 7.339 2.898 7.349 ;
     RECT  10.836 7.195 11.718 7.349 ;
     RECT  44.676 6.151 44.694 7.349 ;
     RECT  113.22 7.133 115.254 7.349 ;
     RECT  43.455 7.321 43.794 7.373 ;
     RECT  20.88 6.925 21.114 7.421 ;
     RECT  84.672 7.231 84.69 7.421 ;
     RECT  72.936 7.123 73.206 7.429 ;
     RECT  74.052 6.719 74.142 7.429 ;
     RECT  102.855 4.973 103.137 7.435 ;
     RECT  61.884 6.719 61.902 7.465 ;
     RECT  66.528 6.151 66.546 7.465 ;
     RECT  72.936 7.429 74.142 7.465 ;
     RECT  98.568 6.989 98.586 7.465 ;
     RECT  72.432 7.465 74.142 7.483 ;
     RECT  4.464 6.953 4.698 7.493 ;
     RECT  0.216 7.349 2.466 7.531 ;
     RECT  75.855 6.275 76.59 7.591 ;
     RECT  77.544 7.231 78.174 7.591 ;
     RECT  94.32 7.115 94.698 7.591 ;
     RECT  0.036 7.531 2.466 7.619 ;
     RECT  4.464 7.493 4.59 7.619 ;
     RECT  10.836 7.349 11.538 7.619 ;
     RECT  63.864 6.809 63.882 7.619 ;
     RECT  66.528 7.465 67.23 7.619 ;
     RECT  102.6 7.435 103.137 7.619 ;
     RECT  5.655 6.851 5.937 7.627 ;
     RECT  10.836 7.619 11.466 7.627 ;
     RECT  94.068 7.591 94.698 7.655 ;
     RECT  66.24 7.621 66.258 7.661 ;
     RECT  94.068 7.655 94.086 7.663 ;
     RECT  110.592 6.413 110.61 7.663 ;
     RECT  75.855 7.591 78.174 7.699 ;
     RECT  81.255 5.189 81.537 7.699 ;
     RECT  97.455 5.999 97.737 7.699 ;
     RECT  10.62 7.627 11.466 7.709 ;
     RECT  98.568 7.465 99.09 7.723 ;
     RECT  7.848 7.699 7.866 7.735 ;
     RECT  111.744 7.699 111.762 7.757 ;
     RECT  5.655 7.627 6.642 7.763 ;
     RECT  11.055 7.709 11.466 7.763 ;
     RECT  57.024 7.663 57.042 7.763 ;
     RECT  70.272 7.231 70.866 7.763 ;
     RECT  63.576 7.663 63.594 7.765 ;
     RECT  72.288 7.483 74.142 7.765 ;
     RECT  96.912 7.699 97.737 7.765 ;
     RECT  98.568 7.723 99.198 7.765 ;
     RECT  72.252 7.765 74.142 7.771 ;
     RECT  102.855 7.619 103.137 7.771 ;
     RECT  5.655 7.763 6.606 7.799 ;
     RECT  4.248 7.765 4.266 7.805 ;
     RECT  63.288 7.765 63.594 7.805 ;
     RECT  69.516 7.429 69.534 7.819 ;
     RECT  65.055 6.269 65.337 7.861 ;
     RECT  61.164 7.465 61.902 7.889 ;
     RECT  63.36 7.805 63.594 7.889 ;
     RECT  69.336 7.819 69.534 7.889 ;
     RECT  70.272 7.763 70.794 7.889 ;
     RECT  72.252 7.771 74.682 7.889 ;
     RECT  75.855 7.699 78.39 7.889 ;
     RECT  79.128 6.719 79.146 7.889 ;
     RECT  80.388 7.699 81.537 7.889 ;
     RECT  93.456 7.663 94.086 7.889 ;
     RECT  110.592 7.663 110.682 7.889 ;
     RECT  63.36 7.889 63.522 7.901 ;
     RECT  64.62 7.861 65.337 7.933 ;
     RECT  96.912 7.765 99.198 7.933 ;
     RECT  100.476 7.591 100.494 7.933 ;
     RECT  67.212 7.619 67.23 7.961 ;
     RECT  96.912 7.933 100.494 7.961 ;
     RECT  78.156 7.889 78.174 8.033 ;
     RECT  60.948 8.005 60.966 8.045 ;
     RECT  0.036 7.619 2.178 8.159 ;
     RECT  72.252 7.889 74.142 8.159 ;
     RECT  113.364 7.349 115.254 8.167 ;
     RECT  72.252 8.159 73.278 8.189 ;
     RECT  75.855 7.889 76.914 8.203 ;
     RECT  7.848 7.735 8.046 8.239 ;
     RECT  86.655 7.079 86.937 8.239 ;
     RECT  88.668 7.231 88.686 8.239 ;
     RECT  102.855 7.771 103.194 8.239 ;
     RECT  7.848 8.239 8.55 8.275 ;
     RECT  5.655 7.799 5.937 8.299 ;
     RECT  96.912 7.961 98.622 8.303 ;
     RECT  88.668 8.239 89.154 8.311 ;
     RECT  7.848 8.275 8.73 8.333 ;
     RECT  14.112 8.203 14.13 8.395 ;
     RECT  102.855 8.239 103.626 8.401 ;
     RECT  13.932 8.395 14.13 8.429 ;
     RECT  14.868 7.393 14.886 8.429 ;
     RECT  75.528 8.203 76.914 8.429 ;
     RECT  88.38 8.311 89.154 8.429 ;
     RECT  93.708 7.889 94.086 8.429 ;
     RECT  13.932 8.429 13.95 8.435 ;
     RECT  75.708 8.429 76.137 8.435 ;
     RECT  96.048 8.203 96.066 8.465 ;
     RECT  10.224 8.239 10.242 8.473 ;
     RECT  5.148 8.299 5.937 8.477 ;
     RECT  7.848 8.333 8.046 8.501 ;
     RECT  95.256 8.275 95.274 8.509 ;
     RECT  86.652 8.239 86.937 8.537 ;
     RECT  89.136 8.429 89.154 8.537 ;
     RECT  102.816 8.401 103.626 8.537 ;
     RECT  10.008 8.473 10.242 8.539 ;
     RECT  11.055 7.763 11.337 8.539 ;
     RECT  102.816 8.537 103.338 8.545 ;
     RECT  80.28 7.897 80.298 8.573 ;
     RECT  95.184 8.509 95.274 8.581 ;
     RECT  112.86 8.167 115.254 8.581 ;
     RECT  94.644 8.581 95.274 8.587 ;
     RECT  88.164 8.545 88.182 8.621 ;
     RECT  102.636 8.545 103.338 8.621 ;
     RECT  90.648 8.275 90.666 8.635 ;
     RECT  72.252 8.189 72.45 8.699 ;
     RECT  73.188 8.189 73.278 8.699 ;
     RECT  90.648 8.635 91.242 8.699 ;
     RECT  67.824 8.671 67.842 8.707 ;
     RECT  67.824 8.707 68.31 8.717 ;
     RECT  10.008 8.539 11.337 8.743 ;
     RECT  7.848 8.501 8.01 8.771 ;
     RECT  72.216 8.731 72.234 8.771 ;
     RECT  10.008 8.743 11.502 8.779 ;
     RECT  59.655 0.793 59.937 8.815 ;
     RECT  9.684 8.779 11.502 8.842 ;
     RECT  82.764 8.587 82.782 8.851 ;
     RECT  92.055 6.845 92.337 8.851 ;
     RECT  93.348 8.779 93.366 8.851 ;
     RECT  99.756 7.961 100.494 8.851 ;
     RECT  7.956 8.771 8.01 8.879 ;
     RECT  63.36 7.901 63.486 8.923 ;
     RECT  0.036 8.159 2.106 8.969 ;
     RECT  52.164 8.851 52.182 8.969 ;
     RECT  70.455 7.889 70.794 8.969 ;
     RECT  73.26 8.699 73.278 8.969 ;
     RECT  92.055 8.851 93.366 8.969 ;
     RECT  99.756 8.851 100.566 8.969 ;
     RECT  5.655 8.477 5.937 8.971 ;
     RECT  100.548 8.969 100.566 9.005 ;
     RECT  1.98 8.969 2.106 9.019 ;
     RECT  7.956 8.879 7.974 9.041 ;
     RECT  9.684 8.842 11.538 9.041 ;
     RECT  92.055 8.969 92.337 9.067 ;
     RECT  54.255 0.793 54.537 9.085 ;
     RECT  59.655 8.815 60.282 9.085 ;
     RECT  21.096 7.421 21.114 9.101 ;
     RECT  68.292 8.717 68.31 9.101 ;
     RECT  9.684 9.041 11.394 9.113 ;
     RECT  91.62 9.067 92.337 9.113 ;
     RECT  93.168 8.969 93.366 9.113 ;
     RECT  82.728 8.851 82.782 9.121 ;
     RECT  96.948 8.303 98.622 9.121 ;
     RECT  111.168 8.509 111.186 9.121 ;
     RECT  19.368 9.121 19.386 9.163 ;
     RECT  63.36 8.923 63.63 9.163 ;
     RECT  5.655 8.971 6.39 9.211 ;
     RECT  63.324 9.163 63.63 9.211 ;
     RECT  64.548 7.933 65.337 9.211 ;
     RECT  81.255 7.889 81.537 9.211 ;
     RECT  5.112 9.211 6.39 9.239 ;
     RECT  9.684 9.113 9.702 9.239 ;
     RECT  53.892 9.085 54.537 9.239 ;
     RECT  63.324 9.211 65.337 9.239 ;
     RECT  89.208 9.121 89.226 9.239 ;
     RECT  94.644 8.587 95.778 9.239 ;
     RECT  81.144 9.211 81.537 9.247 ;
     RECT  82.656 9.121 82.782 9.247 ;
     RECT  79.668 9.211 79.686 9.248 ;
     RECT  80.928 9.247 81.537 9.293 ;
     RECT  5.112 9.239 6.174 9.307 ;
     RECT  96.84 9.121 98.622 9.311 ;
     RECT  5.04 9.307 6.174 9.347 ;
     RECT  102.816 8.621 103.338 9.347 ;
     RECT  95.76 9.239 95.778 9.355 ;
     RECT  96.84 9.311 97.737 9.355 ;
     RECT  48.855 0.793 49.137 9.391 ;
     RECT  52.956 9.163 52.974 9.391 ;
     RECT  82.44 9.247 82.782 9.391 ;
     RECT  44.46 8.509 44.478 9.419 ;
     RECT  5.655 9.347 6.174 9.437 ;
     RECT  82.44 9.391 82.962 9.451 ;
     RECT  12.816 9.283 12.834 9.509 ;
     RECT  48.24 9.391 49.137 9.509 ;
     RECT  59.655 9.085 60.714 9.509 ;
     RECT  91.98 9.113 92.337 9.509 ;
     RECT  95.76 9.355 97.737 9.509 ;
     RECT  82.44 9.451 83.25 9.517 ;
     RECT  63.936 9.239 65.337 9.545 ;
     RECT  95.832 9.509 95.958 9.545 ;
     RECT  82.44 9.517 83.322 9.553 ;
     RECT  112.86 8.581 115.506 9.581 ;
     RECT  19.368 9.163 19.602 9.589 ;
     RECT  82.44 9.553 83.862 9.629 ;
     RECT  50.004 9.589 50.022 9.661 ;
     RECT  59.655 9.509 60.21 9.677 ;
     RECT  18.828 9.589 19.746 9.689 ;
     RECT  46.764 9.589 46.782 9.689 ;
     RECT  78.732 9.391 78.75 9.689 ;
     RECT  82.44 9.629 82.674 9.689 ;
     RECT  83.772 9.629 83.862 9.689 ;
     RECT  70.455 8.969 70.737 9.691 ;
     RECT  48.852 9.509 49.137 9.751 ;
     RECT  93.564 9.661 93.582 9.751 ;
     RECT  94.644 9.239 94.914 9.751 ;
     RECT  19.368 9.689 19.674 9.779 ;
     RECT  63.072 9.739 63.09 9.779 ;
     RECT  63.936 9.545 64.206 9.779 ;
     RECT  69.768 9.691 70.83 9.779 ;
     RECT  102.024 9.661 102.042 9.779 ;
     RECT  49.932 9.661 50.022 9.781 ;
     RECT  92.055 9.509 92.337 9.781 ;
     RECT  1.98 9.019 2.502 9.787 ;
     RECT  7.452 9.691 7.47 9.787 ;
     RECT  52.956 9.391 53.19 9.815 ;
     RECT  49.932 9.781 50.49 9.821 ;
     RECT  92.055 9.781 92.61 9.821 ;
     RECT  0.036 8.969 1.026 9.823 ;
     RECT  1.98 9.787 2.862 9.823 ;
     RECT  7.452 9.787 7.542 9.823 ;
     RECT  72.432 9.739 72.45 9.859 ;
     RECT  7.38 9.823 7.542 9.869 ;
     RECT  0.036 9.823 2.862 9.887 ;
     RECT  7.524 9.869 7.542 9.887 ;
     RECT  48.852 9.751 49.158 9.887 ;
     RECT  90.648 8.699 90.702 9.895 ;
     RECT  102.855 9.347 103.338 9.895 ;
     RECT  19.368 9.779 19.386 9.917 ;
     RECT  112.86 9.581 115.434 9.917 ;
     RECT  90.648 9.895 90.738 9.923 ;
     RECT  93.564 9.751 94.914 9.923 ;
     RECT  72.252 9.859 72.45 9.931 ;
     RECT  75.855 8.435 76.137 9.931 ;
     RECT  76.896 8.429 76.914 9.931 ;
     RECT  81.144 9.293 81.537 9.959 ;
     RECT  108.255 0.793 108.537 9.979 ;
     RECT  0.036 9.887 2.502 10.049 ;
     RECT  10.836 9.113 11.394 10.049 ;
     RECT  64.188 9.779 64.206 10.049 ;
     RECT  75.855 9.931 76.914 10.049 ;
     RECT  83.772 9.689 83.79 10.049 ;
     RECT  93.6 9.923 94.914 10.049 ;
     RECT  95.94 9.545 95.958 10.049 ;
     RECT  108.255 9.979 109.062 10.049 ;
     RECT  110.628 9.121 111.186 10.057 ;
     RECT  16.455 5.261 16.737 10.075 ;
     RECT  90.684 9.923 90.738 10.121 ;
     RECT  93.636 10.049 94.914 10.121 ;
     RECT  77.904 9.931 77.922 10.129 ;
     RECT  4.5 10.12 4.518 10.157 ;
     RECT  82.656 9.689 82.674 10.157 ;
     RECT  72.252 9.931 72.918 10.165 ;
     RECT  98.604 9.311 98.622 10.193 ;
     RECT  11.055 10.049 11.394 10.201 ;
     RECT  51.48 9.751 51.498 10.201 ;
     RECT  112.86 9.917 115.398 10.201 ;
     RECT  108.255 10.049 108.954 10.205 ;
     RECT  5.655 9.437 5.937 10.219 ;
     RECT  0.036 10.049 2.358 10.229 ;
     RECT  51.228 10.201 51.498 10.229 ;
     RECT  77.328 10.129 77.922 10.229 ;
     RECT  71.964 10.165 72.918 10.267 ;
     RECT  51.228 10.229 51.426 10.291 ;
     RECT  65.055 9.545 65.337 10.291 ;
     RECT  86.655 8.537 86.937 10.291 ;
     RECT  94.284 10.121 94.914 10.291 ;
     RECT  48.855 9.887 49.158 10.315 ;
     RECT  49.932 9.821 49.95 10.315 ;
     RECT  15.912 10.075 16.737 10.319 ;
     RECT  48.855 10.315 49.95 10.319 ;
     RECT  51.12 10.291 51.426 10.319 ;
     RECT  52.956 9.815 52.974 10.319 ;
     RECT  71.964 10.267 73.134 10.319 ;
     RECT  112.788 10.201 115.398 10.319 ;
     RECT  69.768 9.779 70.794 10.327 ;
     RECT  48.855 10.319 49.698 10.355 ;
     RECT  69.156 10.327 70.794 10.397 ;
     RECT  16.455 10.319 16.737 10.471 ;
     RECT  66.708 10.129 66.726 10.471 ;
     RECT  84.852 10.315 84.87 10.471 ;
     RECT  86.655 10.291 87.246 10.471 ;
     RECT  94.284 10.291 94.95 10.471 ;
     RECT  106.668 9.859 106.686 10.471 ;
     RECT  110.628 10.057 111.258 10.471 ;
     RECT  88.74 10.291 88.758 10.493 ;
     RECT  51.12 10.319 51.318 10.499 ;
     RECT  51.12 10.499 51.246 10.541 ;
     RECT  110.268 10.471 111.258 10.541 ;
     RECT  69.192 10.397 70.794 10.589 ;
     RECT  72.936 10.319 73.134 10.589 ;
     RECT  80.46 10.267 80.478 10.589 ;
     RECT  84.852 10.471 84.942 10.589 ;
     RECT  91.152 10.471 91.17 10.589 ;
     RECT  94.284 10.471 95.526 10.589 ;
     RECT  106.596 10.471 106.686 10.589 ;
     RECT  51.12 10.541 51.138 10.595 ;
     RECT  4.716 10.219 5.937 10.651 ;
     RECT  112.788 10.319 112.914 10.669 ;
     RECT  84.528 10.633 84.546 10.685 ;
     RECT  74.736 9.931 74.754 10.741 ;
     RECT  81.255 9.959 81.537 10.741 ;
     RECT  4.716 10.651 6.39 10.781 ;
     RECT  90.216 10.705 90.234 10.781 ;
     RECT  0.036 10.229 0.63 10.829 ;
     RECT  74.736 10.741 74.862 10.831 ;
     RECT  75.855 10.049 76.137 10.831 ;
     RECT  65.055 10.291 65.466 10.843 ;
     RECT  1.692 10.229 2.358 10.859 ;
     RECT  66.708 10.471 66.87 10.859 ;
     RECT  102.855 9.895 103.626 10.859 ;
     RECT  110.448 10.541 111.258 10.859 ;
     RECT  1.692 10.859 2.25 10.877 ;
     RECT  69.192 10.589 69.21 10.877 ;
     RECT  74.736 10.831 76.137 10.877 ;
     RECT  88.956 10.831 88.974 10.877 ;
     RECT  96.804 9.509 97.737 10.877 ;
     RECT  71.964 10.319 72.198 10.891 ;
     RECT  75.855 10.877 76.137 10.891 ;
     RECT  65.055 10.843 65.934 10.895 ;
     RECT  75.855 10.891 76.41 10.933 ;
     RECT  77.328 10.229 77.418 10.933 ;
     RECT  74.736 10.877 74.862 10.939 ;
     RECT  86.655 10.471 87.714 10.939 ;
     RECT  78.588 10.867 78.606 10.967 ;
     RECT  75.855 10.933 77.418 10.973 ;
     RECT  110.592 10.859 111.258 10.973 ;
     RECT  5.148 10.781 6.39 10.987 ;
     RECT  7.2 10.843 7.218 10.987 ;
     RECT  5.148 10.987 7.218 11.011 ;
     RECT  86.652 10.939 87.714 11.011 ;
     RECT  1.692 10.877 1.71 11.035 ;
     RECT  38.055 5.459 38.337 11.035 ;
     RECT  71.496 10.891 72.198 11.039 ;
     RECT  77.328 10.973 77.418 11.039 ;
     RECT  86.652 11.011 88.182 11.039 ;
     RECT  108.255 10.205 108.537 11.083 ;
     RECT  106.668 10.589 106.686 11.101 ;
     RECT  107.64 11.083 108.537 11.101 ;
     RECT  1.44 11.035 1.71 11.129 ;
     RECT  5.148 11.011 7.434 11.129 ;
     RECT  11.055 10.201 11.682 11.129 ;
     RECT  38.055 11.035 38.97 11.129 ;
     RECT  62.712 9.787 62.73 11.129 ;
     RECT  66.888 10.903 66.906 11.129 ;
     RECT  77.328 11.039 77.382 11.129 ;
     RECT  110.592 10.973 111.186 11.129 ;
     RECT  106.668 11.101 108.537 11.165 ;
     RECT  113.655 10.319 115.398 11.165 ;
     RECT  38.055 11.129 38.337 11.173 ;
     RECT  97.02 10.877 97.737 11.173 ;
     RECT  98.568 11.101 98.586 11.173 ;
     RECT  9 10.891 9.018 11.179 ;
     RECT  27.255 0.793 27.537 11.209 ;
     RECT  94.644 10.589 95.526 11.209 ;
     RECT  112.284 10.669 112.914 11.209 ;
     RECT  113.655 11.165 115.29 11.209 ;
     RECT  37.368 11.173 38.337 11.213 ;
     RECT  32.655 0.793 32.937 11.227 ;
     RECT  86.655 11.039 88.182 11.237 ;
     RECT  73.908 10.843 73.926 11.273 ;
     RECT  75.855 10.973 76.41 11.273 ;
     RECT  86.655 11.237 87.678 11.273 ;
     RECT  97.02 11.173 97.758 11.273 ;
     RECT  98.496 11.173 98.838 11.273 ;
     RECT  7.344 11.129 7.434 11.281 ;
     RECT  21.855 6.809 22.137 11.281 ;
     RECT  88.992 10.939 89.01 11.281 ;
     RECT  107.82 11.165 108.537 11.281 ;
     RECT  5.148 11.129 6.57 11.309 ;
     RECT  26.784 11.209 27.537 11.309 ;
     RECT  59.655 9.677 59.937 11.323 ;
     RECT  7.344 11.281 7.758 11.371 ;
     RECT  8.568 11.179 9.018 11.371 ;
     RECT  1.44 11.129 1.53 11.399 ;
     RECT  21.855 11.281 22.842 11.399 ;
     RECT  32.112 11.227 32.937 11.399 ;
     RECT  71.496 11.039 71.946 11.399 ;
     RECT  74.664 10.939 74.862 11.399 ;
     RECT  77.364 11.129 77.382 11.399 ;
     RECT  88.992 11.281 89.082 11.399 ;
     RECT  94.644 11.209 96.066 11.399 ;
     RECT  98.82 11.273 98.838 11.399 ;
     RECT  106.668 11.165 106.686 11.399 ;
     RECT  107.82 11.281 108.63 11.399 ;
     RECT  32.4 11.399 32.937 11.408 ;
     RECT  16.455 10.471 17.406 11.419 ;
     RECT  84.096 10.843 84.402 11.419 ;
     RECT  58.86 11.323 58.878 11.435 ;
     RECT  59.655 11.323 60.498 11.443 ;
     RECT  110.628 11.129 111.186 11.453 ;
     RECT  7.344 11.371 9.018 11.471 ;
     RECT  70.308 10.589 70.737 11.479 ;
     RECT  98.964 11.407 98.982 11.507 ;
     RECT  110.628 11.453 110.646 11.507 ;
     RECT  58.968 11.443 60.57 11.543 ;
     RECT  112.284 11.209 115.29 11.549 ;
     RECT  80.892 10.741 81.537 11.563 ;
     RECT  59.655 11.543 60.498 11.579 ;
     RECT  66.132 11.011 66.15 11.579 ;
     RECT  70.308 11.479 70.794 11.579 ;
     RECT  71.856 11.399 71.946 11.579 ;
     RECT  90.324 10.903 90.702 11.611 ;
     RECT  92.055 9.821 92.337 11.611 ;
     RECT  52.992 11.551 53.01 11.669 ;
     RECT  78.156 11.563 78.174 11.669 ;
     RECT  80.892 11.563 81.666 11.669 ;
     RECT  89.856 11.611 90.702 11.669 ;
     RECT  97.455 11.273 97.758 11.677 ;
     RECT  3.384 11.371 3.402 11.707 ;
     RECT  16.452 11.419 17.406 11.749 ;
     RECT  90.648 11.669 90.702 11.749 ;
     RECT  3.348 11.707 3.402 11.755 ;
     RECT  97.455 11.677 97.866 11.777 ;
     RECT  16.452 11.749 17.442 11.813 ;
     RECT  79.956 11.755 79.974 11.813 ;
     RECT  54.255 9.239 54.537 11.821 ;
     RECT  95.832 11.399 96.066 11.821 ;
     RECT  82.656 11.281 82.674 11.849 ;
     RECT  0.252 10.829 0.63 11.851 ;
     RECT  8.568 11.471 9.018 11.911 ;
     RECT  75.024 11.821 75.042 11.911 ;
     RECT  75.855 11.273 76.137 11.911 ;
     RECT  91.836 11.611 92.337 11.911 ;
     RECT  5.655 11.309 6.57 11.939 ;
     RECT  7.344 11.471 7.434 11.939 ;
     RECT  8.568 11.911 9.594 11.939 ;
     RECT  14.832 11.749 14.85 11.939 ;
     RECT  16.455 11.813 17.442 11.939 ;
     RECT  37.512 11.213 38.337 11.939 ;
     RECT  45.684 11.749 45.702 11.939 ;
     RECT  81.255 11.669 81.666 11.939 ;
     RECT  84.024 11.419 84.402 11.939 ;
     RECT  0.036 11.851 0.63 11.947 ;
     RECT  11.055 11.129 11.394 11.947 ;
     RECT  113.328 11.549 115.29 11.947 ;
     RECT  94.644 11.399 94.662 11.975 ;
     RECT  95.832 11.821 96.102 11.975 ;
     RECT  113.328 11.947 115.326 11.975 ;
     RECT  75.024 11.911 76.137 11.981 ;
     RECT  81.255 11.939 81.594 11.981 ;
     RECT  8.928 11.939 9.594 12.011 ;
     RECT  88.992 11.399 89.01 12.055 ;
     RECT  2.664 11.755 3.402 12.181 ;
     RECT  8.928 12.011 9.018 12.209 ;
     RECT  70.308 11.579 70.737 12.209 ;
     RECT  0.036 11.947 1.098 12.235 ;
     RECT  2.232 12.181 3.402 12.235 ;
     RECT  28.764 11.281 28.782 12.235 ;
     RECT  2.232 12.235 3.762 12.281 ;
     RECT  8.928 12.209 8.946 12.281 ;
     RECT  54.144 11.821 54.537 12.289 ;
     RECT  95.832 11.975 95.958 12.317 ;
     RECT  69.372 12.235 69.39 12.353 ;
     RECT  94.968 12.283 94.986 12.353 ;
     RECT  27.255 11.309 27.537 12.361 ;
     RECT  90.648 11.749 90.846 12.361 ;
     RECT  91.764 11.911 92.337 12.361 ;
     RECT  107.82 11.399 108.537 12.361 ;
     RECT  110.592 12.181 110.61 12.389 ;
     RECT  0.036 12.235 1.17 12.427 ;
     RECT  2.232 12.281 3.402 12.427 ;
     RECT  48.855 10.355 49.137 12.451 ;
     RECT  53.82 12.289 54.537 12.475 ;
     RECT  0.036 12.427 3.402 12.479 ;
     RECT  28.512 12.235 28.782 12.479 ;
     RECT  66.708 12.289 66.726 12.479 ;
     RECT  70.344 12.209 70.737 12.479 ;
     RECT  74.16 11.995 74.178 12.479 ;
     RECT  90.648 12.361 92.934 12.479 ;
     RECT  112.284 11.549 112.302 12.479 ;
     RECT  75.855 11.981 76.137 12.487 ;
     RECT  87.66 11.273 87.678 12.487 ;
     RECT  88.596 12.055 89.01 12.487 ;
     RECT  48.816 12.451 49.137 12.509 ;
     RECT  26.784 12.361 27.537 12.515 ;
     RECT  29.52 12.361 29.538 12.515 ;
     RECT  53.604 12.475 54.537 12.515 ;
     RECT  107.748 12.361 108.537 12.515 ;
     RECT  50.58 12.427 50.598 12.523 ;
     RECT  0.036 12.479 1.17 12.551 ;
     RECT  83.232 12.487 83.25 12.557 ;
     RECT  78.948 11.821 78.966 12.559 ;
     RECT  84.384 11.939 84.402 12.559 ;
     RECT  86.655 11.273 86.937 12.595 ;
     RECT  87.66 12.487 89.01 12.595 ;
     RECT  69.588 12.361 69.606 12.623 ;
     RECT  11.055 11.947 11.754 12.631 ;
     RECT  50.22 12.523 50.598 12.631 ;
     RECT  86.655 12.595 89.046 12.631 ;
     RECT  78.948 12.559 79.074 12.659 ;
     RECT  50.22 12.631 50.886 12.701 ;
     RECT  84.384 12.559 84.51 12.712 ;
     RECT  0.036 12.551 1.098 12.749 ;
     RECT  37.26 12.712 37.278 12.749 ;
     RECT  54.108 12.515 54.537 12.749 ;
     RECT  71.856 11.579 71.874 12.749 ;
     RECT  86.652 12.631 89.046 12.785 ;
     RECT  94.716 12.721 94.806 12.793 ;
     RECT  101.556 12.721 101.574 12.793 ;
     RECT  102.855 10.859 103.137 12.793 ;
     RECT  84.384 12.712 84.582 12.829 ;
     RECT  94.644 12.793 94.806 12.829 ;
     RECT  95.832 12.317 95.85 12.829 ;
     RECT  110.628 12.793 110.718 12.829 ;
     RECT  78.948 12.659 79.002 12.857 ;
     RECT  5.655 11.939 6.246 12.859 ;
     RECT  38.055 11.939 38.337 12.865 ;
     RECT  70.455 12.479 70.737 12.865 ;
     RECT  74.664 12.559 74.754 12.865 ;
     RECT  75.855 12.487 76.41 12.865 ;
     RECT  84.384 12.829 84.618 12.865 ;
     RECT  0.036 12.749 0.99 12.893 ;
     RECT  50.22 12.701 50.85 12.901 ;
     RECT  74.664 12.865 76.41 12.901 ;
     RECT  78.048 12.859 78.066 12.901 ;
     RECT  78.876 12.865 78.894 12.901 ;
     RECT  28.692 12.479 28.71 12.929 ;
     RECT  46.764 12.829 46.782 12.929 ;
     RECT  78.048 12.901 78.894 12.929 ;
     RECT  90.648 12.479 91.098 12.929 ;
     RECT  91.98 12.479 92.934 12.929 ;
     RECT  93.96 12.829 94.806 12.929 ;
     RECT  102.528 12.793 103.137 12.929 ;
     RECT  70.455 12.865 71.658 12.941 ;
     RECT  10.98 12.631 11.754 13.003 ;
     RECT  0.036 12.893 0.738 13.019 ;
     RECT  10.764 13.003 11.754 13.019 ;
     RECT  20.592 12.523 20.61 13.019 ;
     RECT  71.568 12.941 71.658 13.019 ;
     RECT  78.228 12.929 78.894 13.019 ;
     RECT  82.656 12.829 82.674 13.019 ;
     RECT  110.628 12.829 111.186 13.027 ;
     RECT  86.652 12.785 88.866 13.051 ;
     RECT  10.764 13.019 11.502 13.055 ;
     RECT  78.3 13.019 78.894 13.055 ;
     RECT  95.724 12.829 95.85 13.055 ;
     RECT  100.872 12.793 101.574 13.055 ;
     RECT  67.284 12.901 67.374 13.063 ;
     RECT  97.455 11.777 97.794 13.063 ;
     RECT  98.604 12.721 98.694 13.063 ;
     RECT  67.284 13.063 67.626 13.085 ;
     RECT  74.664 12.901 77.13 13.085 ;
     RECT  2.232 12.479 3.402 13.091 ;
     RECT  75.636 13.085 77.13 13.091 ;
     RECT  78.3 13.055 78.75 13.091 ;
     RECT  86.544 13.051 88.866 13.091 ;
     RECT  94.644 12.929 94.806 13.091 ;
     RECT  101.448 13.055 101.538 13.091 ;
     RECT  48.855 12.509 49.137 13.099 ;
     RECT  81.255 11.981 81.537 13.099 ;
     RECT  50.184 12.901 50.85 13.127 ;
     RECT  83.772 12.865 84.618 13.127 ;
     RECT  97.455 13.063 98.694 13.163 ;
     RECT  81.255 13.099 81.882 13.243 ;
     RECT  71.568 13.019 71.586 13.289 ;
     RECT  75.636 13.091 76.626 13.289 ;
     RECT  81.072 13.243 81.882 13.289 ;
     RECT  83.952 13.127 84.618 13.289 ;
     RECT  91.98 12.929 92.337 13.289 ;
     RECT  110.628 13.027 111.762 13.289 ;
     RECT  50.22 13.127 50.85 13.325 ;
     RECT  98.604 13.163 98.694 13.333 ;
     RECT  110.628 13.289 111.186 13.333 ;
     RECT  48.855 13.099 49.302 13.369 ;
     RECT  85.644 13.333 85.662 13.369 ;
     RECT  110.592 13.333 111.186 13.373 ;
     RECT  45.612 11.947 45.63 13.397 ;
     RECT  91.08 12.929 91.098 13.405 ;
     RECT  113.655 11.975 115.326 13.405 ;
     RECT  85.572 13.369 85.662 13.433 ;
     RECT  20.844 13.063 20.862 13.441 ;
     RECT  73.152 13.369 73.17 13.441 ;
     RECT  84.06 13.289 84.618 13.441 ;
     RECT  85.572 13.433 85.59 13.441 ;
     RECT  5.655 12.859 6.282 13.469 ;
     RECT  23.328 12.811 23.346 13.469 ;
     RECT  37.44 12.865 38.337 13.469 ;
     RECT  73.08 13.441 73.17 13.469 ;
     RECT  84.06 13.441 85.59 13.469 ;
     RECT  18.252 13.099 18.27 13.531 ;
     RECT  96.048 13.483 96.066 13.531 ;
     RECT  9.612 13.441 9.63 13.559 ;
     RECT  18.252 13.531 18.846 13.559 ;
     RECT  24.12 13.405 24.138 13.559 ;
     RECT  47.196 13.405 47.394 13.559 ;
     RECT  48.132 13.369 49.302 13.559 ;
     RECT  50.22 13.325 50.238 13.559 ;
     RECT  67.32 13.085 67.626 13.559 ;
     RECT  86.655 13.091 88.866 13.559 ;
     RECT  91.08 13.405 91.17 13.559 ;
     RECT  96.048 13.531 96.138 13.559 ;
     RECT  98.604 13.333 98.838 13.559 ;
     RECT  84.06 13.469 85.518 13.565 ;
     RECT  84.06 13.565 85.05 13.595 ;
     RECT  97.455 13.163 97.794 13.595 ;
     RECT  110.592 13.373 110.718 13.595 ;
     RECT  47.196 13.559 47.214 13.613 ;
     RECT  48.855 13.559 49.302 13.613 ;
     RECT  67.32 13.559 67.338 13.613 ;
     RECT  84.492 13.595 85.05 13.631 ;
     RECT  94.644 13.091 94.662 13.631 ;
     RECT  18.576 13.559 18.846 13.639 ;
     RECT  86.655 13.559 87.858 13.661 ;
     RECT  96.12 13.559 96.138 13.661 ;
     RECT  98.604 13.559 98.802 13.703 ;
     RECT  58.284 13.723 58.302 13.829 ;
     RECT  73.08 13.469 73.098 13.829 ;
     RECT  81.216 13.289 81.702 13.829 ;
     RECT  86.655 13.661 87.822 13.829 ;
     RECT  90.72 13.675 90.738 13.837 ;
     RECT  2.304 13.091 3.402 13.867 ;
     RECT  82.836 13.441 82.926 13.873 ;
     RECT  13.788 13.801 13.806 13.901 ;
     RECT  2.304 13.867 3.51 13.909 ;
     RECT  82.764 13.873 82.926 13.909 ;
     RECT  112.86 12.865 112.878 13.909 ;
     RECT  113.655 13.405 115.398 13.909 ;
     RECT  88.812 13.559 88.866 13.937 ;
     RECT  90.648 13.837 90.738 13.937 ;
     RECT  82.728 13.909 82.926 13.945 ;
     RECT  89.604 13.873 89.622 13.945 ;
     RECT  2.016 13.909 3.51 13.949 ;
     RECT  20.844 13.441 21.078 13.981 ;
     RECT  70.455 12.941 70.758 13.981 ;
     RECT  112.86 13.909 115.398 14.045 ;
     RECT  20.412 13.981 21.078 14.059 ;
     RECT  21.855 11.399 22.137 14.059 ;
     RECT  54.255 12.749 54.537 14.059 ;
     RECT  82.656 13.945 82.926 14.071 ;
     RECT  3.276 13.949 3.51 14.099 ;
     RECT  54 14.059 54.537 14.099 ;
     RECT  75.636 13.289 76.59 14.099 ;
     RECT  86.655 13.829 87.426 14.099 ;
     RECT  89.46 13.945 89.622 14.099 ;
     RECT  98.604 13.703 98.622 14.099 ;
     RECT  84.492 13.631 84.618 14.135 ;
     RECT  89.532 14.099 89.622 14.135 ;
     RECT  2.016 13.949 2.322 14.143 ;
     RECT  112.86 14.045 115.29 14.143 ;
     RECT  78.66 13.091 78.75 14.171 ;
     RECT  82.656 14.071 83.214 14.171 ;
     RECT  54.255 14.099 54.537 14.215 ;
     RECT  72.036 13.981 72.054 14.237 ;
     RECT  75.636 14.099 76.137 14.237 ;
     RECT  112.248 14.143 115.29 14.237 ;
     RECT  90.684 13.937 90.702 14.243 ;
     RECT  1.728 14.143 2.322 14.251 ;
     RECT  70.455 13.981 71.226 14.251 ;
     RECT  3.384 14.099 3.51 14.299 ;
     RECT  32.655 11.408 32.937 14.341 ;
     RECT  18.576 13.639 19.422 14.369 ;
     RECT  58.392 13.981 58.914 14.369 ;
     RECT  77.076 14.251 77.094 14.369 ;
     RECT  96.552 14.251 96.57 14.369 ;
     RECT  104.58 13.135 104.598 14.369 ;
     RECT  113.292 14.237 115.29 14.369 ;
     RECT  0.036 13.019 0.63 14.377 ;
     RECT  58.392 14.369 58.626 14.441 ;
     RECT  70.455 14.251 71.91 14.441 ;
     RECT  0.036 14.377 0.666 14.449 ;
     RECT  94.716 14.299 94.734 14.449 ;
     RECT  32.655 14.341 33.606 14.477 ;
     RECT  0.036 14.449 0.702 14.485 ;
     RECT  1.476 14.251 2.322 14.485 ;
     RECT  96.048 14.449 96.066 14.485 ;
     RECT  18.576 14.369 18.882 14.513 ;
     RECT  77.868 14.449 77.886 14.521 ;
     RECT  66.708 14.449 66.726 14.549 ;
     RECT  70.455 14.441 71.802 14.549 ;
     RECT  74.664 13.085 74.682 14.549 ;
     RECT  77.796 14.521 77.886 14.549 ;
     RECT  94.644 14.449 94.734 14.611 ;
     RECT  81.255 13.829 81.666 14.635 ;
     RECT  11.055 13.055 11.502 14.639 ;
     RECT  14.832 14.449 14.85 14.639 ;
     RECT  20.34 14.059 22.137 14.639 ;
     RECT  30.78 14.521 30.798 14.639 ;
     RECT  34.668 14.521 34.758 14.639 ;
     RECT  73.332 14.251 73.35 14.639 ;
     RECT  82.836 14.171 83.214 14.639 ;
     RECT  93.744 14.521 93.834 14.639 ;
     RECT  3.384 14.299 3.942 14.647 ;
     RECT  86.655 14.099 86.937 14.647 ;
     RECT  21.096 14.639 22.137 14.669 ;
     RECT  70.455 14.549 71.766 14.675 ;
     RECT  27.255 12.515 27.537 14.683 ;
     RECT  95.976 14.485 96.066 14.683 ;
     RECT  110.592 13.595 110.646 14.683 ;
     RECT  21.096 14.669 21.114 14.711 ;
     RECT  94.644 14.611 94.842 14.711 ;
     RECT  3.384 14.647 4.014 14.717 ;
     RECT  26.424 14.683 27.537 14.747 ;
     RECT  88.416 14.719 88.434 14.765 ;
     RECT  95.904 14.683 96.066 14.783 ;
     RECT  110.592 14.683 111.258 14.783 ;
     RECT  81.255 14.635 81.918 14.791 ;
     RECT  84.636 14.485 85.266 14.813 ;
     RECT  3.384 14.717 3.402 14.819 ;
     RECT  6.84 14.647 6.858 14.819 ;
     RECT  20.34 14.639 20.358 14.819 ;
     RECT  71.748 14.675 71.766 14.819 ;
     RECT  74.808 14.719 74.898 14.819 ;
     RECT  82.836 14.639 82.854 14.819 ;
     RECT  85.176 14.813 85.266 14.819 ;
     RECT  93.816 14.639 93.834 14.819 ;
     RECT  94.644 14.711 94.734 14.819 ;
     RECT  77.796 14.549 77.814 14.909 ;
     RECT  81.255 14.791 82.098 14.909 ;
     RECT  112.248 14.237 112.302 15.005 ;
     RECT  100.872 14.719 100.89 15.061 ;
     RECT  101.844 14.485 101.862 15.061 ;
     RECT  94.644 14.819 94.662 15.115 ;
     RECT  18.576 14.513 18.846 15.179 ;
     RECT  54.255 14.215 55.17 15.179 ;
     RECT  73.872 15.061 74.07 15.179 ;
     RECT  74.808 14.819 74.862 15.179 ;
     RECT  82.44 14.989 82.746 15.179 ;
     RECT  88.704 14.875 88.758 15.179 ;
     RECT  99.828 14.413 99.846 15.179 ;
     RECT  100.764 15.061 101.862 15.179 ;
     RECT  113.328 14.369 115.29 15.179 ;
     RECT  54.255 15.179 54.537 15.187 ;
     RECT  102.855 12.929 103.137 15.187 ;
     RECT  0.036 14.485 2.322 15.211 ;
     RECT  0.036 15.211 2.358 15.215 ;
     RECT  54.216 15.187 54.537 15.245 ;
     RECT  84.42 15.151 84.438 15.245 ;
     RECT  26.64 14.747 27.537 15.251 ;
     RECT  86.652 14.647 86.937 15.259 ;
     RECT  89.64 14.647 89.73 15.259 ;
     RECT  74.844 15.179 74.862 15.287 ;
     RECT  81.255 14.909 81.702 15.287 ;
     RECT  110.592 14.783 111.186 15.293 ;
     RECT  113.655 15.179 115.29 15.295 ;
     RECT  18.792 15.179 18.846 15.331 ;
     RECT  86.04 15.259 86.937 15.331 ;
     RECT  94.14 15.115 94.662 15.341 ;
     RECT  58.608 14.441 58.626 15.359 ;
     RECT  82.728 15.179 82.746 15.359 ;
     RECT  110.592 15.293 110.682 15.359 ;
     RECT  5.655 13.469 5.937 15.421 ;
     RECT  34.668 14.639 34.686 15.421 ;
     RECT  81.255 15.287 81.537 15.421 ;
     RECT  89.64 15.259 90.234 15.421 ;
     RECT  14.04 13.981 14.058 15.449 ;
     RECT  15.228 15.403 15.246 15.449 ;
     RECT  33.948 15.421 34.686 15.449 ;
     RECT  43.455 7.373 43.737 15.457 ;
     RECT  95.904 14.783 95.922 15.457 ;
     RECT  78.66 14.171 78.678 15.529 ;
     RECT  98.928 15.403 98.946 15.529 ;
     RECT  0.216 15.215 2.358 15.557 ;
     RECT  18.792 15.331 19.422 15.557 ;
     RECT  42.768 15.457 43.737 15.557 ;
     RECT  33.948 15.449 33.966 15.565 ;
     RECT  88.704 15.179 88.722 15.593 ;
     RECT  78.66 15.529 78.75 15.595 ;
     RECT  94.464 15.341 94.662 15.601 ;
     RECT  95.868 15.457 95.922 15.601 ;
     RECT  33.732 15.565 33.966 15.629 ;
     RECT  42.84 15.557 43.737 15.629 ;
     RECT  70.455 14.675 71.01 15.629 ;
     RECT  78.264 15.595 78.75 15.629 ;
     RECT  33.948 15.629 33.966 15.677 ;
     RECT  30.78 15.529 30.798 15.719 ;
     RECT  34.704 15.529 34.722 15.719 ;
     RECT  78.264 15.629 78.678 15.719 ;
     RECT  95.796 15.601 95.922 15.719 ;
     RECT  96.66 15.529 96.678 15.719 ;
     RECT  94.464 15.601 94.734 15.727 ;
     RECT  80.748 15.421 81.537 15.763 ;
     RECT  98.604 15.529 99.306 15.763 ;
     RECT  94.464 15.727 94.986 15.773 ;
     RECT  95.796 15.719 95.85 15.791 ;
     RECT  112.284 15.005 112.302 15.799 ;
     RECT  112.284 15.799 112.878 15.835 ;
     RECT  6.84 15.691 6.858 15.871 ;
     RECT  97.455 13.595 97.737 15.871 ;
     RECT  100.872 15.179 101.862 15.899 ;
     RECT  110.592 15.359 110.646 15.899 ;
     RECT  6.84 15.871 7.182 15.917 ;
     RECT  10.296 14.755 10.314 15.961 ;
     RECT  11.055 14.639 11.337 15.961 ;
     RECT  85.176 14.819 85.194 15.961 ;
     RECT  85.968 15.331 86.937 15.961 ;
     RECT  89.496 15.421 90.234 15.961 ;
     RECT  96.912 15.871 97.737 15.961 ;
     RECT  98.568 15.763 99.306 15.961 ;
     RECT  101.448 15.899 101.862 15.961 ;
     RECT  102.672 15.187 103.137 15.961 ;
     RECT  0.255 15.557 2.358 15.989 ;
     RECT  10.296 15.961 11.337 15.989 ;
     RECT  19.404 15.557 19.422 15.989 ;
     RECT  76.968 15.025 76.986 15.989 ;
     RECT  96.912 15.961 99.306 15.989 ;
     RECT  85.176 15.961 86.994 15.997 ;
     RECT  18.468 15.961 18.486 16.013 ;
     RECT  93.492 15.961 93.51 16.013 ;
     RECT  101.448 15.961 103.137 16.025 ;
     RECT  85.176 15.997 87.21 16.027 ;
     RECT  111.744 15.835 112.878 16.033 ;
     RECT  113.655 15.295 115.398 16.033 ;
     RECT  111.744 16.033 115.398 16.061 ;
     RECT  89.496 15.961 90.27 16.069 ;
     RECT  94.464 15.773 94.734 16.069 ;
     RECT  84.96 16.027 87.21 16.097 ;
     RECT  111.744 16.061 112.302 16.097 ;
     RECT  10.728 15.989 11.337 16.157 ;
     RECT  113.436 16.061 115.398 16.157 ;
     RECT  19.44 16.069 19.458 16.169 ;
     RECT  101.448 16.025 101.538 16.169 ;
     RECT  85.032 16.097 87.21 16.219 ;
     RECT  85.032 16.219 87.246 16.231 ;
     RECT  0.255 15.989 2.322 16.259 ;
     RECT  101.52 16.169 101.538 16.259 ;
     RECT  85.032 16.231 87.318 16.331 ;
     RECT  110.592 15.899 110.61 16.331 ;
     RECT  89.496 16.069 90.738 16.405 ;
     RECT  75.855 14.237 76.137 16.411 ;
     RECT  85.212 16.331 87.318 16.411 ;
     RECT  85.212 16.411 87.678 16.439 ;
     RECT  89.208 16.405 90.738 16.445 ;
     RECT  8.28 16.141 8.406 16.501 ;
     RECT  62.28 16.411 62.298 16.501 ;
     RECT  5.655 15.421 5.994 16.529 ;
     RECT  62.28 16.501 62.406 16.529 ;
     RECT  73.008 16.075 73.026 16.529 ;
     RECT  85.716 16.439 85.806 16.529 ;
     RECT  89.676 16.445 90.738 16.529 ;
     RECT  97.455 15.989 99.306 16.529 ;
     RECT  98.604 16.529 99.306 16.537 ;
     RECT  62.388 16.529 62.406 16.541 ;
     RECT  75.855 16.411 76.662 16.541 ;
     RECT  93.708 16.069 94.734 16.541 ;
     RECT  5.655 16.529 5.937 16.555 ;
     RECT  7.956 16.501 8.406 16.555 ;
     RECT  82.656 16.105 82.674 16.555 ;
     RECT  95.796 15.791 95.814 16.573 ;
     RECT  0.255 16.259 1.854 16.589 ;
     RECT  85.716 16.529 85.734 16.589 ;
     RECT  86.616 16.439 87.678 16.589 ;
     RECT  98.604 16.537 99.846 16.6 ;
     RECT  104.76 16.555 104.778 16.6 ;
     RECT  4.536 16.411 4.626 16.601 ;
     RECT  43.455 15.629 43.737 16.603 ;
     RECT  44.532 15.601 44.55 16.603 ;
     RECT  74.304 16.231 74.322 16.609 ;
     RECT  75.096 15.961 75.114 16.609 ;
     RECT  75.855 16.541 76.338 16.609 ;
     RECT  79.236 16.555 79.254 16.609 ;
     RECT  90.036 16.529 90.738 16.609 ;
     RECT  98.604 16.6 99.918 16.637 ;
     RECT  104.76 16.6 104.958 16.637 ;
     RECT  113.436 16.157 115.254 16.637 ;
     RECT  98.604 16.637 99.774 16.643 ;
     RECT  74.304 16.609 76.338 16.709 ;
     RECT  95.796 16.573 96.426 16.709 ;
     RECT  104.76 16.637 104.922 16.771 ;
     RECT  94.644 16.541 94.734 16.795 ;
     RECT  5.58 16.555 5.937 16.799 ;
     RECT  7.74 16.555 8.406 16.799 ;
     RECT  43.455 16.603 44.55 16.799 ;
     RECT  90.036 16.609 90.774 16.799 ;
     RECT  95.796 16.709 96.354 16.799 ;
     RECT  111.816 16.097 112.302 16.799 ;
     RECT  78.804 16.609 79.254 16.807 ;
     RECT  82.656 16.555 83.25 16.807 ;
     RECT  102.6 16.025 103.137 16.807 ;
     RECT  104.04 16.771 104.922 16.807 ;
     RECT  80.172 15.763 81.537 16.829 ;
     RECT  90.036 16.799 90.738 16.835 ;
     RECT  94.644 16.795 94.878 16.835 ;
     RECT  111.816 16.799 111.834 16.843 ;
     RECT  7.956 16.799 8.406 16.871 ;
     RECT  10.944 16.157 11.337 16.871 ;
     RECT  111.744 16.843 111.834 16.871 ;
     RECT  74.304 16.709 74.322 16.879 ;
     RECT  82.656 16.807 83.43 16.879 ;
     RECT  113.472 16.637 115.254 16.879 ;
     RECT  75.168 16.709 76.338 16.907 ;
     RECT  78.732 16.807 79.254 16.907 ;
     RECT  82.656 16.879 83.826 16.907 ;
     RECT  98.676 16.643 99.774 16.943 ;
     RECT  82.656 16.907 82.962 16.951 ;
     RECT  83.808 16.907 83.826 16.951 ;
     RECT  92.055 13.289 92.337 16.951 ;
     RECT  86.616 16.589 86.937 16.979 ;
     RECT  102.6 16.807 104.922 17.021 ;
     RECT  0.255 16.589 1.746 17.069 ;
     RECT  73.116 16.681 73.386 17.069 ;
     RECT  75.384 16.907 76.338 17.069 ;
     RECT  83.808 16.951 83.898 17.069 ;
     RECT  87.66 16.589 87.678 17.069 ;
     RECT  90.036 16.835 90.666 17.069 ;
     RECT  92.055 16.951 92.97 17.069 ;
     RECT  93.708 16.541 93.726 17.069 ;
     RECT  96.336 16.799 96.354 17.069 ;
     RECT  98.82 16.943 99.774 17.069 ;
     RECT  104.04 17.021 104.922 17.069 ;
     RECT  75.384 17.069 76.137 17.075 ;
     RECT  92.055 17.069 92.79 17.075 ;
     RECT  98.82 17.069 99.198 17.075 ;
     RECT  74.124 16.879 74.322 17.105 ;
     RECT  90.36 17.069 90.666 17.105 ;
     RECT  102.6 17.021 103.137 17.105 ;
     RECT  104.22 17.069 104.922 17.105 ;
     RECT  3.78 17.083 3.798 17.113 ;
     RECT  2.664 16.951 2.862 17.117 ;
     RECT  79.2 16.907 79.254 17.117 ;
     RECT  82.584 16.951 82.962 17.117 ;
     RECT  111.744 16.871 111.762 17.117 ;
     RECT  4.608 16.601 4.626 17.141 ;
     RECT  104.22 17.105 104.238 17.213 ;
     RECT  62.676 17.131 62.694 17.221 ;
     RECT  63.612 16.411 63.63 17.221 ;
     RECT  87.696 17.149 87.714 17.221 ;
     RECT  90.576 17.105 90.666 17.249 ;
     RECT  81.255 16.829 81.537 17.275 ;
     RECT  80.172 16.829 80.478 17.323 ;
     RECT  8.568 17.083 8.658 17.339 ;
     RECT  62.676 17.221 63.63 17.339 ;
     RECT  74.304 17.105 74.322 17.339 ;
     RECT  79.524 17.323 80.478 17.339 ;
     RECT  81.255 17.275 81.774 17.339 ;
     RECT  82.584 17.117 82.818 17.339 ;
     RECT  87.696 17.221 87.75 17.339 ;
     RECT  99.18 17.075 99.198 17.339 ;
     RECT  108.255 12.515 108.537 17.347 ;
     RECT  62.676 17.339 62.694 17.375 ;
     RECT  79.524 17.339 79.758 17.375 ;
     RECT  82.728 17.339 82.782 17.483 ;
     RECT  3.708 17.113 3.798 17.609 ;
     RECT  79.74 17.375 79.758 17.609 ;
     RECT  82.764 17.483 82.782 17.609 ;
     RECT  87.732 17.339 87.75 17.609 ;
     RECT  94.644 16.835 94.842 17.609 ;
     RECT  113.472 16.879 115.398 17.617 ;
     RECT  90.648 17.249 90.666 17.645 ;
     RECT  94.824 17.609 94.842 17.645 ;
     RECT  110.592 17.491 110.61 17.681 ;
     RECT  2.844 17.117 2.862 17.717 ;
     RECT  1.98 17.659 2.07 17.879 ;
     RECT  112.86 17.617 115.398 17.885 ;
     RECT  112.86 17.885 115.254 17.981 ;
     RECT  113.508 17.981 115.254 18.149 ;
     RECT  102.672 17.105 103.137 18.173 ;
     RECT  113.655 18.149 115.254 18.269 ;
     RECT  0.255 17.069 0.537 18.377 ;
     RECT  5.655 16.799 5.937 18.377 ;
     RECT  11.055 16.871 11.337 18.377 ;
     RECT  16.455 11.939 16.737 18.377 ;
     RECT  21.855 14.669 22.137 18.377 ;
     RECT  27.255 15.251 27.537 18.377 ;
     RECT  32.655 14.477 32.937 18.377 ;
     RECT  38.055 13.469 38.337 18.377 ;
     RECT  43.455 16.799 43.737 18.377 ;
     RECT  48.855 13.613 49.137 18.377 ;
     RECT  54.255 15.245 54.537 18.377 ;
     RECT  59.655 11.579 59.937 18.377 ;
     RECT  65.055 10.895 65.337 18.377 ;
     RECT  70.455 15.629 70.737 18.377 ;
     RECT  75.855 17.075 76.137 18.377 ;
     RECT  81.255 17.339 81.537 18.377 ;
     RECT  86.655 16.979 86.937 18.377 ;
     RECT  92.055 17.075 92.337 18.377 ;
     RECT  97.455 16.529 97.737 18.377 ;
     RECT  102.855 18.173 103.137 18.377 ;
     RECT  113.655 18.269 115.182 18.377 ;
     RECT  107.748 17.347 108.537 18.419 ;
     RECT  113.847 18.377 115.182 18.461 ;
     RECT  0.447 18.377 0.537 18.647 ;
     RECT  5.847 18.377 5.937 18.647 ;
     RECT  11.247 18.377 11.337 18.647 ;
     RECT  16.647 18.377 16.737 18.647 ;
     RECT  22.047 18.377 22.137 18.647 ;
     RECT  27.447 18.377 27.537 18.647 ;
     RECT  32.847 18.377 32.937 18.647 ;
     RECT  38.247 18.377 38.337 18.647 ;
     RECT  43.647 18.377 43.737 18.647 ;
     RECT  49.047 18.377 49.137 18.647 ;
     RECT  54.447 18.377 54.537 18.647 ;
     RECT  59.847 18.377 59.937 18.647 ;
     RECT  65.247 18.377 65.337 18.647 ;
     RECT  70.647 18.377 70.737 18.647 ;
     RECT  76.047 18.377 76.137 18.647 ;
     RECT  81.447 18.377 81.537 18.647 ;
     RECT  86.847 18.377 86.937 18.647 ;
     RECT  92.247 18.377 92.337 18.647 ;
     RECT  97.647 18.377 97.737 18.647 ;
     RECT  103.047 18.377 103.137 18.647 ;
     RECT  108.447 18.419 108.537 18.647 ;
     RECT  113.847 18.461 114.642 18.647 ;
     RECT  114.624 18.647 114.642 18.653 ;
    LAYER M4 ;
     RECT  0.025 3.792 0.092 5.448 ;
     RECT  0.025 6.48 0.092 6.504 ;
     RECT  0.092 3.792 0.133 6.504 ;
     RECT  0.133 3.408 0.156 6.504 ;
     RECT  0.025 7.536 0.156 10.824 ;
     RECT  0.025 11.856 0.156 15.144 ;
     RECT  0.156 3.408 0.248 15.816 ;
     RECT  0.248 0.528 0.352 18.372 ;
     RECT  0.352 0.798 0.44 18.372 ;
     RECT  0.44 0.798 0.544 18.642 ;
     RECT  0.544 3.648 0.659 16.776 ;
     RECT  0.659 3.648 0.893 16.584 ;
     RECT  0.893 3.696 1.645 16.584 ;
     RECT  1.645 3.696 1.765 17.016 ;
     RECT  1.765 3.696 2.081 17.688 ;
     RECT  2.081 3.696 2.305 17.112 ;
     RECT  2.305 3.696 2.369 15.24 ;
     RECT  2.369 3.696 2.873 14.712 ;
     RECT  2.873 4.944 3.779 14.712 ;
     RECT  2.305 17.088 3.809 17.112 ;
     RECT  3.779 12.528 4.025 14.712 ;
     RECT  2.873 3.696 5.648 3.72 ;
     RECT  3.779 4.944 5.648 11.496 ;
     RECT  4.025 12.528 5.648 14.184 ;
     RECT  5.569 16.56 5.648 16.584 ;
     RECT  5.648 0.528 5.752 18.372 ;
     RECT  5.752 0.798 5.84 18.372 ;
     RECT  5.84 0.798 5.944 18.642 ;
     RECT  5.944 15.456 6.083 16.584 ;
     RECT  5.944 6.096 6.401 11.544 ;
     RECT  6.401 6.096 6.869 8.472 ;
     RECT  6.401 9.552 7.333 11.544 ;
     RECT  5.944 12.528 7.333 14.184 ;
     RECT  7.333 9.552 7.427 14.184 ;
     RECT  6.083 15.888 7.429 16.008 ;
     RECT  7.429 15.888 7.475 16.584 ;
     RECT  7.427 9.552 7.489 11.448 ;
     RECT  6.869 6.576 8.057 8.472 ;
     RECT  7.475 16.176 8.533 16.584 ;
     RECT  8.533 16.176 8.557 17.112 ;
     RECT  8.557 16.176 8.579 17.16 ;
     RECT  8.057 6.576 8.593 8.328 ;
     RECT  7.489 9.552 8.597 11.208 ;
     RECT  8.579 17.088 8.669 17.16 ;
     RECT  8.593 6.336 8.771 8.328 ;
     RECT  7.427 12.528 8.917 14.184 ;
     RECT  8.597 9.552 9.029 10.92 ;
     RECT  8.771 6.336 9.107 7.464 ;
     RECT  8.917 12.24 9.107 14.184 ;
     RECT  8.669 17.136 9.107 17.16 ;
     RECT  5.944 3.696 9.173 3.72 ;
     RECT  9.685 8.544 9.997 8.568 ;
     RECT  9.997 8.496 10.076 8.568 ;
     RECT  9.029 9.552 10.076 10.104 ;
     RECT  9.107 6.576 10.261 7.464 ;
     RECT  10.076 8.496 10.261 10.104 ;
     RECT  9.107 12.528 10.933 14.184 ;
     RECT  5.944 4.944 11.048 4.968 ;
     RECT  10.261 6.576 11.048 10.104 ;
     RECT  10.933 12.528 11.048 14.664 ;
     RECT  10.693 16.128 11.048 16.152 ;
     RECT  11.048 0.528 11.152 18.372 ;
     RECT  11.152 0.798 11.24 18.372 ;
     RECT  11.24 0.798 11.344 18.642 ;
     RECT  11.344 10.08 11.459 11.016 ;
     RECT  11.344 5.472 11.644 5.496 ;
     RECT  11.344 6.576 11.644 7.704 ;
     RECT  11.644 6.816 12.035 7.704 ;
     RECT  11.344 12.528 13.817 14.184 ;
     RECT  12.035 6.912 13.909 7.704 ;
     RECT  13.909 6.912 13.996 8.424 ;
     RECT  15.173 15.408 15.257 15.432 ;
     RECT  13.996 6.912 16.309 7.464 ;
     RECT  16.309 6.816 16.448 7.464 ;
     RECT  11.459 10.08 16.448 10.104 ;
     RECT  16.309 11.424 16.448 11.448 ;
     RECT  13.817 12.528 16.448 13.128 ;
     RECT  13.817 14.16 16.448 14.184 ;
     RECT  16.448 0.528 16.552 18.372 ;
     RECT  16.552 0.798 16.64 18.372 ;
     RECT  16.64 0.798 16.744 18.642 ;
     RECT  16.744 6.672 16.883 7.464 ;
     RECT  16.883 6.816 16.979 7.464 ;
     RECT  16.744 12.528 18.281 13.128 ;
     RECT  18.457 15.984 18.541 16.008 ;
     RECT  16.744 14.16 18.605 14.184 ;
     RECT  18.853 14.4 18.947 14.424 ;
     RECT  18.901 9.888 19.333 9.912 ;
     RECT  19.333 9.216 19.397 9.912 ;
     RECT  19.397 9.216 19.42 9.672 ;
     RECT  19.42 9.216 19.532 9.24 ;
     RECT  19.532 9.168 19.619 9.24 ;
     RECT  19.619 9.216 20.003 9.24 ;
     RECT  20.3 14.064 20.386 14.088 ;
     RECT  20.386 14.016 20.387 14.088 ;
     RECT  20.387 14.016 20.531 14.04 ;
     RECT  18.281 12.528 20.621 12.84 ;
     RECT  20.621 12.816 21.637 12.84 ;
     RECT  21.637 14.64 21.692 14.664 ;
     RECT  16.979 6.912 21.848 7.464 ;
     RECT  21.085 9.072 21.848 9.096 ;
     RECT  21.637 12.336 21.848 12.84 ;
     RECT  21.692 14.064 21.848 14.664 ;
     RECT  21.848 0.528 21.952 18.372 ;
     RECT  21.952 0.798 22.04 18.372 ;
     RECT  22.04 0.798 22.144 18.642 ;
     RECT  22.144 12.144 23.357 12.84 ;
     RECT  23.357 12.144 26.629 12.168 ;
     RECT  22.144 6.912 27.248 7.464 ;
     RECT  26.629 12.048 27.248 12.168 ;
     RECT  26.389 14.688 27.248 14.712 ;
     RECT  27.248 0.528 27.352 18.372 ;
     RECT  27.352 0.798 27.44 18.372 ;
     RECT  27.44 0.798 27.544 18.642 ;
     RECT  27.544 12.048 28.585 12.264 ;
     RECT  28.585 12.048 28.643 12.072 ;
     RECT  32.101 11.232 32.389 11.256 ;
     RECT  27.544 6.912 32.648 7.464 ;
     RECT  32.389 11.232 32.648 11.4 ;
     RECT  32.648 0.528 32.752 18.372 ;
     RECT  32.752 0.798 32.84 18.372 ;
     RECT  32.84 0.798 32.944 18.642 ;
     RECT  32.944 15.6 33.761 15.624 ;
     RECT  33.937 15.648 34.211 15.672 ;
     RECT  32.944 6.912 38.048 7.464 ;
     RECT  37.237 11.184 38.048 11.208 ;
     RECT  37.249 12.72 38.048 12.744 ;
     RECT  38.048 0.528 38.152 18.372 ;
     RECT  38.152 0.798 38.24 18.372 ;
     RECT  38.24 0.798 38.344 18.642 ;
     RECT  38.344 11.04 39.347 11.064 ;
     RECT  38.344 6.912 39.517 7.464 ;
     RECT  39.517 6.864 39.923 7.464 ;
     RECT  39.923 6.912 42.613 7.464 ;
     RECT  42.613 6.864 43.448 7.464 ;
     RECT  43.448 0.528 43.552 18.372 ;
     RECT  43.552 0.798 43.64 18.372 ;
     RECT  43.64 0.798 43.744 18.642 ;
     RECT  43.744 6.864 43.955 7.464 ;
     RECT  43.744 16.608 44.435 16.632 ;
     RECT  47.185 13.584 47.315 13.608 ;
     RECT  43.955 6.912 48.848 7.464 ;
     RECT  48.805 12.48 48.848 12.504 ;
     RECT  48.848 0.528 48.952 18.372 ;
     RECT  48.952 0.798 49.04 18.372 ;
     RECT  49.04 0.798 49.144 18.642 ;
     RECT  49.144 13.584 49.324 13.608 ;
     RECT  49.144 10.32 50.149 10.344 ;
     RECT  50.149 10.32 50.437 10.968 ;
     RECT  50.437 9.792 50.524 10.968 ;
     RECT  50.437 13.296 50.533 13.32 ;
     RECT  50.533 12.768 50.54 13.32 ;
     RECT  50.524 10.464 50.627 10.968 ;
     RECT  50.54 12.432 50.725 13.32 ;
     RECT  50.725 12.24 50.905 13.32 ;
     RECT  50.905 12.24 50.908 12.696 ;
     RECT  50.627 10.464 51.347 10.632 ;
     RECT  51.347 10.608 51.395 10.632 ;
     RECT  52.945 9.168 53.029 9.192 ;
     RECT  50.908 12.24 53.557 12.264 ;
     RECT  49.144 6.912 54.248 7.464 ;
     RECT  53.557 12.24 54.248 12.504 ;
     RECT  53.557 14.064 54.248 14.088 ;
     RECT  54.205 15.216 54.248 15.24 ;
     RECT  54.248 0.528 54.352 18.372 ;
     RECT  54.352 0.798 54.44 18.372 ;
     RECT  54.44 0.798 54.544 18.642 ;
     RECT  54.544 15.216 54.659 15.24 ;
     RECT  54.544 12.144 54.851 12.264 ;
     RECT  58.117 13.728 58.313 13.752 ;
     RECT  58.357 14.4 58.444 14.424 ;
     RECT  54.851 12.144 58.549 12.168 ;
     RECT  58.549 12.144 58.741 12.264 ;
     RECT  58.741 12.048 58.849 12.264 ;
     RECT  54.544 6.912 59.648 7.464 ;
     RECT  58.849 11.328 59.648 12.264 ;
     RECT  59.648 0.528 59.752 18.372 ;
     RECT  59.752 0.798 59.84 18.372 ;
     RECT  59.84 0.798 59.944 18.642 ;
     RECT  59.944 9.648 60.227 9.672 ;
     RECT  59.944 11.328 60.515 12.072 ;
     RECT  59.944 6.912 60.965 8.04 ;
     RECT  60.965 6.288 60.977 8.04 ;
     RECT  60.977 6.288 61.049 7.464 ;
     RECT  62.341 16.512 62.428 16.536 ;
     RECT  60.515 12.048 62.677 12.072 ;
     RECT  62.621 17.136 62.705 17.16 ;
     RECT  62.677 12.048 62.819 12.168 ;
     RECT  62.821 9.744 63.101 9.768 ;
     RECT  61.049 6.912 63.253 7.464 ;
     RECT  63.253 6.912 63.349 7.896 ;
     RECT  63.269 9.168 63.349 9.672 ;
     RECT  63.349 6.912 63.533 9.672 ;
     RECT  63.533 6.912 63.683 7.8 ;
     RECT  63.683 6.912 63.829 7.464 ;
     RECT  63.829 6.288 63.965 7.464 ;
     RECT  63.533 8.784 63.965 9.672 ;
     RECT  63.965 6.912 65.048 7.464 ;
     RECT  63.965 8.784 65.048 9.24 ;
     RECT  62.819 12.048 65.048 12.072 ;
     RECT  65.048 0.528 65.152 18.372 ;
     RECT  65.152 0.798 65.24 18.372 ;
     RECT  65.24 0.798 65.344 18.642 ;
     RECT  65.344 10.32 65.477 10.92 ;
     RECT  65.344 6.24 65.801 7.656 ;
     RECT  65.477 10.8 66.227 10.92 ;
     RECT  65.801 6.912 66.275 7.656 ;
     RECT  66.227 10.896 66.323 10.92 ;
     RECT  65.344 12.048 66.565 12.072 ;
     RECT  66.565 12.048 66.707 12.264 ;
     RECT  66.707 12.096 67.229 12.264 ;
     RECT  67.229 12.096 67.285 13.08 ;
     RECT  67.285 12.096 67.313 13.608 ;
     RECT  67.313 13.584 67.372 13.608 ;
     RECT  65.344 8.784 67.813 8.808 ;
     RECT  67.813 8.688 67.897 8.808 ;
     RECT  67.897 8.784 68.281 8.808 ;
     RECT  68.281 8.784 68.387 9.096 ;
     RECT  67.313 12.096 68.917 12.12 ;
     RECT  68.917 12.096 68.965 12.168 ;
     RECT  67.909 10.848 69.116 10.872 ;
     RECT  69.116 10.368 69.203 10.872 ;
     RECT  69.203 10.848 69.221 10.872 ;
     RECT  68.965 12.096 69.299 12.264 ;
     RECT  66.275 6.912 69.301 7.464 ;
     RECT  68.387 8.784 69.301 8.808 ;
     RECT  69.301 6.912 69.388 8.808 ;
     RECT  69.299 12.144 69.395 12.264 ;
     RECT  69.395 12.24 69.401 12.264 ;
     RECT  69.388 8.784 69.541 8.808 ;
     RECT  69.388 6.912 70.448 7.464 ;
     RECT  69.541 8.784 70.448 9.72 ;
     RECT  70.448 0.528 70.552 18.372 ;
     RECT  70.552 0.798 70.64 18.372 ;
     RECT  70.64 0.798 70.744 18.642 ;
     RECT  70.744 8.784 70.885 9.72 ;
     RECT  70.744 14.352 70.921 14.376 ;
     RECT  70.744 12.912 71.404 13.272 ;
     RECT  70.744 10.896 71.525 10.92 ;
     RECT  71.404 13.248 71.597 13.272 ;
     RECT  70.885 8.784 71.797 8.808 ;
     RECT  71.948 10.368 72.035 10.392 ;
     RECT  72.025 14.208 72.109 14.232 ;
     RECT  70.744 6.912 72.236 7.464 ;
     RECT  71.797 8.736 72.236 8.808 ;
     RECT  72.236 6.912 72.421 8.808 ;
     RECT  72.373 5.808 72.497 5.832 ;
     RECT  72.421 6.912 72.505 10.296 ;
     RECT  72.949 16.08 73.037 16.104 ;
     RECT  72.505 10.272 73.145 10.296 ;
     RECT  72.949 14.256 73.361 14.28 ;
     RECT  72.505 6.912 73.525 8.808 ;
     RECT  73.525 5.136 73.865 5.16 ;
     RECT  73.525 6.288 73.907 8.808 ;
     RECT  73.82 15.12 73.907 15.144 ;
     RECT  73.525 10.848 73.937 10.872 ;
     RECT  73.907 6.288 73.973 7.608 ;
     RECT  73.973 6.288 74.009 7.512 ;
     RECT  74.009 6.288 74.081 7.464 ;
     RECT  74.101 12 74.189 12.024 ;
     RECT  74.245 16.272 74.333 16.296 ;
     RECT  75.068 16.512 75.356 16.536 ;
     RECT  74.081 6.912 75.692 7.464 ;
     RECT  73.907 8.784 75.692 8.808 ;
     RECT  75.049 13.056 75.733 13.08 ;
     RECT  75.625 14.208 75.733 14.232 ;
     RECT  75.229 4.896 75.848 4.92 ;
     RECT  74.828 5.904 75.848 5.928 ;
     RECT  75.692 6.912 75.848 8.808 ;
     RECT  75.221 10.848 75.848 10.872 ;
     RECT  74.773 11.952 75.848 11.976 ;
     RECT  75.733 13.056 75.848 14.232 ;
     RECT  75.356 16.512 75.848 17.064 ;
     RECT  75.848 0.528 75.952 18.372 ;
     RECT  75.952 0.798 76.04 18.372 ;
     RECT  76.04 0.798 76.144 18.642 ;
     RECT  76.144 12.96 76.169 13.08 ;
     RECT  76.169 12.96 76.259 12.984 ;
     RECT  76.144 9.936 76.601 10.968 ;
     RECT  76.144 16.512 76.691 16.536 ;
     RECT  76.601 10.896 76.883 10.968 ;
     RECT  76.144 6.24 76.972 7.464 ;
     RECT  76.144 14.256 76.997 15.144 ;
     RECT  76.997 14.256 77.105 14.28 ;
     RECT  76.883 10.944 77.429 10.968 ;
     RECT  76.972 6.816 78.065 7.464 ;
     RECT  78.065 6.768 78.073 7.464 ;
     RECT  77.996 12.864 78.083 12.888 ;
     RECT  78.085 11.568 78.185 11.592 ;
     RECT  78.085 15.6 78.293 15.624 ;
     RECT  78.073 6.192 78.371 7.464 ;
     RECT  78.371 6.192 78.563 6.216 ;
     RECT  78.661 4.56 78.748 4.584 ;
     RECT  78.661 16.848 79.189 16.872 ;
     RECT  79.189 16.848 79.225 17.112 ;
     RECT  76.144 8.784 79.237 8.808 ;
     RECT  79.225 16.56 79.309 17.112 ;
     RECT  79.309 17.088 79.484 17.112 ;
     RECT  79.484 17.088 79.571 17.352 ;
     RECT  79.237 8.784 79.697 9.24 ;
     RECT  79.909 11.76 79.996 11.784 ;
     RECT  79.697 8.784 80.269 8.808 ;
     RECT  78.371 7.44 80.629 7.464 ;
     RECT  80.389 15.84 80.629 15.864 ;
     RECT  80.629 7.344 80.725 7.464 ;
     RECT  80.269 8.544 80.725 8.808 ;
     RECT  80.725 7.344 80.917 8.808 ;
     RECT  80.917 13.248 81.109 13.272 ;
     RECT  80.629 15.84 81.109 16.824 ;
     RECT  80.917 7.344 81.248 9.288 ;
     RECT  80.389 10.272 81.248 10.296 ;
     RECT  81.109 13.248 81.248 16.824 ;
     RECT  81.248 0.528 81.352 18.372 ;
     RECT  81.352 0.798 81.44 18.372 ;
     RECT  81.44 0.798 81.544 18.642 ;
     RECT  81.544 11.568 81.721 11.976 ;
     RECT  81.544 14.496 81.721 14.664 ;
     RECT  81.544 5.136 81.749 5.16 ;
     RECT  81.544 17.28 81.827 17.304 ;
     RECT  81.544 13.104 81.893 13.128 ;
     RECT  81.721 14.64 81.929 14.664 ;
     RECT  81.721 11.952 82.067 11.976 ;
     RECT  81.544 6.192 82.348 6.216 ;
     RECT  81.544 8.544 82.645 9.288 ;
     RECT  82.645 17.088 82.973 17.112 ;
     RECT  83.18 12.528 83.267 12.552 ;
     RECT  83.221 16.56 83.305 16.584 ;
     RECT  82.645 8.544 83.405 9.624 ;
     RECT  83.797 4.56 83.909 4.584 ;
     RECT  83.797 10.848 83.989 10.872 ;
     RECT  83.989 10.848 84.013 10.968 ;
     RECT  83.941 13.152 84.044 13.176 ;
     RECT  84.044 13.152 84.131 13.56 ;
     RECT  84.131 13.152 84.227 13.176 ;
     RECT  84.013 10.848 84.371 11.448 ;
     RECT  84.371 10.848 84.373 10.968 ;
     RECT  84.365 15.216 84.373 15.24 ;
     RECT  84.373 14.784 84.449 15.24 ;
     RECT  84.373 12.72 84.593 12.744 ;
     RECT  84.373 10.656 84.659 10.968 ;
     RECT  81.544 7.44 84.661 7.464 ;
     RECT  84.449 14.784 84.665 14.808 ;
     RECT  84.841 10.32 84.925 10.344 ;
     RECT  84.941 6.096 85.025 6.12 ;
     RECT  84.949 5.04 85.033 5.064 ;
     RECT  84.661 7.392 85.189 7.464 ;
     RECT  85.189 6.816 85.276 7.464 ;
     RECT  85.445 13.536 85.529 13.56 ;
     RECT  85.477 5.712 85.565 5.736 ;
     RECT  84.949 16.032 85.705 16.056 ;
     RECT  85.276 7.44 86.648 7.464 ;
     RECT  83.405 8.544 86.648 8.808 ;
     RECT  86.533 13.056 86.648 13.08 ;
     RECT  85.705 16.032 86.648 16.584 ;
     RECT  86.648 0.528 86.752 18.372 ;
     RECT  86.752 0.798 86.84 18.372 ;
     RECT  86.84 0.798 86.944 18.642 ;
     RECT  86.944 12.528 87.059 14.088 ;
     RECT  86.944 16.224 87.059 16.92 ;
     RECT  86.944 10.56 87.244 11.256 ;
     RECT  87.244 10.56 87.257 10.584 ;
     RECT  87.059 16.224 87.257 16.584 ;
     RECT  87.257 16.56 87.329 16.584 ;
     RECT  87.059 12.528 87.869 13.656 ;
     RECT  87.869 12.528 87.875 13.56 ;
     RECT  86.944 6.864 88.069 7.464 ;
     RECT  87.875 12.528 88.085 13.032 ;
     RECT  88.357 14.736 88.445 14.904 ;
     RECT  88.085 13.008 88.589 13.032 ;
     RECT  88.445 14.88 88.693 14.904 ;
     RECT  88.357 10.464 88.769 10.488 ;
     RECT  88.693 14.88 88.769 15.48 ;
     RECT  88.769 15.456 88.777 15.48 ;
     RECT  88.837 10.848 88.885 10.872 ;
     RECT  88.901 5.712 88.985 5.736 ;
     RECT  88.885 10.848 88.985 10.968 ;
     RECT  88.985 10.944 89.021 10.968 ;
     RECT  88.069 6.768 89.077 7.464 ;
     RECT  89.077 6.432 89.165 7.464 ;
     RECT  89.165 6.768 89.219 7.464 ;
     RECT  89.18 16.416 89.267 16.44 ;
     RECT  89.749 11.568 89.804 11.592 ;
     RECT  89.804 11.568 89.891 11.64 ;
     RECT  89.891 11.568 90.131 11.592 ;
     RECT  90.205 10.752 90.611 10.776 ;
     RECT  89.219 7.44 90.637 7.464 ;
     RECT  90.061 16.512 90.677 16.536 ;
     RECT  90.637 6.72 90.749 7.464 ;
     RECT  86.944 8.544 91.573 8.808 ;
     RECT  91.573 8.544 91.765 9.096 ;
     RECT  91.745 12.192 91.765 12.216 ;
     RECT  90.749 7.44 91.909 7.464 ;
     RECT  91.909 6.672 92.048 7.464 ;
     RECT  91.765 8.544 92.048 9.288 ;
     RECT  91.765 11.616 92.048 12.216 ;
     RECT  91.045 13.392 92.048 13.416 ;
     RECT  92.048 0.528 92.152 18.372 ;
     RECT  92.152 0.798 92.24 18.372 ;
     RECT  92.24 0.798 92.344 18.642 ;
     RECT  92.344 6.672 92.477 7.464 ;
     RECT  92.477 6.816 92.483 7.464 ;
     RECT  92.344 9.792 92.621 9.816 ;
     RECT  92.344 17.04 92.812 17.064 ;
     RECT  93.481 15.984 94.069 16.008 ;
     RECT  94.069 15.744 94.124 16.008 ;
     RECT  94.124 15.312 94.165 16.008 ;
     RECT  94.165 15.312 94.252 16.536 ;
     RECT  94.069 6.192 94.385 6.216 ;
     RECT  94.252 15.312 94.405 15.768 ;
     RECT  94.405 15.12 94.493 15.768 ;
     RECT  94.633 11.232 94.645 11.256 ;
     RECT  94.645 14.304 94.745 14.328 ;
     RECT  92.344 8.544 94.796 8.808 ;
     RECT  94.645 10.416 94.796 11.256 ;
     RECT  94.796 8.544 94.883 11.256 ;
     RECT  94.844 16.8 94.931 16.824 ;
     RECT  94.883 10.416 94.961 11.256 ;
     RECT  94.493 15.744 94.997 15.768 ;
     RECT  94.94 12.288 95.027 12.312 ;
     RECT  94.961 10.992 95.141 11.256 ;
     RECT  92.483 7.44 95.173 7.464 ;
     RECT  95.173 6.24 95.411 7.464 ;
     RECT  95.411 6.24 95.749 6.264 ;
     RECT  95.749 5.664 95.933 6.264 ;
     RECT  95.9 9.984 95.987 10.008 ;
     RECT  95.749 13.632 96.037 13.656 ;
     RECT  95.141 11.232 96.077 11.256 ;
     RECT  96.037 13.488 96.149 13.656 ;
     RECT  95.933 5.664 96.221 5.688 ;
     RECT  96.149 13.488 96.323 13.512 ;
     RECT  94.883 8.544 96.997 8.808 ;
     RECT  95.411 7.44 97.448 7.464 ;
     RECT  96.997 8.448 97.448 8.808 ;
     RECT  96.764 10.272 97.448 10.872 ;
     RECT  97.448 0.528 97.552 18.372 ;
     RECT  97.552 0.798 97.64 18.372 ;
     RECT  97.64 0.798 97.744 18.642 ;
     RECT  97.744 13.152 97.859 13.512 ;
     RECT  97.859 13.488 98.813 13.512 ;
     RECT  97.744 16.608 98.849 17.064 ;
     RECT  97.744 15.408 98.957 15.432 ;
     RECT  97.744 7.44 99.209 8.808 ;
     RECT  99.209 7.44 99.356 7.464 ;
     RECT  99.356 6.576 99.443 7.464 ;
     RECT  99.157 5.136 99.569 5.16 ;
     RECT  98.849 16.608 99.929 16.632 ;
     RECT  101.393 16.08 101.461 16.104 ;
     RECT  101.461 15.984 101.477 16.104 ;
     RECT  101.477 15.984 102.625 16.008 ;
     RECT  102.613 4.56 102.709 4.584 ;
     RECT  102.709 4.56 102.848 4.968 ;
     RECT  99.443 7.44 102.848 7.464 ;
     RECT  99.209 8.448 102.848 8.808 ;
     RECT  102.625 15.984 102.848 16.632 ;
     RECT  102.661 18.144 102.848 18.168 ;
     RECT  102.848 0.528 102.952 18.372 ;
     RECT  102.952 0.798 103.04 18.372 ;
     RECT  103.04 0.798 103.144 18.642 ;
     RECT  103.144 16.608 103.853 17.016 ;
     RECT  103.144 5.616 104.105 5.64 ;
     RECT  103.853 16.608 104.293 16.632 ;
     RECT  104.293 16.56 104.789 16.632 ;
     RECT  104.789 16.608 104.969 16.632 ;
     RECT  104.869 5.136 105.077 5.16 ;
     RECT  107.221 11.136 107.612 11.16 ;
     RECT  103.144 8.448 108.248 8.808 ;
     RECT  107.612 11.088 108.248 11.16 ;
     RECT  103.144 18.144 108.248 18.168 ;
     RECT  108.248 0.528 108.352 18.372 ;
     RECT  108.352 0.798 108.44 18.372 ;
     RECT  108.44 0.798 108.544 18.642 ;
     RECT  108.544 9.984 109.073 10.2 ;
     RECT  109.073 10.176 109.427 10.2 ;
     RECT  108.544 8.448 110.581 8.808 ;
     RECT  110.581 7.68 110.617 8.808 ;
     RECT  110.245 10.512 110.617 10.536 ;
     RECT  110.581 14.4 110.617 14.424 ;
     RECT  110.617 7.68 111.157 10.536 ;
     RECT  110.617 14.4 111.157 14.664 ;
     RECT  111.157 13.344 112.849 13.368 ;
     RECT  111.157 14.4 112.849 15.288 ;
     RECT  111.733 17.088 112.849 17.112 ;
     RECT  108.544 18.144 112.849 18.168 ;
     RECT  111.157 7.68 112.885 11.448 ;
     RECT  112.885 7.68 113.029 11.544 ;
     RECT  112.849 13.344 113.425 16.056 ;
     RECT  112.849 17.088 113.425 18.168 ;
     RECT  113.029 6.912 113.648 11.544 ;
     RECT  113.425 13.344 113.648 18.168 ;
     RECT  113.648 0.528 113.752 18.372 ;
     RECT  113.752 0.798 113.84 18.372 ;
     RECT  113.84 0.798 113.944 18.642 ;
     RECT  113.944 6.432 114.613 18.642 ;
     RECT  114.613 6.432 115.141 18.648 ;
     RECT  115.141 6.288 115.265 18.744 ;
     RECT  115.265 6.432 115.596 18.744 ;
    LAYER M5 ;
     RECT  0.24 0.517 0.36 0.787 ;
     RECT  5.64 0.517 5.76 0.787 ;
     RECT  11.04 0.517 11.16 0.787 ;
     RECT  16.44 0.517 16.56 0.787 ;
     RECT  21.84 0.517 21.96 0.787 ;
     RECT  27.24 0.517 27.36 0.787 ;
     RECT  32.64 0.517 32.76 0.787 ;
     RECT  38.04 0.517 38.16 0.787 ;
     RECT  43.44 0.517 43.56 0.787 ;
     RECT  48.84 0.517 48.96 0.787 ;
     RECT  54.24 0.517 54.36 0.787 ;
     RECT  59.64 0.517 59.76 0.787 ;
     RECT  65.04 0.517 65.16 0.787 ;
     RECT  70.44 0.517 70.56 0.787 ;
     RECT  75.84 0.517 75.96 0.787 ;
     RECT  81.24 0.517 81.36 0.787 ;
     RECT  86.64 0.517 86.76 0.787 ;
     RECT  92.04 0.517 92.16 0.787 ;
     RECT  97.44 0.517 97.56 0.787 ;
     RECT  102.84 0.517 102.96 0.787 ;
     RECT  108.24 0.517 108.36 0.787 ;
     RECT  113.64 0.517 113.76 0.787 ;
     RECT  0.24 0.787 0.552 3.397 ;
     RECT  0.144 3.397 0.552 4.011 ;
     RECT  1.728 3.445 1.752 4.069 ;
     RECT  102.84 0.787 103.152 4.085 ;
     RECT  0.24 4.011 0.552 4.117 ;
     RECT  1.728 4.069 2.28 4.117 ;
     RECT  0.24 4.117 2.28 4.395 ;
     RECT  78.672 4.341 78.696 4.595 ;
     RECT  83.808 4.149 83.832 4.595 ;
     RECT  102.624 4.085 103.152 4.595 ;
     RECT  75.84 0.787 76.152 4.847 ;
     RECT  81.24 0.787 81.552 4.917 ;
     RECT  75.264 4.847 76.152 4.931 ;
     RECT  0.24 4.395 1.128 4.971 ;
     RECT  102.72 4.595 103.152 5.035 ;
     RECT  73.536 5.087 73.56 5.171 ;
     RECT  81.24 4.917 81.672 5.171 ;
     RECT  99.168 4.661 99.192 5.171 ;
     RECT  104.88 4.981 104.904 5.171 ;
     RECT  0.24 4.971 1.032 5.237 ;
     RECT  84.96 5.029 84.984 5.429 ;
     RECT  11.04 0.787 11.352 5.461 ;
     RECT  2.256 4.395 2.28 5.497 ;
     RECT  102.84 5.035 103.152 5.605 ;
     RECT  102.84 5.605 103.752 5.689 ;
     RECT  95.76 5.653 95.784 5.739 ;
     RECT  3.984 5.237 4.008 5.747 ;
     RECT  84.96 5.429 85.512 5.747 ;
     RECT  88.944 5.173 88.968 5.747 ;
     RECT  5.64 0.787 5.952 5.749 ;
     RECT  72.384 5.749 72.408 5.843 ;
     RECT  75.84 4.931 76.152 5.893 ;
     RECT  74.88 5.893 76.152 5.995 ;
     RECT  0.144 5.237 1.032 6.083 ;
     RECT  84.96 5.747 84.984 6.131 ;
     RECT  4.992 5.749 5.952 6.133 ;
     RECT  81.24 5.171 81.552 6.163 ;
     RECT  0.24 6.083 1.032 6.191 ;
     RECT  65.04 0.787 65.352 6.191 ;
     RECT  94.08 6.133 94.104 6.227 ;
     RECT  75.84 5.995 76.152 6.229 ;
     RECT  81.24 6.163 82.296 6.251 ;
     RECT  0.24 6.191 1.128 6.261 ;
     RECT  11.04 5.461 11.592 6.261 ;
     RECT  78.528 6.181 78.552 6.265 ;
     RECT  0.24 6.261 1.656 6.275 ;
     RECT  65.04 6.191 65.592 6.275 ;
     RECT  61.008 5.557 61.032 6.323 ;
     RECT  63.84 6.005 63.864 6.323 ;
     RECT  73.536 6.239 73.56 6.323 ;
     RECT  115.152 6.239 115.176 6.323 ;
     RECT  1.632 6.275 1.656 6.371 ;
     RECT  9.072 5.621 9.096 6.371 ;
     RECT  16.44 0.787 16.752 6.661 ;
     RECT  92.04 0.787 92.352 6.661 ;
     RECT  89.088 6.261 89.112 6.739 ;
     RECT  95.28 6.229 95.4 6.739 ;
     RECT  16.44 6.661 16.872 6.767 ;
     RECT  91.92 6.661 92.352 6.767 ;
     RECT  2.832 5.663 2.856 6.773 ;
     RECT  4.512 6.133 5.952 6.773 ;
     RECT  11.04 6.261 12.024 6.773 ;
     RECT  95.184 6.739 95.4 6.803 ;
     RECT  4.512 6.773 6.072 6.805 ;
     RECT  2.832 6.773 3 6.815 ;
     RECT  78.096 6.739 78.36 6.827 ;
     RECT  88.08 6.739 88.104 6.827 ;
     RECT  89.088 6.739 89.208 6.827 ;
     RECT  91.92 6.767 92.472 6.827 ;
     RECT  95.184 6.803 95.304 6.827 ;
     RECT  99.408 6.565 99.432 6.827 ;
     RECT  38.04 0.787 38.352 6.837 ;
     RECT  43.44 0.787 43.752 6.837 ;
     RECT  81.24 6.251 81.552 6.837 ;
     RECT  86.64 0.787 86.952 6.837 ;
     RECT  8.496 6.757 8.52 6.841 ;
     RECT  10.608 6.773 12.024 6.851 ;
     RECT  16.32 6.767 16.968 6.851 ;
     RECT  92.04 6.827 92.472 6.851 ;
     RECT  43.44 6.837 43.944 6.853 ;
     RECT  2.256 6.815 3 6.861 ;
     RECT  75.84 6.229 76.92 6.891 ;
     RECT  2.256 6.861 2.904 6.899 ;
     RECT  39.888 6.837 39.912 6.925 ;
     RECT  42.624 6.853 43.944 6.925 ;
     RECT  86.64 6.837 87.24 6.925 ;
     RECT  78.24 6.827 78.36 6.947 ;
     RECT  95.28 6.827 95.304 6.947 ;
     RECT  70.44 0.787 70.752 7.189 ;
     RECT  4.032 6.805 6.072 7.237 ;
     RECT  80.736 6.837 81.552 7.333 ;
     RECT  0.24 6.275 0.648 7.381 ;
     RECT  2.256 6.899 2.328 7.381 ;
     RECT  85.2 6.805 85.224 7.381 ;
     RECT  4.032 7.237 6.936 7.403 ;
     RECT  10.608 6.851 11.88 7.403 ;
     RECT  38.04 6.837 38.904 7.403 ;
     RECT  42.624 6.925 43.848 7.403 ;
     RECT  75.84 6.891 76.344 7.403 ;
     RECT  84.72 7.381 85.224 7.403 ;
     RECT  80.64 7.333 81.552 7.417 ;
     RECT  4.272 7.403 6.936 7.467 ;
     RECT  84.72 7.403 84.744 7.467 ;
     RECT  5.64 7.467 6.936 7.531 ;
     RECT  70.44 7.189 71.304 7.531 ;
     RECT  97.44 0.787 97.752 7.573 ;
     RECT  65.04 6.275 65.352 7.621 ;
     RECT  10.608 7.403 11.352 7.669 ;
     RECT  65.04 7.621 66.264 7.723 ;
     RECT  67.872 7.189 67.896 7.787 ;
     RECT  0.24 7.381 2.328 7.851 ;
     RECT  4.272 7.467 4.488 7.851 ;
     RECT  69.312 7.669 69.336 7.859 ;
     RECT  80.736 7.417 81.552 7.859 ;
     RECT  63.648 7.765 63.672 7.861 ;
     RECT  13.68 7.669 13.704 7.915 ;
     RECT  63.264 7.861 63.672 7.945 ;
     RECT  0.24 7.851 1.896 7.979 ;
     RECT  73.536 7.535 73.56 7.989 ;
     RECT  59.64 0.787 59.952 8.005 ;
     RECT  72.288 7.765 72.312 8.043 ;
     RECT  59.64 8.005 60.888 8.107 ;
     RECT  73.536 7.989 73.896 8.147 ;
     RECT  4.464 7.851 4.488 8.235 ;
     RECT  72.96 8.149 72.984 8.235 ;
     RECT  0.24 7.979 1.704 8.245 ;
     RECT  97.44 7.573 98.088 8.245 ;
     RECT  0.144 8.245 1.704 8.329 ;
     RECT  8.736 8.275 8.76 8.363 ;
     RECT  75.84 7.403 76.248 8.373 ;
     RECT  96.96 8.245 98.088 8.373 ;
     RECT  96.912 8.373 98.088 8.427 ;
     RECT  13.92 8.309 13.944 8.435 ;
     RECT  75.744 8.373 77.016 8.461 ;
     RECT  10.272 7.669 11.352 8.485 ;
     RECT  10.224 8.485 11.352 8.495 ;
     RECT  102.84 5.689 103.152 8.543 ;
     RECT  74.688 8.373 74.712 8.555 ;
     RECT  75.84 8.461 77.016 8.555 ;
     RECT  9.696 8.495 11.352 8.579 ;
     RECT  88.176 8.543 88.2 8.627 ;
     RECT  95.76 8.245 95.784 8.627 ;
     RECT  102.624 8.543 103.152 8.627 ;
     RECT  92.04 6.851 92.352 8.629 ;
     RECT  91.2 8.629 92.352 8.713 ;
     RECT  67.824 8.677 67.848 8.761 ;
     RECT  71.808 8.687 71.832 8.771 ;
     RECT  96.912 8.427 97.752 8.771 ;
     RECT  5.64 7.531 5.952 8.949 ;
     RECT  19.584 8.821 19.608 8.949 ;
     RECT  21.84 0.787 22.152 8.949 ;
     RECT  63.648 7.945 63.672 8.949 ;
     RECT  21.264 8.949 22.152 9.061 ;
     RECT  10.128 8.579 11.352 9.131 ;
     RECT  68.352 9.043 68.376 9.131 ;
     RECT  91.584 8.713 92.352 9.131 ;
     RECT  62.736 8.949 63.672 9.141 ;
     RECT  65.04 7.723 65.352 9.141 ;
     RECT  81.24 7.859 81.552 9.141 ;
     RECT  82.752 8.543 82.776 9.141 ;
     RECT  21.12 9.061 22.152 9.145 ;
     RECT  0.24 8.329 1.704 9.195 ;
     RECT  52.992 9.119 53.016 9.203 ;
     RECT  62.736 9.141 65.352 9.203 ;
     RECT  18.816 8.949 19.608 9.205 ;
     RECT  81.24 9.141 82.776 9.253 ;
     RECT  5.136 8.949 5.952 9.263 ;
     RECT  79.248 9.205 79.272 9.289 ;
     RECT  91.776 9.131 92.352 9.299 ;
     RECT  18.816 9.205 19.992 9.323 ;
     RECT  80.928 9.253 82.776 9.323 ;
     RECT  70.44 7.531 70.752 9.333 ;
     RECT  5.088 9.263 5.952 9.347 ;
     RECT  0.24 9.195 0.744 9.387 ;
     RECT  5.64 9.347 5.952 9.397 ;
     RECT  0.24 9.387 0.648 9.451 ;
     RECT  18.816 9.323 19.368 9.451 ;
     RECT  21.36 9.145 22.152 9.451 ;
     RECT  5.64 9.397 6.168 9.515 ;
     RECT  83.232 9.445 83.256 9.529 ;
     RECT  62.736 9.203 62.856 9.579 ;
     RECT  63.84 9.203 65.352 9.579 ;
     RECT  70.44 9.333 70.872 9.589 ;
     RECT  59.64 8.107 59.952 9.619 ;
     RECT  2.016 9.349 2.04 9.695 ;
     RECT  18.912 9.451 19.368 9.707 ;
     RECT  59.64 9.619 60.216 9.707 ;
     RECT  94.848 9.619 94.872 9.707 ;
     RECT  63.84 9.579 63.864 9.721 ;
     RECT  7.44 9.397 7.464 9.731 ;
     RECT  69.552 9.589 70.872 9.731 ;
     RECT  92.04 9.299 92.352 9.747 ;
     RECT  2.016 9.695 2.808 9.779 ;
     RECT  62.832 9.579 62.856 9.779 ;
     RECT  92.04 9.747 92.568 9.835 ;
     RECT  75.84 8.555 76.152 9.887 ;
     RECT  18.912 9.707 18.936 9.963 ;
     RECT  108.24 0.787 108.552 9.973 ;
     RECT  95.952 9.909 95.976 10.019 ;
     RECT  97.44 8.771 97.752 10.037 ;
     RECT  4.512 10.079 4.536 10.163 ;
     RECT  2.016 9.779 2.28 10.165 ;
     RECT  72.432 9.695 72.456 10.165 ;
     RECT  108.24 9.973 108.888 10.165 ;
     RECT  80.928 9.323 81.552 10.223 ;
     RECT  108.24 10.165 109.416 10.249 ;
     RECT  65.04 9.579 65.352 10.271 ;
     RECT  48.84 0.787 49.152 10.293 ;
     RECT  50.448 9.747 50.472 10.293 ;
     RECT  72.432 10.165 72.984 10.307 ;
     RECT  80.4 10.223 81.552 10.307 ;
     RECT  111.168 10.165 111.192 10.307 ;
     RECT  84.864 10.271 84.888 10.355 ;
     RECT  48.84 10.293 50.472 10.381 ;
     RECT  69.168 10.323 69.192 10.411 ;
     RECT  72 10.323 72.024 10.411 ;
     RECT  50.16 10.381 50.472 10.453 ;
     RECT  50.16 10.453 51.336 10.538 ;
     RECT  88.368 10.453 88.392 10.539 ;
     RECT  86.64 6.925 86.952 10.549 ;
     RECT  86.64 10.549 87.24 10.633 ;
     RECT  50.16 10.538 51.384 10.643 ;
     RECT  83.808 10.613 83.832 10.645 ;
     RECT  5.64 9.515 5.952 10.741 ;
     RECT  65.04 10.271 65.448 10.775 ;
     RECT  16.44 6.851 16.752 10.805 ;
     RECT  65.04 10.775 66.216 10.805 ;
     RECT  90.576 10.741 90.6 10.825 ;
     RECT  75.84 9.887 76.392 10.837 ;
     RECT  70.44 9.731 70.752 10.847 ;
     RECT  75.264 10.837 76.392 10.847 ;
     RECT  67.92 10.677 67.944 10.883 ;
     RECT  73.536 10.357 73.56 10.883 ;
     RECT  83.808 10.645 84.648 10.883 ;
     RECT  1.68 10.165 2.28 10.893 ;
     RECT  88.848 10.741 88.92 10.893 ;
     RECT  4.752 10.741 5.952 10.923 ;
     RECT  75.264 10.847 76.872 10.923 ;
     RECT  65.04 10.805 66.312 10.931 ;
     RECT  70.44 10.847 71.304 10.931 ;
     RECT  75.84 10.923 76.872 10.931 ;
     RECT  14.928 10.805 14.952 10.933 ;
     RECT  16.32 10.805 16.752 10.933 ;
     RECT  50.16 10.643 50.616 10.979 ;
     RECT  88.896 10.893 88.92 10.979 ;
     RECT  11.04 9.131 11.352 10.981 ;
     RECT  14.832 10.933 14.952 10.987 ;
     RECT  84 10.883 84.648 10.987 ;
     RECT  38.04 7.403 38.352 10.991 ;
     RECT  84 10.987 84.36 11.017 ;
     RECT  94.656 9.845 94.68 11.027 ;
     RECT  62.736 10.869 62.76 11.051 ;
     RECT  108.24 10.249 108.552 11.061 ;
     RECT  1.68 10.893 1.704 11.075 ;
     RECT  38.04 10.991 39.336 11.075 ;
     RECT  11.04 10.981 11.448 11.115 ;
     RECT  110.256 10.501 110.28 11.115 ;
     RECT  59.64 9.707 59.952 11.125 ;
     RECT  107.664 11.061 108.552 11.125 ;
     RECT  38.04 11.075 38.76 11.155 ;
     RECT  32.64 0.787 32.952 11.183 ;
     RECT  107.232 11.125 108.552 11.222 ;
     RECT  14.832 10.987 14.856 11.243 ;
     RECT  16.32 10.933 16.968 11.243 ;
     RECT  0.24 9.451 0.552 11.269 ;
     RECT  86.64 10.633 87.192 11.277 ;
     RECT  94.752 11.029 94.776 11.307 ;
     RECT  96.816 10.037 97.752 11.307 ;
     RECT  107.664 11.222 108.552 11.307 ;
     RECT  7.392 9.829 7.416 11.317 ;
     RECT  32.448 11.183 32.952 11.317 ;
     RECT  59.64 11.125 60.504 11.317 ;
     RECT  5.64 10.923 5.952 11.365 ;
     RECT  7.392 11.317 7.464 11.365 ;
     RECT  37.248 11.155 38.76 11.371 ;
     RECT  58.944 11.317 60.504 11.371 ;
     RECT  32.4 11.317 32.952 11.411 ;
     RECT  5.64 11.365 7.464 11.459 ;
     RECT  16.32 11.243 16.752 11.459 ;
     RECT  84.336 11.017 84.36 11.459 ;
     RECT  81.24 10.307 81.552 11.509 ;
     RECT  90.096 11.539 90.12 11.557 ;
     RECT  5.64 11.459 7.416 11.563 ;
     RECT  92.04 9.835 92.352 11.567 ;
     RECT  78.096 11.509 78.696 11.603 ;
     RECT  89.76 11.557 90.12 11.627 ;
     RECT  89.76 11.627 89.88 11.641 ;
     RECT  89.856 11.641 89.88 11.661 ;
     RECT  78.672 11.603 78.696 11.691 ;
     RECT  7.392 11.563 7.416 11.699 ;
     RECT  79.92 11.637 79.944 11.795 ;
     RECT  74.112 11.445 74.136 11.941 ;
     RECT  81.24 11.509 81.672 11.941 ;
     RECT  74.112 11.941 74.808 12.035 ;
     RECT  27.24 0.787 27.552 12.037 ;
     RECT  58.944 11.371 59.952 12.037 ;
     RECT  66.672 12.037 66.696 12.085 ;
     RECT  58.752 12.037 59.952 12.115 ;
     RECT  21.84 9.451 22.152 12.133 ;
     RECT  54.24 0.787 54.552 12.133 ;
     RECT  62.784 12.115 62.808 12.133 ;
     RECT  69.264 12.085 69.288 12.133 ;
     RECT  0.24 11.269 1.512 12.143 ;
     RECT  21.84 12.133 22.824 12.149 ;
     RECT  54.24 12.133 54.744 12.149 ;
     RECT  58.656 12.115 59.952 12.149 ;
     RECT  66.672 12.085 66.792 12.149 ;
     RECT  26.64 12.037 27.552 12.191 ;
     RECT  28.608 12.037 28.632 12.191 ;
     RECT  50.592 10.979 50.616 12.191 ;
     RECT  26.64 12.191 28.632 12.203 ;
     RECT  62.688 12.133 62.808 12.203 ;
     RECT  0.24 12.143 2.28 12.213 ;
     RECT  21.84 12.149 22.92 12.213 ;
     RECT  50.592 12.191 50.76 12.213 ;
     RECT  54.24 12.149 54.84 12.213 ;
     RECT  62.688 12.203 62.712 12.217 ;
     RECT  68.928 12.133 69.384 12.217 ;
     RECT  91.776 11.567 92.352 12.227 ;
     RECT  27.24 12.203 28.632 12.267 ;
     RECT  68.976 12.217 69.384 12.267 ;
     RECT  9.072 12.191 9.096 12.275 ;
     RECT  27.24 12.267 28.536 12.275 ;
     RECT  58.56 12.149 59.952 12.275 ;
     RECT  66.576 12.149 66.888 12.275 ;
     RECT  68.976 12.267 69 12.275 ;
     RECT  0.24 12.213 2.76 12.277 ;
     RECT  3.744 12.213 3.768 12.301 ;
     RECT  94.992 12.213 95.016 12.323 ;
     RECT  21.648 12.213 22.92 12.371 ;
     RECT  0.144 12.277 2.76 12.467 ;
     RECT  53.568 12.213 54.84 12.515 ;
     RECT  86.64 11.277 86.952 12.517 ;
     RECT  38.04 11.371 38.352 12.709 ;
     RECT  81.24 11.941 82.056 12.779 ;
     RECT  37.584 12.709 38.352 12.793 ;
     RECT  84.384 12.709 84.408 12.793 ;
     RECT  0.144 12.467 1.032 12.843 ;
     RECT  75.84 10.931 76.152 12.853 ;
     RECT  70.44 10.931 70.752 12.901 ;
     RECT  78.048 12.819 78.072 12.907 ;
     RECT  83.232 12.517 83.256 12.907 ;
     RECT  0.24 12.843 1.032 12.937 ;
     RECT  11.04 11.115 11.352 12.959 ;
     RECT  74.784 12.035 74.808 13.035 ;
     RECT  80.016 12.853 80.04 13.035 ;
     RECT  10.704 12.959 11.352 13.043 ;
     RECT  97.44 11.307 97.752 13.103 ;
     RECT  50.592 12.213 50.856 13.109 ;
     RECT  81.24 12.779 81.672 13.139 ;
     RECT  67.248 13.045 67.272 13.163 ;
     RECT  84.096 13.103 84.216 13.187 ;
     RECT  81.24 13.139 81.552 13.237 ;
     RECT  50.592 13.109 50.904 13.267 ;
     RECT  80.928 13.237 81.552 13.321 ;
     RECT  50.448 13.267 50.904 13.355 ;
     RECT  92.04 12.227 92.352 13.365 ;
     RECT  50.832 13.355 50.904 13.369 ;
     RECT  0.24 12.937 0.648 13.379 ;
     RECT  97.44 13.103 97.848 13.429 ;
     RECT  91.056 13.365 92.352 13.453 ;
     RECT  50.88 13.369 50.904 13.483 ;
     RECT  54.24 12.515 54.84 13.483 ;
     RECT  2.256 12.467 2.52 13.493 ;
     RECT  96.288 13.429 96.312 13.523 ;
     RECT  97.44 13.429 98.664 13.523 ;
     RECT  2.256 13.493 2.76 13.525 ;
     RECT  2.256 13.525 3.336 13.535 ;
     RECT  48.84 10.381 49.152 13.557 ;
     RECT  84.096 13.187 84.12 13.571 ;
     RECT  86.64 12.517 87.864 13.571 ;
     RECT  70.44 12.901 71.352 13.611 ;
     RECT  85.488 13.525 85.512 13.611 ;
     RECT  47.28 13.535 47.304 13.619 ;
     RECT  48.84 13.557 49.272 13.645 ;
     RECT  67.296 13.557 67.32 13.645 ;
     RECT  86.64 13.571 87.816 13.667 ;
     RECT  95.76 13.621 95.784 13.705 ;
     RECT  75.84 12.853 76.248 13.727 ;
     RECT  58.128 13.679 58.152 13.763 ;
     RECT  75.744 13.727 76.248 13.877 ;
     RECT  2.256 13.535 3.432 13.955 ;
     RECT  18.912 13.813 18.936 14.005 ;
     RECT  20.496 13.971 20.52 14.005 ;
     RECT  21.84 12.371 22.152 14.005 ;
     RECT  54.24 13.483 54.552 14.005 ;
     RECT  20.352 14.005 20.52 14.059 ;
     RECT  3.408 13.955 3.432 14.099 ;
     RECT  20.352 14.059 20.376 14.099 ;
     RECT  53.568 14.005 54.552 14.099 ;
     RECT  86.64 13.667 87.048 14.099 ;
     RECT  18.816 14.005 18.936 14.187 ;
     RECT  72.96 13.941 72.984 14.197 ;
     RECT  75.744 13.877 76.968 14.197 ;
     RECT  72.048 14.197 72.984 14.281 ;
     RECT  75.648 14.197 76.968 14.281 ;
     RECT  72.96 14.281 72.984 14.291 ;
     RECT  3.936 14.255 3.96 14.339 ;
     RECT  94.656 14.255 94.68 14.339 ;
     RECT  70.44 13.611 70.872 14.387 ;
     RECT  58.368 14.355 58.392 14.443 ;
     RECT  81.12 13.321 81.552 14.447 ;
     RECT  81.12 14.447 81.672 14.531 ;
     RECT  0.24 13.379 0.552 14.533 ;
     RECT  2.256 13.955 2.28 14.533 ;
     RECT  18.912 14.187 18.936 14.571 ;
     RECT  27.24 12.275 27.552 14.581 ;
     RECT  11.04 13.043 11.352 14.611 ;
     RECT  21.744 14.005 22.152 14.611 ;
     RECT  26.736 14.581 27.552 14.645 ;
     RECT  10.944 14.611 11.352 14.699 ;
     RECT  21.648 14.611 22.152 14.699 ;
     RECT  26.4 14.645 27.552 14.733 ;
     RECT  88.368 14.687 88.392 14.915 ;
     RECT  97.44 13.523 97.752 14.965 ;
     RECT  54.24 14.099 54.552 15.093 ;
     RECT  75.84 14.281 76.968 15.155 ;
     RECT  73.872 15.093 73.896 15.181 ;
     RECT  54.24 15.093 54.648 15.251 ;
     RECT  84.384 14.739 84.408 15.289 ;
     RECT  94.416 15.093 94.44 15.301 ;
     RECT  97.44 14.965 98.664 15.443 ;
     RECT  5.64 11.563 5.952 15.445 ;
     RECT  15.216 15.397 15.24 15.481 ;
     RECT  88.704 15.407 88.728 15.491 ;
     RECT  32.64 11.411 32.952 15.589 ;
     RECT  78.096 15.541 78.12 15.635 ;
     RECT  32.64 15.589 33.672 15.637 ;
     RECT  101.472 15.477 101.496 15.669 ;
     RECT  102.84 8.627 103.152 15.669 ;
     RECT  32.64 15.637 34.2 15.673 ;
     RECT  34.176 15.673 34.2 15.723 ;
     RECT  94.176 15.301 94.44 15.733 ;
     RECT  94.08 15.733 94.92 15.797 ;
     RECT  81.12 14.531 81.552 15.829 ;
     RECT  5.64 15.445 6.072 15.877 ;
     RECT  80.4 15.829 81.552 15.915 ;
     RECT  113.64 0.787 113.952 15.925 ;
     RECT  11.04 14.699 11.352 15.989 ;
     RECT  5.64 15.877 7.464 16.019 ;
     RECT  93.504 15.797 94.92 16.019 ;
     RECT  101.472 15.669 103.152 16.031 ;
     RECT  113.64 15.925 114.6 16.043 ;
     RECT  18.48 15.973 18.504 16.057 ;
     RECT  101.424 16.031 103.152 16.057 ;
     RECT  72.96 16.031 72.984 16.115 ;
     RECT  101.424 16.057 101.448 16.115 ;
     RECT  10.704 15.989 11.352 16.171 ;
     RECT  86.64 14.099 86.952 16.175 ;
     RECT  0.24 14.533 2.28 16.259 ;
     RECT  86.64 16.175 87.24 16.259 ;
     RECT  86.64 16.259 87.048 16.309 ;
     RECT  86.544 16.309 87.048 16.393 ;
     RECT  74.256 16.261 74.28 16.467 ;
     RECT  75.84 15.155 76.152 16.467 ;
     RECT  89.232 16.405 89.256 16.491 ;
     RECT  74.256 16.467 76.152 16.501 ;
     RECT  0.24 16.259 1.8 16.555 ;
     RECT  74.256 16.501 76.68 16.555 ;
     RECT  43.44 7.403 43.752 16.559 ;
     RECT  5.64 16.019 6.072 16.595 ;
     RECT  7.44 16.019 7.464 16.595 ;
     RECT  83.232 16.437 83.256 16.595 ;
     RECT  104.304 16.053 104.328 16.595 ;
     RECT  43.44 16.559 44.424 16.643 ;
     RECT  79.248 16.373 79.272 16.799 ;
     RECT  62.352 16.501 62.376 16.811 ;
     RECT  97.44 15.443 97.752 16.821 ;
     RECT  0.24 16.555 0.648 16.825 ;
     RECT  75.408 16.555 76.68 16.875 ;
     RECT  94.176 16.019 94.92 16.875 ;
     RECT  78.672 16.799 79.272 16.883 ;
     RECT  86.64 16.393 87.048 16.931 ;
     RECT  102.84 16.057 103.152 16.981 ;
     RECT  80.64 15.915 81.552 17.003 ;
     RECT  92.04 13.453 92.352 17.013 ;
     RECT  1.68 16.555 1.8 17.027 ;
     RECT  94.176 16.875 94.2 17.067 ;
     RECT  102.84 16.981 103.752 17.067 ;
     RECT  75.408 16.875 76.152 17.075 ;
     RECT  8.544 16.165 8.568 17.077 ;
     RECT  81.24 17.003 81.552 17.077 ;
     RECT  92.04 17.013 92.76 17.101 ;
     RECT  8.544 17.077 9.096 17.123 ;
     RECT  97.44 16.821 98.664 17.124 ;
     RECT  81.24 17.077 82.68 17.161 ;
     RECT  9.072 17.123 9.096 17.171 ;
     RECT  62.64 17.077 62.664 17.171 ;
     RECT  81.24 17.161 81.816 17.315 ;
     RECT  79.536 17.02 79.56 17.363 ;
     RECT  1.776 17.027 1.8 17.699 ;
     RECT  0.24 16.825 0.552 18.383 ;
     RECT  5.64 16.595 5.952 18.383 ;
     RECT  11.04 16.171 11.352 18.383 ;
     RECT  16.44 11.459 16.752 18.383 ;
     RECT  21.84 14.699 22.152 18.383 ;
     RECT  27.24 14.733 27.552 18.383 ;
     RECT  32.64 15.673 32.952 18.383 ;
     RECT  38.04 12.793 38.352 18.383 ;
     RECT  43.44 16.643 43.752 18.383 ;
     RECT  48.84 13.645 49.152 18.383 ;
     RECT  54.24 15.251 54.552 18.383 ;
     RECT  59.64 12.275 59.952 18.383 ;
     RECT  65.04 10.931 65.352 18.383 ;
     RECT  70.44 14.387 70.752 18.383 ;
     RECT  75.84 17.075 76.152 18.383 ;
     RECT  81.24 17.315 81.552 18.383 ;
     RECT  86.64 16.931 86.952 18.383 ;
     RECT  92.04 17.101 92.352 18.383 ;
     RECT  97.44 17.124 97.752 18.383 ;
     RECT  102.84 17.067 103.152 18.383 ;
     RECT  108.24 11.307 108.552 18.383 ;
     RECT  113.64 16.043 113.952 18.383 ;
     RECT  0.432 18.383 0.552 18.653 ;
     RECT  5.832 18.383 5.952 18.653 ;
     RECT  11.232 18.383 11.352 18.653 ;
     RECT  16.632 18.383 16.752 18.653 ;
     RECT  22.032 18.383 22.152 18.653 ;
     RECT  27.432 18.383 27.552 18.653 ;
     RECT  32.832 18.383 32.952 18.653 ;
     RECT  38.232 18.383 38.352 18.653 ;
     RECT  43.632 18.383 43.752 18.653 ;
     RECT  49.032 18.383 49.152 18.653 ;
     RECT  54.432 18.383 54.552 18.653 ;
     RECT  59.832 18.383 59.952 18.653 ;
     RECT  65.232 18.383 65.352 18.653 ;
     RECT  70.632 18.383 70.752 18.653 ;
     RECT  76.032 18.383 76.152 18.653 ;
     RECT  81.432 18.383 81.552 18.653 ;
     RECT  86.832 18.383 86.952 18.653 ;
     RECT  92.232 18.383 92.352 18.653 ;
     RECT  97.632 18.383 97.752 18.653 ;
     RECT  103.032 18.383 103.152 18.653 ;
     RECT  108.432 18.383 108.552 18.653 ;
     RECT  113.832 18.383 113.952 18.653 ;
     RECT  115.152 18.709 115.176 18.795 ;
    LAYER M6 ;
     RECT  0 6.396 0.133 7.26 ;
     RECT  0 11.796 0.133 12.66 ;
     RECT  0.133 3.456 0.613 8.288 ;
     RECT  0.133 11.796 0.613 12.832 ;
     RECT  0 17.196 0.613 18.06 ;
     RECT  0.613 15.488 1.093 18.06 ;
     RECT  1.093 14.976 1.314 18.06 ;
     RECT  0.613 11.328 1.653 13.28 ;
     RECT  1.314 14.592 1.653 18.06 ;
     RECT  0.613 3.456 1.669 9.44 ;
     RECT  1.653 11.328 1.669 18.06 ;
     RECT  1.669 3.456 1.763 18.06 ;
     RECT  1.763 4.096 58.933 18.06 ;
     RECT  58.933 4.096 94.691 18.784 ;
     RECT  94.691 4.096 94.891 13.664 ;
     RECT  94.891 4.096 95.795 8.544 ;
     RECT  94.891 9.92 95.795 13.664 ;
     RECT  95.795 9.92 95.998 13.472 ;
     RECT  95.795 6.272 97.043 8.544 ;
     RECT  95.998 9.984 98.675 13.472 ;
     RECT  94.691 14.976 98.675 18.784 ;
     RECT  95.795 4.096 99.203 4.704 ;
     RECT  97.043 6.272 99.435 8.416 ;
     RECT  98.675 15.488 101.413 15.712 ;
     RECT  98.675 17.024 101.413 18.784 ;
     RECT  101.413 15.488 101.507 18.784 ;
     RECT  101.507 15.68 102.083 18.784 ;
     RECT  99.203 4.096 102.659 4.128 ;
     RECT  102.613 8.576 102.699 8.608 ;
     RECT  99.435 6.272 102.709 7.26 ;
     RECT  102.709 4.992 104.915 7.26 ;
     RECT  98.675 9.984 108.899 12.66 ;
     RECT  108.899 10.176 110.291 12.66 ;
     RECT  110.291 10.176 111.203 10.208 ;
     RECT  0 0.996 113.76 1.86 ;
     RECT  110.291 11.796 113.76 12.66 ;
     RECT  102.083 16 113.76 18.784 ;
     RECT  113.76 1.572 114.544 1.86 ;
     RECT  104.915 6.272 114.544 7.26 ;
     RECT  113.76 12.372 114.544 12.66 ;
     RECT  113.76 17.772 114.544 18.784 ;
     RECT  113.76 16 114.611 16.032 ;
     RECT  114.544 6.272 115.187 6.304 ;
     RECT  114.544 18.752 115.187 18.784 ;
    LAYER M7 ;
     RECT  0.856 0.531 1.144 3.957 ;
     RECT  0.192 3.957 1.144 5.163 ;
     RECT  0.856 5.163 1.144 5.557 ;
     RECT  103.456 0.531 103.744 5.621 ;
     RECT  81.856 0.531 82.144 5.941 ;
     RECT  81.856 5.941 82.848 6.251 ;
     RECT  84.736 5.045 84.768 6.261 ;
     RECT  0.856 5.557 1.696 6.315 ;
     RECT  6.256 0.531 6.544 6.773 ;
     RECT  17.056 0.531 17.344 6.773 ;
     RECT  87.256 0.531 87.544 6.773 ;
     RECT  98.056 0.531 98.344 6.773 ;
     RECT  103.104 5.621 103.744 6.773 ;
     RECT  78.336 5.621 78.368 6.827 ;
     RECT  76.456 0.531 76.744 6.837 ;
     RECT  49.456 0.531 49.744 7.349 ;
     RECT  6.08 6.773 6.544 7.787 ;
     RECT  0.856 6.315 1.144 7.925 ;
     RECT  64.256 7.669 64.288 8.117 ;
     RECT  96.064 6.773 96.096 8.299 ;
     RECT  74.88 5.941 74.912 8.427 ;
     RECT  98.056 6.773 99.424 8.427 ;
     RECT  71.056 0.531 71.344 8.501 ;
     RECT  84.608 6.261 84.768 8.501 ;
     RECT  84.608 8.501 84.896 8.555 ;
     RECT  0.704 7.925 1.952 8.619 ;
     RECT  87.256 6.773 88.224 8.619 ;
     RECT  102.656 6.773 103.744 8.619 ;
     RECT  0.704 8.619 1.376 8.683 ;
     RECT  0.704 8.683 1.144 8.747 ;
     RECT  69.504 7.669 69.536 8.747 ;
     RECT  65.656 0.531 65.944 8.757 ;
     RECT  13.888 7.669 13.92 8.875 ;
     RECT  63.296 8.117 64.288 8.949 ;
     RECT  65.656 8.757 66.08 8.949 ;
     RECT  22.456 0.531 22.744 9.013 ;
     RECT  63.296 8.949 66.08 9.013 ;
     RECT  11.656 0.531 11.944 9.077 ;
     RECT  92.656 0.531 92.944 9.077 ;
     RECT  52.608 8.053 53.024 9.195 ;
     RECT  62.784 9.013 66.08 9.195 ;
     RECT  81.856 6.251 82.72 9.195 ;
     RECT  4.288 7.797 4.32 9.259 ;
     RECT  21.248 9.013 22.744 9.323 ;
     RECT  6.256 7.787 6.544 9.461 ;
     RECT  8.768 8.309 8.8 9.515 ;
     RECT  52.608 9.195 52.64 9.653 ;
     RECT  95.936 8.501 95.968 9.653 ;
     RECT  2.816 9.077 2.848 9.771 ;
     RECT  62.784 9.195 62.816 9.771 ;
     RECT  71.056 8.501 72.416 9.771 ;
     RECT  52.48 9.653 52.64 9.835 ;
     RECT  52.608 9.835 52.64 9.963 ;
     RECT  94.848 9.653 95.968 9.963 ;
     RECT  10.176 9.077 11.944 10.027 ;
     RECT  84.864 8.555 84.896 10.101 ;
     RECT  65.024 9.195 66.08 10.347 ;
     RECT  84.352 10.101 84.896 10.347 ;
     RECT  68.352 9.077 68.384 10.411 ;
     RECT  10.176 10.027 10.208 10.475 ;
     RECT  6.144 9.461 6.544 10.539 ;
     RECT  49.456 7.349 51.04 10.539 ;
     RECT  49.456 10.539 50.848 10.731 ;
     RECT  91.52 9.077 92.944 10.795 ;
     RECT  16.704 6.773 17.344 10.859 ;
     RECT  65.656 10.347 66.08 10.869 ;
     RECT  84.352 10.347 84.384 10.869 ;
     RECT  20.352 9.653 20.576 10.923 ;
     RECT  71.056 9.771 71.456 10.923 ;
     RECT  76.456 6.837 76.896 10.923 ;
     RECT  16.832 10.859 17.344 10.987 ;
     RECT  65.656 10.869 66.336 11.051 ;
     RECT  84.224 10.869 84.384 11.179 ;
     RECT  94.848 9.963 94.88 11.307 ;
     RECT  60.256 0.531 60.544 11.317 ;
     RECT  49.456 10.731 50.656 11.371 ;
     RECT  89.984 10.741 90.016 11.627 ;
     RECT  0.856 8.747 1.144 12.213 ;
     RECT  22.456 9.323 22.744 12.213 ;
     RECT  44.056 0.531 44.344 12.725 ;
     RECT  49.456 11.371 50.464 12.779 ;
     RECT  17.056 10.987 17.344 12.981 ;
     RECT  84.224 11.179 84.256 13.163 ;
     RECT  0.856 12.213 3.808 13.227 ;
     RECT  54.856 0.531 55.144 13.301 ;
     RECT  87.256 8.619 87.544 13.365 ;
     RECT  92.656 10.795 92.944 13.365 ;
     RECT  95.04 12.213 95.072 13.365 ;
     RECT  20.352 10.923 20.384 13.557 ;
     RECT  21.76 12.213 22.744 13.557 ;
     RECT  92.656 13.365 95.072 13.611 ;
     RECT  0.856 13.227 2.784 13.803 ;
     RECT  79.872 11.637 79.904 13.803 ;
     RECT  20.352 13.557 22.744 14.059 ;
     RECT  22.016 14.059 22.744 14.187 ;
     RECT  71.056 10.923 71.344 14.197 ;
     RECT  76.456 10.923 76.744 14.197 ;
     RECT  20.544 14.059 20.576 14.379 ;
     RECT  54.144 13.301 55.144 14.443 ;
     RECT  0.856 13.803 2.656 14.507 ;
     RECT  17.056 12.981 18.272 14.517 ;
     RECT  27.856 0.531 28.144 14.581 ;
     RECT  62.528 13.557 62.56 14.581 ;
     RECT  54.528 14.443 55.144 14.635 ;
     RECT  62.528 14.581 62.688 14.635 ;
     RECT  11.656 10.027 11.944 14.645 ;
     RECT  26.752 14.581 28.144 15.093 ;
     RECT  54.656 14.635 55.144 15.147 ;
     RECT  71.056 14.197 72.096 15.147 ;
     RECT  75.648 14.197 76.744 15.147 ;
     RECT  92.656 13.611 94.24 15.147 ;
     RECT  15.232 14.645 15.264 15.467 ;
     RECT  87.256 13.365 88.736 15.467 ;
     RECT  26.624 15.093 28.144 15.659 ;
     RECT  0.856 14.507 1.376 15.915 ;
     RECT  17.056 14.517 18.528 16.043 ;
     RECT  10.752 14.645 11.944 16.117 ;
     RECT  81.856 9.195 82.144 16.309 ;
     RECT  85.504 13.557 85.536 16.555 ;
     RECT  44.056 12.725 44.448 16.619 ;
     RECT  89.28 16.437 89.312 17.067 ;
     RECT  10.688 16.117 11.944 17.131 ;
     RECT  62.656 14.635 62.688 17.131 ;
     RECT  80.768 16.309 82.144 17.131 ;
     RECT  0.856 15.915 1.144 18.639 ;
     RECT  6.256 10.539 6.544 18.639 ;
     RECT  11.656 17.131 11.944 18.639 ;
     RECT  17.056 16.043 17.344 18.639 ;
     RECT  22.456 14.187 22.744 18.639 ;
     RECT  27.856 15.659 28.144 18.639 ;
     RECT  33.256 0.531 33.544 18.639 ;
     RECT  38.656 0.531 38.944 18.639 ;
     RECT  44.056 16.619 44.344 18.639 ;
     RECT  49.456 12.779 49.744 18.639 ;
     RECT  54.856 15.147 55.144 18.639 ;
     RECT  58.944 11.317 60.544 18.639 ;
     RECT  65.656 11.051 65.944 18.639 ;
     RECT  71.056 15.147 71.344 18.639 ;
     RECT  76.456 15.147 76.744 18.639 ;
     RECT  81.856 17.131 82.144 18.639 ;
     RECT  87.256 15.467 87.544 18.639 ;
     RECT  92.656 15.147 92.944 18.639 ;
     RECT  98.056 8.427 98.344 18.639 ;
     RECT  103.456 8.619 103.744 18.639 ;
     RECT  108.856 0.531 109.144 18.639 ;
     RECT  114.256 0.531 114.544 18.639 ;
     RECT  58.944 18.639 58.976 18.795 ;
  END
END hfd_stn_r17
END LIBRARY
